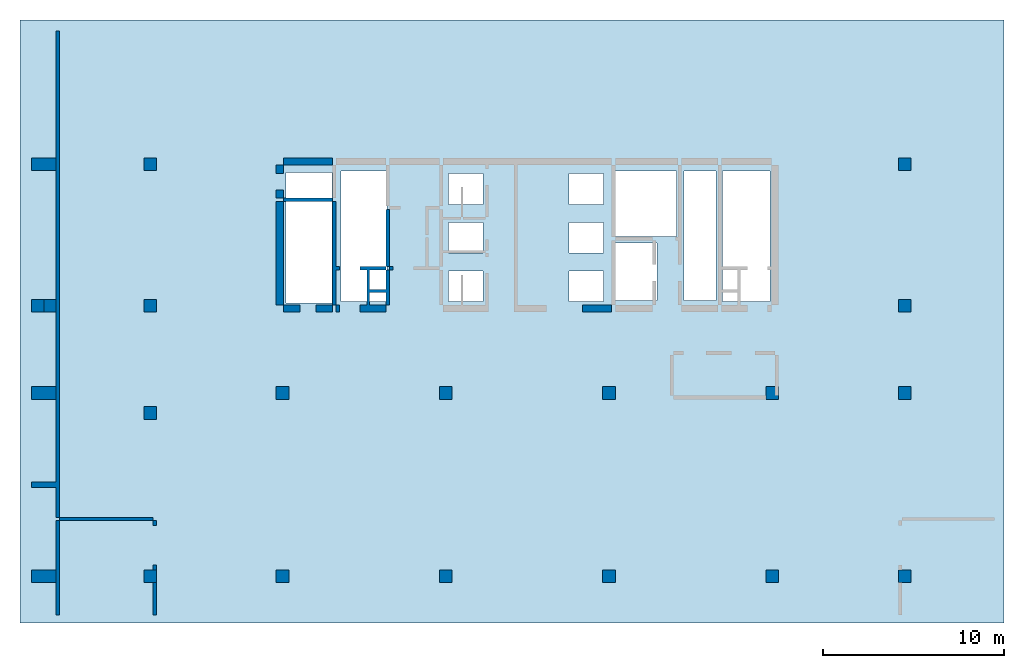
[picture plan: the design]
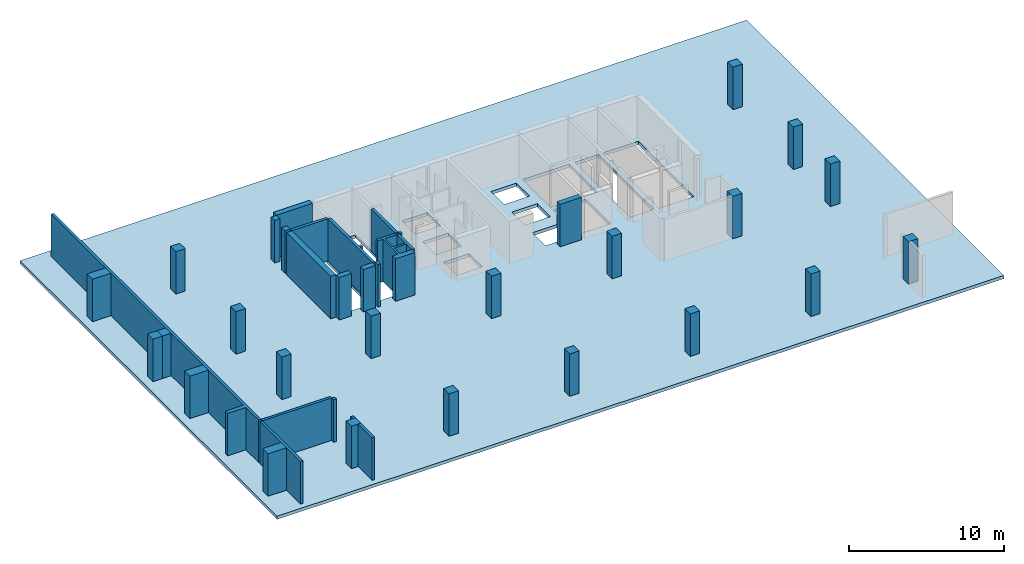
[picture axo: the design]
# One storey, part 1 of 2: 21 columns, 19 walls, 1 slab.
"""IFC4 building model written with IfcOpenShell, lengths in millimetres."""

from ifc_helpers import new_model, si_unit, frame, origin, place, context, project, spatial, triangles, element, save


model = new_model("IFC4")

# Units and contexts
model_context = context("Model", 3, precision=0.001, world=origin())
ifc_project = project(units=[si_unit("LENGTHUNIT", "METRE", prefix="MILLI"), si_unit("AREAUNIT", "SQUARE_METRE"), si_unit("VOLUMEUNIT", "CUBIC_METRE")], contexts=[model_context])

# Site, building, storey
site_placement = place(None, origin())
site = spatial("IfcSite", under=ifc_project, at=site_placement, CompositionType="ELEMENT")
building_placement = place(site_placement, origin())
building = spatial("IfcBuilding", under=site, at=building_placement, CompositionType="ELEMENT")
storey_placement = place(building_placement, frame((0.0, 0.0, -19800.0)))
storey = spatial("IfcBuildingStorey", under=building, at=storey_placement, Name="B5", CompositionType="ELEMENT", Elevation=-19800.0)

# Columns
column_1_placement = place(storey_placement, origin())
element("IfcColumn", 1, at=column_1_placement, inside=storey, Name="B5_Columns_B5_001", context=model_context, shape_type="Tessellation", body=[
    triangles([(40114.8, 2023.7, 0.0), (40114.8, 2023.7, 3350.0), (40114.8, 2722.3, 0.0), (40114.8, 2722.3, 3350.0), (40813.0, 2023.7, 3350.0), (40813.0, 2023.7, 0.0), (40813.0, 2722.3, 0.0), (40813.0, 2722.3, 3350.0)], [[1, 2, 3], [3, 2, 4], [5, 6, 7], [5, 7, 8], [6, 5, 1], [1, 5, 2], [8, 7, 3], [8, 3, 4], [3, 7, 1], [1, 7, 6], [8, 4, 2], [8, 2, 5]], closed=True),
])
column_2_placement = place(storey_placement, origin())
element("IfcColumn", 2, at=column_2_placement, inside=storey, Name="B5_Columns_B5_002", context=model_context, shape_type="Tessellation", body=[
    triangles([(5843.1, 24721.0, 0.0), (5843.1, 24721.0, 3350.0), (5843.1, 25419.5, 0.0), (5843.1, 25419.5, 3350.0), (6541.2, 24721.0, 3350.0), (6541.2, 24721.0, 0.0), (6541.2, 25419.5, 0.0), (6541.2, 25419.5, 3350.0)], [[1, 2, 3], [3, 2, 4], [5, 6, 7], [5, 7, 8], [6, 5, 1], [1, 5, 2], [8, 7, 3], [8, 3, 4], [1, 3, 6], [3, 7, 6], [4, 2, 5], [8, 4, 5]], closed=True),
])
column_3_placement = place(storey_placement, origin())
element("IfcColumn", 3, at=column_3_placement, inside=storey, Name="B5_Columns_B5_003", context=model_context, shape_type="Tessellation", body=[
    triangles([(5843.1, 16922.4, 0.0), (5843.1, 16922.4, 3350.0), (5843.1, 17620.9, 0.0), (5843.1, 17620.9, 3350.0), (6541.2, 16922.4, 3350.0), (6541.2, 16922.4, 0.0), (6541.2, 17620.9, 0.0), (6541.2, 17620.9, 3350.0)], [[1, 2, 3], [3, 2, 4], [5, 6, 7], [5, 7, 8], [6, 5, 1], [1, 5, 2], [8, 7, 3], [8, 3, 4], [1, 3, 6], [3, 7, 6], [4, 2, 5], [8, 4, 5]], closed=True),
])
column_4_placement = place(storey_placement, origin())
element("IfcColumn", 4, at=column_4_placement, inside=storey, Name="B5_Columns_B5_004", context=model_context, shape_type="Tessellation", body=[
    triangles([(47413.4, 24721.0, 0.0), (47413.4, 24721.0, 3350.0), (47413.4, 25419.5, 0.0), (47413.4, 25419.5, 3350.0), (48111.6, 24721.0, 3350.0), (48111.6, 24721.0, 0.0), (48111.6, 25419.5, 0.0), (48111.6, 25419.5, 3350.0)], [[1, 2, 3], [3, 2, 4], [5, 6, 7], [5, 7, 8], [6, 5, 1], [1, 5, 2], [8, 7, 3], [8, 3, 4], [1, 3, 6], [3, 7, 6], [4, 2, 5], [8, 4, 5]], closed=True),
])
column_5_placement = place(storey_placement, origin())
element("IfcColumn", 5, at=column_5_placement, inside=storey, Name="B5_Columns_B5_005", context=model_context, shape_type="Tessellation", body=[
    triangles([(47413.4, 16922.4, 0.0), (47413.4, 16922.4, 3350.0), (47413.4, 17620.9, 0.0), (47413.4, 17620.9, 3350.0), (48111.6, 16922.4, 3350.0), (48111.6, 16922.4, 0.0), (48111.6, 17620.9, 0.0), (48111.6, 17620.9, 3350.0)], [[1, 2, 3], [3, 2, 4], [5, 6, 7], [5, 7, 8], [6, 5, 1], [1, 5, 2], [8, 7, 3], [8, 3, 4], [1, 3, 6], [3, 7, 6], [4, 2, 5], [8, 4, 5]], closed=True),
])
column_6_placement = place(storey_placement, origin())
element("IfcColumn", 6, at=column_6_placement, inside=storey, Name="B5_Columns_B5_006", context=model_context, shape_type="Tessellation", body=[
    triangles([(-363.9, 16922.4, 0.0), (-363.9, 16922.4, 3350.0), (-363.9, 17620.9, 0.0), (-363.9, 17620.9, 3350.0), (994.3, 16922.4, 3350.0), (994.3, 16922.4, 0.0), (994.3, 17620.9, 0.0), (994.3, 17620.9, 3350.0)], [[1, 2, 3], [3, 2, 4], [5, 6, 7], [5, 7, 8], [6, 5, 1], [1, 5, 2], [8, 7, 3], [8, 3, 4], [3, 7, 1], [1, 7, 6], [8, 4, 2], [8, 2, 5]], closed=True),
])
column_7_placement = place(storey_placement, origin())
element("IfcColumn", 7, at=column_7_placement, inside=storey, Name="B5_Columns_B5_007", context=model_context, shape_type="Tessellation", body=[
    triangles([(13129.0, 2023.7, 0.0), (13129.0, 2023.7, 3350.0), (13129.0, 2722.3, 0.0), (13129.0, 2722.3, 3350.0), (13827.2, 2023.7, 3350.0), (13827.2, 2023.7, 0.0), (13827.2, 2722.3, 0.0), (13827.2, 2722.3, 3350.0)], [[1, 2, 3], [3, 2, 4], [5, 6, 7], [5, 7, 8], [6, 5, 1], [1, 5, 2], [8, 7, 3], [8, 3, 4], [3, 7, 1], [1, 7, 6], [8, 4, 2], [8, 2, 5]], closed=True),
])
column_8_placement = place(storey_placement, origin())
element("IfcColumn", 8, at=column_8_placement, inside=storey, Name="B5_Columns_B5_008", context=model_context, shape_type="Tessellation", body=[
    triangles([(-363.9, 16922.4, 0.0), (-363.9, 16922.4, 3350.0), (-363.9, 17620.9, 0.0), (-363.9, 17620.9, 3350.0), (334.3, 16922.4, 3350.0), (334.3, 16922.4, 0.0), (334.3, 17620.9, 0.0), (334.3, 17620.9, 3350.0)], [[1, 2, 3], [3, 2, 4], [5, 6, 7], [5, 7, 8], [6, 5, 1], [1, 5, 2], [8, 7, 3], [8, 3, 4], [3, 7, 1], [1, 7, 6], [8, 4, 2], [8, 2, 5]], closed=True),
])
column_9_placement = place(storey_placement, origin())
element("IfcColumn", 9, at=column_9_placement, inside=storey, Name="B5_Columns_B5_009", context=model_context, shape_type="Tessellation", body=[
    triangles([(47413.4, 2023.7, 0.0), (47413.4, 2023.7, 3350.0), (47413.4, 2722.3, 0.0), (47413.4, 2722.3, 3350.0), (48111.6, 2023.7, 3350.0), (48111.6, 2023.7, 0.0), (48111.6, 2722.3, 0.0), (48111.6, 2722.3, 3350.0)], [[1, 2, 3], [3, 2, 4], [5, 6, 7], [5, 7, 8], [6, 5, 1], [1, 5, 2], [8, 7, 3], [8, 3, 4], [3, 7, 1], [1, 7, 6], [8, 4, 2], [8, 2, 5]], closed=True),
])
column_10_placement = place(storey_placement, origin())
element("IfcColumn", 10, at=column_10_placement, inside=storey, Name="B5_Columns_B5_010", context=model_context, shape_type="Tessellation", body=[
    triangles([(13129.0, 12121.3, 0.0), (13129.0, 12121.3, 3350.0), (13129.0, 12819.8, 0.0), (13129.0, 12819.8, 3350.0), (13827.2, 12121.3, 3350.0), (13827.2, 12121.3, 0.0), (13827.2, 12819.8, 0.0), (13827.2, 12819.8, 3350.0)], [[1, 2, 3], [3, 2, 4], [5, 6, 7], [5, 7, 8], [6, 5, 1], [1, 5, 2], [8, 7, 3], [8, 3, 4], [3, 7, 1], [1, 7, 6], [8, 4, 2], [8, 2, 5]], closed=True),
])
column_11_placement = place(storey_placement, origin())
element("IfcColumn", 11, at=column_11_placement, inside=storey, Name="B5_Columns_B5_011", context=model_context, shape_type="Tessellation", body=[
    triangles([(5843.1, 11016.3, 0.0), (5843.1, 11016.3, 3350.0), (5843.1, 11727.5, 0.0), (5843.1, 11727.5, 3350.0), (6541.2, 11016.3, 3350.0), (6541.2, 11016.3, 0.0), (6541.2, 11727.5, 0.0), (6541.2, 11727.5, 3350.0)], [[1, 2, 3], [3, 2, 4], [5, 6, 7], [5, 7, 8], [6, 5, 1], [1, 5, 2], [8, 7, 3], [8, 3, 4], [3, 7, 1], [1, 7, 6], [8, 4, 2], [8, 2, 5]], closed=True),
])
column_12_placement = place(storey_placement, origin())
element("IfcColumn", 12, at=column_12_placement, inside=storey, Name="B5_Columns_B5_012", context=model_context, shape_type="Tessellation", body=[
    triangles([(40114.8, 12121.3, 0.0), (40114.8, 12121.3, 3350.0), (40114.8, 12819.8, 0.0), (40114.8, 12819.8, 3350.0), (40813.0, 12121.3, 3350.0), (40813.0, 12121.3, 0.0), (40813.0, 12819.8, 0.0), (40813.0, 12819.8, 3350.0)], [[1, 2, 3], [3, 2, 4], [5, 6, 7], [5, 7, 8], [6, 5, 1], [1, 5, 2], [8, 7, 3], [8, 3, 4], [1, 3, 6], [3, 7, 6], [4, 2, 5], [8, 4, 5]], closed=True),
])
column_13_placement = place(storey_placement, origin())
element("IfcColumn", 13, at=column_13_placement, inside=storey, Name="B5_Columns_B5_013", context=model_context, shape_type="Tessellation", body=[
    triangles([(47413.4, 12121.3, 0.0), (47413.4, 12121.3, 3350.0), (47413.4, 12819.8, 0.0), (47413.4, 12819.8, 3350.0), (48111.6, 12121.3, 3350.0), (48111.6, 12121.3, 0.0), (48111.6, 12819.8, 0.0), (48111.6, 12819.8, 3350.0)], [[1, 2, 3], [3, 2, 4], [5, 6, 7], [5, 7, 8], [6, 5, 1], [1, 5, 2], [8, 7, 3], [8, 3, 4], [1, 3, 6], [3, 7, 6], [4, 2, 5], [8, 4, 5]], closed=True),
])
column_14_placement = place(storey_placement, origin())
element("IfcColumn", 14, at=column_14_placement, inside=storey, Name="B5_Columns_B5_014", context=model_context, shape_type="Tessellation", body=[
    triangles([(5843.1, 2023.7, 0.0), (5843.1, 2023.7, 3350.0), (5843.1, 2722.3, 0.0), (5843.1, 2722.3, 3350.0), (6541.2, 2023.7, 3350.0), (6541.2, 2023.7, 0.0), (6541.2, 2722.3, 0.0), (6541.2, 2722.3, 3350.0)], [[1, 2, 3], [3, 2, 4], [5, 6, 7], [5, 7, 8], [6, 5, 1], [1, 5, 2], [8, 7, 3], [8, 3, 4], [1, 3, 6], [3, 7, 6], [4, 2, 5], [8, 4, 5]], closed=True),
])
column_15_placement = place(storey_placement, origin())
element("IfcColumn", 15, at=column_15_placement, inside=storey, Name="B5_Columns_B5_015", context=model_context, shape_type="Tessellation", body=[
    triangles([(-363.9, 2023.7, 0.0), (-363.9, 2023.7, 3350.0), (-363.9, 2722.3, 0.0), (-363.9, 2722.3, 3350.0), (994.3, 2023.7, 3350.0), (994.3, 2023.7, 0.0), (994.3, 2722.3, 0.0), (994.3, 2722.3, 3350.0)], [[1, 2, 3], [3, 2, 4], [5, 6, 7], [5, 7, 8], [6, 5, 1], [1, 5, 2], [8, 7, 3], [8, 3, 4], [3, 7, 1], [1, 7, 6], [8, 4, 2], [8, 2, 5]], closed=True),
])
column_16_placement = place(storey_placement, origin())
element("IfcColumn", 16, at=column_16_placement, inside=storey, Name="B5_Columns_B5_016", context=model_context, shape_type="Tessellation", body=[
    triangles([(-363.9, 24721.0, 0.0), (-363.9, 24721.0, 3350.0), (-363.9, 25419.5, 0.0), (-363.9, 25419.5, 3350.0), (994.3, 24721.0, 3350.0), (994.3, 24721.0, 0.0), (994.3, 25419.5, 0.0), (994.3, 25419.5, 3350.0)], [[1, 2, 3], [3, 2, 4], [5, 6, 7], [5, 7, 8], [6, 5, 1], [1, 5, 2], [8, 7, 3], [8, 3, 4], [3, 7, 1], [1, 7, 6], [8, 4, 2], [8, 2, 5]], closed=True),
])
column_17_placement = place(storey_placement, origin())
element("IfcColumn", 17, at=column_17_placement, inside=storey, Name="B5_Columns_B5_017", context=model_context, shape_type="Tessellation", body=[
    triangles([(-363.9, 12121.3, 0.0), (-363.9, 12121.3, 3350.0), (-363.9, 12819.8, 0.0), (-363.9, 12819.8, 3350.0), (994.3, 12121.3, 3350.0), (994.3, 12121.3, 0.0), (994.3, 12819.8, 0.0), (994.3, 12819.8, 3350.0)], [[1, 2, 3], [3, 2, 4], [5, 6, 7], [5, 7, 8], [6, 5, 1], [1, 5, 2], [8, 7, 3], [8, 3, 4], [3, 7, 1], [1, 7, 6], [8, 4, 2], [8, 2, 5]], closed=True),
])
column_18_placement = place(storey_placement, origin())
element("IfcColumn", 18, at=column_18_placement, inside=storey, Name="B5_Columns_B5_018", context=model_context, shape_type="Tessellation", body=[
    triangles([(31128.0, 12121.3, 0.0), (31128.0, 12121.3, 3350.0), (31128.0, 12819.8, 0.0), (31128.0, 12819.8, 3350.0), (31826.2, 12121.3, 3350.0), (31826.2, 12121.3, 0.0), (31826.2, 12819.8, 0.0), (31826.2, 12819.8, 3350.0)], [[1, 2, 3], [3, 2, 4], [5, 6, 7], [5, 7, 8], [6, 5, 1], [1, 5, 2], [8, 7, 3], [8, 3, 4], [3, 7, 1], [1, 7, 6], [8, 4, 2], [8, 2, 5]], closed=True),
])
column_19_placement = place(storey_placement, origin())
element("IfcColumn", 19, at=column_19_placement, inside=storey, Name="B5_Columns_B5_019", context=model_context, shape_type="Tessellation", body=[
    triangles([(22128.5, 12121.3, 0.0), (22128.5, 12121.3, 3350.0), (22128.5, 12819.8, 0.0), (22128.5, 12819.8, 3350.0), (22826.7, 12121.3, 3350.0), (22826.7, 12121.3, 0.0), (22826.7, 12819.8, 0.0), (22826.7, 12819.8, 3350.0)], [[1, 2, 3], [3, 2, 4], [5, 6, 7], [5, 7, 8], [6, 5, 1], [1, 5, 2], [8, 7, 3], [8, 3, 4], [3, 7, 1], [1, 7, 6], [8, 4, 2], [8, 2, 5]], closed=True),
])
column_20_placement = place(storey_placement, origin())
element("IfcColumn", 20, at=column_20_placement, inside=storey, Name="B5_Columns_B5_020", context=model_context, shape_type="Tessellation", body=[
    triangles([(31128.0, 2023.7, 0.0), (31128.0, 2023.7, 3350.0), (31128.0, 2722.3, 0.0), (31128.0, 2722.3, 3350.0), (31826.2, 2023.7, 3350.0), (31826.2, 2023.7, 0.0), (31826.2, 2722.3, 0.0), (31826.2, 2722.3, 3350.0)], [[1, 2, 3], [3, 2, 4], [5, 6, 7], [5, 7, 8], [6, 5, 1], [1, 5, 2], [8, 7, 3], [8, 3, 4], [3, 7, 1], [1, 7, 6], [8, 4, 2], [8, 2, 5]], closed=True),
])
column_21_placement = place(storey_placement, origin())
element("IfcColumn", 21, at=column_21_placement, inside=storey, Name="B5_Columns_B5_021", context=model_context, shape_type="Tessellation", body=[
    triangles([(22128.5, 2023.7, 0.0), (22128.5, 2023.7, 3350.0), (22128.5, 2722.3, 0.0), (22128.5, 2722.3, 3350.0), (22826.7, 2023.7, 3350.0), (22826.7, 2023.7, 0.0), (22826.7, 2722.3, 0.0), (22826.7, 2722.3, 3350.0)], [[1, 2, 3], [3, 2, 4], [5, 6, 7], [5, 7, 8], [6, 5, 1], [1, 5, 2], [8, 7, 3], [8, 3, 4], [3, 7, 1], [1, 7, 6], [8, 4, 2], [8, 2, 5]], closed=True),
])

# Slab
slab_placement = place(storey_placement, origin())
element("IfcSlab", 22, at=slab_placement, inside=storey, Name="B5_Slab_B5_001", context=model_context, shape_type="Tessellation", body=[
    triangles([(-987.250996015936, 33023.3766233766, 0.0), (53241.0358565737, 33023.3766233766, 0.0), (-987.250996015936, 33023.3766233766, -250.0), (53241.0358565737, 33023.3766233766, -250.0), (-987.250996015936, -211.688311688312, 0.0), (-987.250996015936, -211.688311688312, -250.0), (53241.0358565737, -211.688311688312, 0.0), (53241.0358565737, -211.688311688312, -250.0), (34130.6772908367, 20745.4545454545, -250.0), (31733.0677290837, 20745.4545454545, 0.0), (31733.0677290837, 20745.4545454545, -250.0), (34130.6772908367, 20745.4545454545, 0.0), (31733.0677290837, 17570.1298701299, 0.0), (31733.0677290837, 17570.1298701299, -250.0), (34130.6772908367, 17570.1298701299, 0.0), (34130.6772908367, 17570.1298701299, -250.0), (31168.9243027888, 19193.0735930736, 0.0), (29264.9402390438, 19193.0735930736, 0.0), (29264.9402390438, 19193.0735930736, -250.0), (31168.9243027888, 19193.0735930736, -250.0), (31168.9243027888, 17499.5670995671, 0.0), (31168.9243027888, 17499.5670995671, -250.0), (29264.9402390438, 17499.5670995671, 0.0), (29264.9402390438, 17499.5670995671, -250.0), (31168.9243027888, 21874.4588744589, 0.0), (29264.9402390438, 21874.4588744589, 0.0), (29264.9402390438, 21874.4588744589, -250.0), (31168.9243027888, 21874.4588744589, -250.0), (29264.9402390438, 20180.9523809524, 0.0), (29264.9402390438, 20180.9523809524, -250.0), (31168.9243027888, 20180.9523809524, 0.0), (31168.9243027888, 20180.9523809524, -250.0), (24540.2390438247, 19193.0735930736, -250.0), (22636.2549800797, 19193.0735930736, 0.0), (22636.2549800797, 19193.0735930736, -250.0), (24540.2390438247, 19193.0735930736, 0.0), (22636.2549800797, 17499.5670995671, 0.0), (22636.2549800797, 17499.5670995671, -250.0), (24540.2390438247, 17499.5670995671, 0.0), (24540.2390438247, 17499.5670995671, -250.0), (24540.2390438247, 21874.4588744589, -250.0), (22636.2549800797, 21874.4588744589, 0.0), (22636.2549800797, 21874.4588744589, -250.0), (24540.2390438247, 21874.4588744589, 0.0), (22636.2549800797, 20180.9523809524, 0.0), (22636.2549800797, 20180.9523809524, -250.0), (24540.2390438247, 20180.9523809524, 0.0), (24540.2390438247, 20180.9523809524, -250.0), (16219.1235059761, 24626.4069264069, 0.0), (13680.4780876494, 24626.4069264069, 0.0), (13680.4780876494, 24626.4069264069, -250.0), (16219.1235059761, 24626.4069264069, -250.0), (13680.4780876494, 17429.0043290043, 0.0), (13680.4780876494, 17429.0043290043, -250.0), (16219.1235059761, 17429.0043290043, 0.0), (16219.1235059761, 17429.0043290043, -250.0), (40336.2549800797, 24696.9696969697, -250.0), (37727.0916334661, 24696.9696969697, 0.0), (37727.0916334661, 24696.9696969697, -250.0), (40336.2549800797, 24696.9696969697, 0.0), (37727.0916334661, 17499.5670995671, 0.0), (37727.0916334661, 17499.5670995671, -250.0), (40336.2549800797, 17499.5670995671, 0.0), (40336.2549800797, 17499.5670995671, -250.0), (37374.5019920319, 24696.9696969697, 0.0), (35611.5537848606, 24696.9696969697, 0.0), (35611.5537848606, 24696.9696969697, -250.0), (37374.5019920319, 24696.9696969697, -250.0), (35611.5537848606, 17570.1298701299, 0.0), (35611.5537848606, 17570.1298701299, -250.0), (37374.5019920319, 17570.1298701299, 0.0), (37374.5019920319, 17570.1298701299, -250.0), (35188.4462151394, 24696.9696969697, 0.0), (31733.0677290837, 24696.9696969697, 0.0), (31733.0677290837, 24696.9696969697, -250.0), (35188.4462151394, 24696.9696969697, -250.0), (31733.0677290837, 21098.2683982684, 0.0), (31733.0677290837, 21098.2683982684, -250.0), (35188.4462151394, 21098.2683982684, 0.0), (35188.4462151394, 21098.2683982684, -250.0), (31168.9243027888, 24555.8441558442, 0.0), (29264.9402390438, 24555.8441558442, 0.0), (29264.9402390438, 24555.8441558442, -250.0), (31168.9243027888, 24555.8441558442, -250.0), (29264.9402390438, 22862.3376623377, 0.0), (29264.9402390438, 22862.3376623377, -250.0), (31168.9243027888, 22862.3376623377, 0.0), (31168.9243027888, 22862.3376623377, -250.0), (19251.3944223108, 24696.9696969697, 0.0), (16712.7490039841, 24696.9696969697, 0.0), (16712.7490039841, 24696.9696969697, -250.0), (19251.3944223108, 24696.9696969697, -250.0), (16712.7490039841, 17499.5670995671, 0.0), (16712.7490039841, 17499.5670995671, -250.0), (19251.3944223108, 17499.5670995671, 0.0), (19251.3944223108, 17499.5670995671, -250.0), (24540.2390438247, 24555.8441558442, -250.0), (22636.2549800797, 24555.8441558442, 0.0), (22636.2549800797, 24555.8441558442, -250.0), (24540.2390438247, 24555.8441558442, 0.0), (22636.2549800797, 22862.3376623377, 0.0), (22636.2549800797, 22862.3376623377, -250.0), (24540.2390438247, 22862.3376623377, 0.0), (24540.2390438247, 22862.3376623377, -250.0)], [[1, 2, 3], [3, 2, 4], [5, 1, 6], [6, 1, 3], [2, 7, 4], [4, 7, 8], [7, 5, 8], [8, 5, 6], [9, 10, 11], [12, 10, 9], [10, 13, 14], [10, 14, 11], [15, 12, 9], [15, 9, 16], [14, 15, 16], [13, 15, 14], [17, 18, 19], [17, 19, 20], [21, 17, 20], [21, 20, 22], [23, 21, 22], [23, 22, 24], [18, 23, 24], [18, 24, 19], [25, 26, 27], [25, 27, 28], [26, 29, 30], [26, 30, 27], [31, 25, 28], [31, 28, 32], [29, 31, 32], [29, 32, 30], [33, 34, 35], [36, 34, 33], [34, 37, 38], [34, 38, 35], [39, 36, 33], [39, 33, 40], [38, 39, 40], [37, 39, 38], [41, 42, 43], [44, 42, 41], [42, 45, 46], [42, 46, 43], [47, 44, 41], [47, 41, 48], [46, 47, 48], [45, 47, 46], [49, 50, 51], [49, 51, 52], [50, 53, 54], [50, 54, 51], [55, 49, 52], [55, 52, 56], [53, 55, 56], [53, 56, 54], [57, 58, 59], [60, 58, 57], [58, 61, 62], [58, 62, 59], [63, 60, 57], [63, 57, 64], [62, 63, 64], [61, 63, 62], [65, 66, 67], [65, 67, 68], [66, 69, 70], [66, 70, 67], [71, 65, 68], [71, 68, 72], [69, 71, 72], [69, 72, 70], [73, 74, 75], [73, 75, 76], [74, 77, 78], [74, 78, 75], [79, 73, 76], [79, 76, 80], [77, 79, 80], [77, 80, 78], [81, 82, 83], [81, 83, 84], [82, 85, 86], [82, 86, 83], [87, 81, 84], [87, 84, 88], [85, 87, 88], [85, 88, 86], [89, 90, 91], [89, 91, 92], [90, 93, 94], [90, 94, 91], [95, 89, 92], [95, 92, 96], [93, 95, 96], [93, 96, 94], [97, 98, 99], [100, 98, 97], [98, 101, 102], [98, 102, 99], [103, 100, 97], [103, 97, 104], [102, 103, 104], [101, 103, 102], [63, 61, 7], [7, 2, 63], [71, 69, 61], [61, 69, 7], [69, 15, 7], [2, 60, 63], [13, 21, 15], [15, 21, 7], [79, 12, 69], [69, 12, 15], [2, 58, 60], [2, 65, 58], [13, 17, 21], [21, 23, 7], [17, 10, 31], [2, 66, 65], [12, 77, 10], [10, 77, 31], [2, 73, 66], [66, 73, 79], [31, 18, 17], [77, 25, 31], [31, 29, 18], [77, 87, 25], [23, 39, 7], [2, 74, 73], [74, 81, 87], [87, 85, 25], [25, 85, 26], [23, 36, 39], [18, 36, 23], [74, 82, 81], [29, 47, 18], [18, 47, 36], [26, 44, 29], [29, 44, 47], [47, 45, 36], [36, 45, 34], [34, 95, 37], [45, 95, 34], [85, 103, 26], [26, 103, 44], [82, 103, 85], [45, 42, 95], [103, 42, 44], [82, 100, 103], [103, 101, 42], [39, 5, 7], [37, 5, 39], [95, 5, 37], [95, 55, 5], [93, 55, 95], [55, 53, 5], [101, 89, 42], [42, 89, 95], [98, 89, 101], [90, 49, 93], [93, 49, 55], [90, 50, 49], [50, 1, 53], [89, 1, 90], [53, 1, 5], [90, 1, 50], [2, 1, 74], [74, 1, 82], [82, 1, 100], [100, 1, 98], [98, 1, 89], [13, 10, 17], [69, 66, 79], [65, 71, 58], [58, 71, 61], [77, 74, 87], [79, 77, 12], [62, 64, 8], [4, 8, 64], [70, 72, 62], [70, 62, 8], [16, 70, 8], [57, 4, 64], [22, 14, 16], [22, 16, 8], [9, 80, 70], [9, 70, 16], [59, 4, 57], [68, 4, 59], [20, 14, 22], [24, 22, 8], [11, 20, 32], [67, 4, 68], [78, 9, 11], [78, 11, 32], [76, 4, 67], [76, 67, 80], [19, 32, 20], [28, 78, 32], [30, 32, 19], [88, 78, 28], [40, 24, 8], [75, 4, 76], [84, 75, 88], [86, 88, 28], [86, 28, 27], [33, 24, 40], [33, 19, 24], [83, 75, 84], [48, 30, 19], [48, 19, 33], [41, 27, 30], [41, 30, 48], [46, 48, 33], [46, 33, 35], [96, 35, 38], [96, 46, 35], [104, 86, 27], [104, 27, 41], [104, 83, 86], [43, 46, 96], [43, 104, 41], [97, 83, 104], [102, 104, 43], [6, 40, 8], [6, 38, 40], [6, 96, 38], [56, 96, 6], [56, 94, 96], [54, 56, 6], [92, 102, 43], [92, 43, 96], [92, 99, 102], [52, 91, 94], [52, 94, 56], [51, 91, 52], [3, 51, 54], [3, 92, 91], [3, 54, 6], [3, 91, 51], [3, 4, 75], [3, 75, 83], [3, 83, 97], [3, 97, 99], [3, 99, 92], [11, 14, 20], [67, 70, 80], [72, 68, 59], [72, 59, 62], [75, 78, 88], [78, 80, 9]], closed=True),
])

# Walls
wall_1_placement = place(storey_placement, origin())
element("IfcWall", 23, at=wall_1_placement, inside=storey, Name="B5_Walls_B5_001", context=model_context, shape_type="Tessellation", body=[
    triangles([(6541.2, 2023.7, 0.0), (6338.1, 2023.7, 0.0), (6338.1, 2023.7, 3350.0), (6541.2, 2023.7, 3350.0), (6541.2, 220.2, 0.0), (6541.2, 220.2, 3350.0), (6338.1, 220.2, 0.0), (6338.1, 220.2, 3350.0)], [[1, 2, 3], [1, 3, 4], [5, 1, 4], [5, 4, 6], [7, 5, 6], [7, 6, 8], [2, 7, 8], [2, 8, 3], [2, 1, 5], [2, 5, 7], [4, 3, 6], [6, 3, 8]], closed=True),
])
wall_2_placement = place(storey_placement, origin())
element("IfcWall", 24, at=wall_2_placement, inside=storey, Name="B5_Walls_B5_002", context=model_context, shape_type="Tessellation", body=[
    triangles([(1184.7, 220.2, 0.0), (1184.7, 5427.7, 0.0), (1184.7, 5427.7, 3350.0), (1184.7, 220.2, 3350.0), (994.3, 220.2, 0.0), (994.3, 220.2, 3350.0), (994.3, 5427.7, 0.0), (994.3, 5427.7, 3350.0)], [[1, 2, 3], [1, 3, 4], [5, 1, 4], [5, 4, 6], [7, 5, 6], [7, 6, 8], [2, 7, 8], [2, 8, 3], [7, 2, 1], [7, 1, 5], [3, 8, 4], [4, 8, 6]], closed=True),
])
wall_3_placement = place(storey_placement, origin())
element("IfcWall", 25, at=wall_3_placement, inside=storey, Name="B5_Walls_B5_003", context=model_context, shape_type="Tessellation", body=[
    triangles([(6541.2, 2722.3, 0.0), (6541.2, 2976.3, 0.0), (6541.2, 2976.3, 3350.0), (6541.2, 2722.3, 3350.0), (6338.1, 2722.3, 0.0), (6338.1, 2722.3, 3350.0), (6338.1, 2976.3, 0.0), (6338.1, 2976.3, 3350.0)], [[1, 2, 3], [1, 3, 4], [5, 1, 4], [5, 4, 6], [7, 5, 6], [7, 6, 8], [2, 7, 8], [2, 8, 3], [2, 1, 5], [7, 2, 5], [4, 3, 6], [3, 8, 6]], closed=True),
])
wall_4_placement = place(storey_placement, origin())
element("IfcWall", 26, at=wall_4_placement, inside=storey, Name="B5_Walls_B5_004", context=model_context, shape_type="Tessellation", body=[
    triangles([(6338.1, 5173.7, 0.0), (6541.2, 5173.7, 0.0), (6541.2, 5173.7, 3350.0), (6338.1, 5173.7, 3350.0), (6338.1, 5427.7, 0.0), (6338.1, 5427.7, 3350.0), (6541.2, 5427.7, 0.0), (6541.2, 5427.7, 3350.0)], [[1, 2, 3], [1, 3, 4], [5, 1, 4], [5, 4, 6], [7, 5, 6], [7, 6, 8], [2, 7, 8], [2, 8, 3], [7, 2, 1], [5, 7, 1], [3, 8, 4], [8, 6, 4]], closed=True),
])
wall_5_placement = place(storey_placement, origin())
element("IfcWall", 27, at=wall_5_placement, inside=storey, Name="B5_Walls_B5_005", context=model_context, shape_type="Tessellation", body=[
    triangles([(6338.1, 5427.7, 0.0), (6338.1, 5618.2, 0.0), (6338.1, 5618.2, 3350.0), (6338.1, 5427.7, 3350.0), (1184.7, 5427.7, 0.0), (1184.7, 5427.7, 3350.0), (1184.7, 5618.2, 0.0), (1184.7, 5618.2, 3350.0)], [[1, 2, 3], [1, 3, 4], [5, 1, 4], [5, 4, 6], [7, 5, 6], [7, 6, 8], [2, 7, 8], [2, 8, 3], [7, 2, 1], [7, 1, 5], [3, 8, 4], [4, 8, 6]], closed=True),
])
wall_6_placement = place(storey_placement, origin())
element("IfcWall", 28, at=wall_6_placement, inside=storey, Name="B5_Walls_B5_006", context=model_context, shape_type="Tessellation", body=[
    triangles([(-365.0, 7575.0, 0.0), (-365.0, 7270.0, 0.0), (-365.0, 7270.0, 3350.0), (-365.0, 7575.0, 3350.0), (994.3, 7575.0, 0.0), (994.3, 7575.0, 3350.0), (994.3, 32417.9, 0.0), (994.3, 32417.9, 3350.0), (1184.7, 32417.9, 0.0), (1184.7, 32417.9, 3350.0), (1184.7, 5618.2, 0.0), (1184.7, 5618.2, 3350.0), (994.3, 5618.2, 0.0), (994.3, 5618.2, 3350.0), (994.3, 7269.4, 0.0), (994.3, 7269.4, 3350.0), (-363.9, 7269.4, 0.0), (-363.9, 7269.4, 3350.0), (-363.9, 7270.0, 0.0), (-363.9, 7270.0, 3350.0)], [[1, 2, 3], [1, 3, 4], [5, 1, 4], [5, 4, 6], [7, 5, 6], [7, 6, 8], [9, 7, 8], [9, 8, 10], [11, 9, 10], [11, 10, 12], [13, 11, 12], [13, 12, 14], [15, 13, 14], [15, 14, 16], [17, 15, 16], [17, 16, 18], [19, 17, 18], [19, 18, 20], [2, 19, 20], [2, 20, 3], [15, 11, 13], [5, 11, 15], [19, 15, 17], [19, 5, 15], [1, 19, 2], [1, 5, 19], [7, 9, 5], [9, 11, 5], [12, 16, 14], [12, 6, 16], [16, 20, 18], [6, 20, 16], [20, 4, 3], [6, 4, 20], [10, 8, 6], [12, 10, 6]], closed=True),
])
wall_7_placement = place(storey_placement, origin())
element("IfcWall", 29, at=wall_7_placement, inside=storey, Name="B5_Walls_B5_007", context=model_context, shape_type="Tessellation", body=[
    triangles([(14436.4, 16922.4, 0.0), (14436.4, 17316.1, 0.0), (14436.4, 17316.1, 3350.0), (14436.4, 16922.4, 3350.0), (13535.2, 16922.4, 0.0), (13535.2, 16922.4, 3350.0), (13535.2, 17316.1, 0.0), (13535.2, 17316.1, 3350.0)], [[1, 2, 3], [1, 3, 4], [5, 1, 4], [5, 4, 6], [7, 5, 6], [7, 6, 8], [2, 7, 8], [2, 8, 3], [7, 2, 1], [7, 1, 5], [3, 8, 4], [4, 8, 6]], closed=True),
])
wall_8_placement = place(storey_placement, origin())
element("IfcWall", 30, at=wall_8_placement, inside=storey, Name="B5_Walls_B5_008", context=model_context, shape_type="Tessellation", body=[
    triangles([(16226.2, 16922.4, 0.0), (16226.2, 17316.1, 0.0), (16226.2, 17316.1, 3350.0), (16226.2, 16922.4, 3350.0), (15337.6, 16922.4, 0.0), (15337.6, 16922.4, 3350.0), (15337.6, 17316.1, 0.0), (15337.6, 17316.1, 3350.0)], [[1, 2, 3], [1, 3, 4], [5, 1, 4], [5, 4, 6], [7, 5, 6], [7, 6, 8], [2, 7, 8], [2, 8, 3], [7, 2, 1], [7, 1, 5], [3, 8, 4], [4, 8, 6]], closed=True),
])
wall_9_placement = place(storey_placement, origin())
element("IfcWall", 31, at=wall_9_placement, inside=storey, Name="B5_Walls_B5_009", context=model_context, shape_type="Tessellation", body=[
    triangles([(16632.4, 16922.4, 0.0), (16632.4, 17316.1, 0.0), (16632.4, 17316.1, 3350.0), (16632.4, 16922.4, 3350.0), (16429.3, 16922.4, 0.0), (16429.3, 16922.4, 3350.0), (16429.3, 17316.1, 0.0), (16429.3, 17316.1, 3350.0)], [[1, 2, 3], [1, 3, 4], [5, 1, 4], [5, 4, 6], [7, 5, 6], [7, 6, 8], [2, 7, 8], [2, 8, 3], [7, 2, 1], [7, 1, 5], [3, 8, 4], [4, 8, 6]], closed=True),
])
wall_10_placement = place(storey_placement, origin())
element("IfcWall", 32, at=wall_10_placement, inside=storey, Name="B5_Walls_B5_010", context=model_context, shape_type="Tessellation", body=[
    triangles([(18130.2, 19246.7, 0.0), (18130.2, 19245.0, 0.0), (18130.2, 19245.0, 3350.0), (18130.2, 19246.7, 3350.0), (18130.0, 19245.0, 0.0), (18130.0, 19245.0, 3350.0), (18130.0, 17316.1, 0.0), (18130.0, 17316.1, 3350.0), (17749.4, 17316.1, 0.0), (17749.4, 17316.1, 3350.0), (17749.4, 16922.4, 0.0), (17749.4, 16922.4, 3350.0), (19183.7, 16922.4, 0.0), (19183.7, 16922.4, 3350.0), (19183.7, 17316.1, 0.0), (19183.7, 17316.1, 3350.0), (19374.1, 17316.1, 0.0), (19374.1, 17316.1, 3350.0), (19374.1, 19246.7, 0.0), (19374.1, 19246.7, 3350.0), (19183.7, 19246.7, 0.0), (19183.7, 19246.7, 3350.0), (19183.7, 19449.9, 0.0), (19183.7, 19449.9, 3350.0), (17749.4, 19449.9, 0.0), (17749.4, 19449.9, 3350.0), (17749.4, 19246.7, 0.0), (17749.4, 19246.7, 3350.0), (18282.5, 17316.1, 0.0), (18282.5, 17316.1, 3350.0), (18282.5, 18014.7, 0.0), (18282.5, 18014.7, 3350.0), (19183.7, 18014.7, 0.0), (19183.7, 18014.7, 3350.0), (19183.7, 18167.1, 0.0), (19183.7, 18167.1, 3350.0), (18282.5, 18167.1, 0.0), (18282.5, 18167.1, 3350.0), (18282.5, 19246.7, 0.0), (18282.5, 19246.7, 3350.0)], [[1, 2, 3], [1, 3, 4], [2, 5, 6], [2, 6, 3], [5, 7, 8], [5, 8, 6], [7, 9, 10], [7, 10, 8], [9, 11, 12], [9, 12, 10], [11, 13, 14], [11, 14, 12], [13, 15, 16], [13, 16, 14], [15, 17, 18], [15, 18, 16], [19, 20, 18], [17, 19, 18], [19, 21, 22], [19, 22, 20], [21, 23, 24], [21, 24, 22], [23, 25, 26], [23, 26, 24], [25, 27, 28], [25, 28, 26], [27, 1, 4], [27, 4, 28], [15, 29, 30], [15, 30, 16], [29, 31, 32], [29, 32, 30], [31, 33, 34], [31, 34, 32], [33, 15, 16], [33, 16, 34], [21, 35, 36], [21, 36, 22], [35, 37, 38], [35, 38, 36], [37, 39, 40], [37, 40, 38], [39, 21, 22], [39, 22, 40], [33, 17, 15], [35, 17, 33], [29, 15, 13], [11, 29, 13], [7, 29, 11], [9, 7, 11], [31, 35, 33], [31, 29, 7], [19, 17, 35], [37, 35, 31], [21, 19, 35], [39, 23, 21], [2, 39, 37], [5, 2, 37], [1, 39, 2], [25, 1, 27], [25, 23, 39], [25, 39, 1], [7, 5, 37], [7, 37, 31], [18, 34, 16], [18, 36, 34], [16, 30, 14], [30, 12, 14], [30, 8, 12], [8, 10, 12], [36, 32, 34], [30, 32, 8], [18, 20, 36], [36, 38, 32], [20, 22, 36], [24, 40, 22], [40, 3, 38], [3, 6, 38], [40, 4, 3], [4, 26, 28], [24, 26, 40], [40, 26, 4], [6, 8, 38], [38, 8, 32]], closed=True),
])
wall_11_placement = place(storey_placement, origin())
element("IfcWall", 33, at=wall_11_placement, inside=storey, Name="B5_Walls_B5_011", context=model_context, shape_type="Tessellation", body=[
    triangles([(16632.4, 19449.9, 0.0), (16429.3, 19449.9, 0.0), (16429.3, 19449.9, 3350.0), (16632.4, 19449.9, 3350.0), (16632.4, 19246.7, 0.0), (16632.4, 19246.7, 3350.0), (16429.3, 19246.7, 0.0), (16429.3, 19246.7, 3350.0), (16429.3, 17316.1, 3350.0), (16429.3, 17316.1, 0.0), (16226.2, 17316.1, 0.0), (16226.2, 17316.1, 3350.0), (16226.2, 19246.7, 3350.0), (16226.2, 19246.7, 0.0), (16226.2, 19449.9, 0.0), (16226.2, 19449.9, 3350.0), (16226.2, 23019.0, 0.0), (16226.2, 23019.0, 3350.0), (16429.3, 23019.0, 0.0), (16429.3, 23019.0, 3350.0)], [[1, 2, 3], [1, 3, 4], [5, 1, 4], [5, 4, 6], [7, 5, 6], [7, 6, 8], [7, 8, 9], [10, 7, 9], [11, 10, 9], [11, 9, 12], [11, 12, 13], [14, 11, 13], [15, 14, 13], [15, 13, 16], [17, 15, 16], [17, 16, 18], [19, 17, 18], [19, 18, 20], [2, 19, 20], [2, 20, 3], [14, 7, 10], [14, 10, 11], [2, 1, 5], [2, 5, 7], [15, 2, 7], [15, 7, 14], [19, 2, 15], [17, 19, 15], [8, 13, 9], [9, 13, 12], [4, 3, 6], [6, 3, 8], [3, 16, 8], [8, 16, 13], [3, 20, 16], [20, 18, 16]], closed=True),
])
wall_12_placement = place(storey_placement, origin())
element("IfcWall", 34, at=wall_12_placement, inside=storey, Name="B5_Walls_B5_012", context=model_context, shape_type="Tessellation", body=[
    triangles([(13129.0, 23019.0, 0.0), (13129.0, 17316.1, 0.0), (13129.0, 17316.1, 3350.0), (13129.0, 23019.0, 3350.0), (13535.2, 23019.0, 0.0), (13535.2, 23019.0, 3350.0), (13535.2, 17316.1, 0.0), (13535.2, 17316.1, 3350.0)], [[1, 2, 3], [1, 3, 4], [5, 1, 4], [5, 4, 6], [7, 5, 6], [7, 6, 8], [2, 7, 8], [2, 8, 3], [1, 5, 7], [1, 7, 2], [6, 4, 8], [8, 4, 3]], closed=True),
])
wall_13_placement = place(storey_placement, origin())
element("IfcWall", 35, at=wall_13_placement, inside=storey, Name="B5_Walls_B5_013", context=model_context, shape_type="Tessellation", body=[
    triangles([(16226.2, 23019.0, 0.0), (16226.2, 23222.2, 0.0), (16226.2, 23222.2, 3350.0), (16226.2, 23019.0, 3350.0), (13535.2, 23019.0, 0.0), (13535.2, 23019.0, 3350.0), (13535.2, 23222.2, 0.0), (13535.2, 23222.2, 3350.0)], [[1, 2, 3], [1, 3, 4], [5, 1, 4], [5, 4, 6], [7, 5, 6], [7, 6, 8], [2, 7, 8], [2, 8, 3], [7, 2, 1], [7, 1, 5], [3, 8, 4], [4, 8, 6]], closed=True),
])
wall_14_placement = place(storey_placement, origin())
element("IfcWall", 36, at=wall_14_placement, inside=storey, Name="B5_Walls_B5_014", context=model_context, shape_type="Tessellation", body=[
    triangles([(13535.2, 23222.2, 0.0), (13535.2, 23666.8, 0.0), (13535.2, 23666.8, 3350.0), (13535.2, 23222.2, 3350.0), (13129.0, 23222.2, 0.0), (13129.0, 23222.2, 3350.0), (13129.0, 23666.8, 0.0), (13129.0, 23666.8, 3350.0)], [[1, 2, 3], [1, 3, 4], [5, 1, 4], [5, 4, 6], [7, 5, 6], [7, 6, 8], [2, 7, 8], [2, 8, 3], [7, 2, 1], [7, 1, 5], [3, 8, 4], [4, 8, 6]], closed=True),
])
wall_15_placement = place(storey_placement, origin())
element("IfcWall", 37, at=wall_15_placement, inside=storey, Name="B5_Walls_B5_016", context=model_context, shape_type="Tessellation", body=[
    triangles([(13535.2, 25025.8, 0.0), (13129.0, 25025.8, 0.0), (13129.0, 25025.8, 3350.0), (13535.2, 25025.8, 3350.0), (13535.2, 24568.5, 0.0), (13535.2, 24568.5, 3350.0), (13129.0, 24568.5, 0.0), (13129.0, 24568.5, 3350.0)], [[1, 2, 3], [1, 3, 4], [5, 1, 4], [5, 4, 6], [7, 5, 6], [7, 6, 8], [2, 7, 8], [2, 8, 3], [2, 1, 5], [2, 5, 7], [4, 3, 6], [6, 3, 8]], closed=True),
])
wall_16_placement = place(storey_placement, origin())
element("IfcWall", 38, at=wall_16_placement, inside=storey, Name="B5_Walls_B5_017", context=model_context, shape_type="Tessellation", body=[
    triangles([(13535.2, 25025.8, 0.0), (16226.2, 25025.8, 0.0), (16226.2, 25025.8, 3350.0), (13535.2, 25025.8, 3350.0), (13535.2, 25419.5, 0.0), (13535.2, 25419.5, 3350.0), (16226.2, 25419.5, 0.0), (16226.2, 25419.5, 3350.0)], [[1, 2, 3], [1, 3, 4], [5, 1, 4], [5, 4, 6], [7, 5, 6], [7, 6, 8], [2, 7, 8], [2, 8, 3], [1, 7, 2], [5, 7, 1], [8, 4, 3], [8, 6, 4]], closed=True),
])
wall_17_placement = place(storey_placement, origin())
element("IfcWall", 39, at=wall_17_placement, inside=storey, Name="B5_Walls_B5_021", context=model_context, shape_type="Tessellation", body=[
    triangles([(19577.2, 19449.9, 0.0), (19374.1, 19449.9, 0.0), (19374.1, 19449.9, 3350.0), (19577.2, 19449.9, 3350.0), (19577.2, 19246.7, 0.0), (19577.2, 19246.7, 3350.0), (19374.1, 19246.7, 0.0), (19374.1, 19246.7, 3350.0)], [[1, 2, 3], [1, 3, 4], [5, 1, 4], [5, 4, 6], [7, 5, 6], [7, 6, 8], [2, 7, 8], [2, 8, 3], [2, 1, 5], [2, 5, 7], [4, 3, 6], [6, 3, 8]], closed=True),
])
wall_18_placement = place(storey_placement, origin())
element("IfcWall", 40, at=wall_18_placement, inside=storey, Name="B5_Walls_B5_026", context=model_context, shape_type="Tessellation", body=[
    triangles([(19374.1, 19449.9, 0.0), (19374.1, 22574.4, 0.0), (19374.1, 22574.4, 3350.0), (19374.1, 19449.9, 3350.0), (19183.7, 19449.9, 0.0), (19183.7, 19449.9, 3350.0), (19183.7, 22574.4, 0.0), (19183.7, 22574.4, 3350.0)], [[1, 2, 3], [1, 3, 4], [5, 1, 4], [5, 4, 6], [7, 5, 6], [7, 6, 8], [2, 7, 8], [2, 8, 3], [2, 1, 5], [7, 2, 5], [4, 3, 6], [3, 8, 6]], closed=True),
])
wall_19_placement = place(storey_placement, origin())
element("IfcWall", 41, at=wall_19_placement, inside=storey, Name="B5_Walls_B5_038", context=model_context, shape_type="Tessellation", body=[
    triangles([(31623.1, 16922.4, 0.0), (31623.1, 17316.1, 0.0), (31623.1, 17316.1, 3350.0), (31623.1, 16922.4, 3350.0), (30023.7, 16922.4, 0.0), (30023.7, 16922.4, 3350.0), (30023.7, 17316.1, 0.0), (30023.7, 17316.1, 3350.0)], [[1, 2, 3], [1, 3, 4], [5, 1, 4], [5, 4, 6], [7, 5, 6], [7, 6, 8], [2, 7, 8], [2, 8, 3], [7, 2, 1], [7, 1, 5], [3, 8, 4], [4, 8, 6]], closed=True),
])

save(model, "model.ifc")
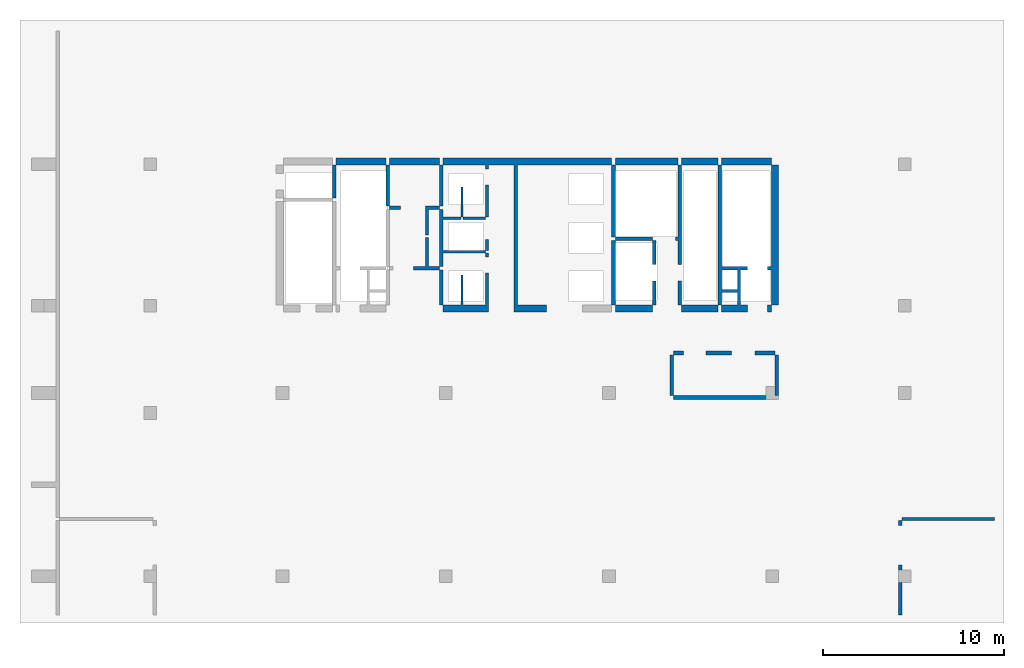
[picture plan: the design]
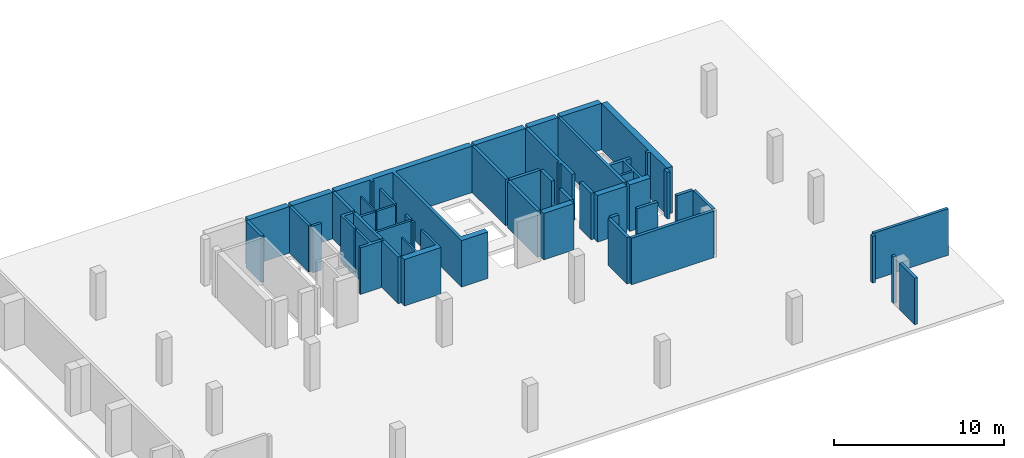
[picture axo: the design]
# One storey, part 2 of 2: 42 walls.
"""IFC4 building model written with IfcOpenShell, lengths in millimetres."""

from ifc_helpers import new_model, si_unit, frame, origin, place, context, project, spatial, triangles, element, save


model = new_model("IFC4")

# Units and contexts
model_context = context("Model", 3, precision=0.001, world=origin())
ifc_project = project(units=[si_unit("LENGTHUNIT", "METRE", prefix="MILLI"), si_unit("AREAUNIT", "SQUARE_METRE"), si_unit("VOLUMEUNIT", "CUBIC_METRE")], contexts=[model_context])

# Site, building, storey
site_placement = place(None, origin())
site = spatial("IfcSite", under=ifc_project, at=site_placement, CompositionType="ELEMENT")
building_placement = place(site_placement, origin())
building = spatial("IfcBuilding", under=site, at=building_placement, CompositionType="ELEMENT")
storey_placement = place(building_placement, frame((0.0, 0.0, -19800.0)))
storey = spatial("IfcBuildingStorey", under=building, at=storey_placement, Name="B5", CompositionType="ELEMENT", Elevation=-19800.0)

# Walls
wall_1_placement = place(storey_placement, origin())
element("IfcWall", 1, at=wall_1_placement, inside=storey, Name="B5_Walls_B5_015", context=model_context, shape_type="Tessellation", body=[
    triangles([(16429.3, 23222.2, 0.0), (16429.3, 25025.8, 0.0), (16429.3, 25025.8, 3350.0), (16429.3, 23222.2, 3350.0), (16226.2, 23222.2, 0.0), (16226.2, 23222.2, 3350.0), (16226.2, 25025.8, 0.0), (16226.2, 25025.8, 3350.0)], [[1, 2, 3], [1, 3, 4], [5, 1, 4], [5, 4, 6], [7, 5, 6], [7, 6, 8], [2, 7, 8], [2, 8, 3], [7, 2, 1], [7, 1, 5], [3, 8, 4], [4, 8, 6]], closed=True),
])
wall_2_placement = place(storey_placement, origin())
element("IfcWall", 2, at=wall_2_placement, inside=storey, Name="B5_Walls_B5_018", context=model_context, shape_type="Tessellation", body=[
    triangles([(19183.7, 25419.5, 0.0), (16429.3, 25419.5, 0.0), (16429.3, 25419.5, 3350.0), (19183.7, 25419.5, 3350.0), (19183.7, 25025.8, 0.0), (19183.7, 25025.8, 3350.0), (16429.3, 25025.8, 0.0), (16429.3, 25025.8, 3350.0)], [[1, 2, 3], [1, 3, 4], [5, 1, 4], [5, 4, 6], [7, 5, 6], [7, 6, 8], [2, 7, 8], [2, 8, 3], [2, 1, 5], [2, 5, 7], [4, 3, 6], [6, 3, 8]], closed=True),
])
wall_3_placement = place(storey_placement, origin())
element("IfcWall", 3, at=wall_3_placement, inside=storey, Name="B5_Walls_B5_019", context=model_context, shape_type="Tessellation", body=[
    triangles([(23423.2, 18967.3, 0.0), (23321.7, 18967.3, 0.0), (23321.7, 18967.3, 3350.0), (23423.2, 18967.3, 3350.0), (23423.2, 18965.0, 0.0), (23423.2, 18965.0, 3350.0), (23425.0, 18965.0, 0.0), (23425.0, 18965.0, 3350.0), (23425.0, 17316.1, 3350.0), (23425.0, 17316.1, 0.0), (24679.9, 17316.1, 0.0), (24679.9, 17316.1, 3350.0), (24679.9, 19068.9, 0.0), (24679.9, 19068.9, 3350.0), (24680.0, 19068.9, 3350.0), (24680.0, 19068.9, 0.0), (24680.0, 19070.0, 0.0), (24680.0, 19070.0, 3350.0), (24830.0, 19070.0, 0.0), (24830.0, 19070.0, 3350.0), (24830.0, 19068.9, 0.0), (24830.0, 19068.9, 3350.0), (24832.2, 19068.9, 3350.0), (24832.2, 19068.9, 0.0), (24832.2, 17316.1, 0.0), (24832.2, 17316.1, 3350.0), (24832.2, 16922.4, 0.0), (24832.2, 16922.4, 3350.0), (22331.6, 16922.4, 0.0), (22331.6, 16922.4, 3350.0), (22331.6, 17316.1, 0.0), (22331.6, 17316.1, 3350.0), (23320.0, 17316.1, 0.0), (23320.0, 17316.1, 3350.0), (23320.0, 18965.0, 3350.0), (23320.0, 18965.0, 0.0), (23321.7, 18965.0, 0.0), (23321.7, 18965.0, 3350.0)], [[1, 2, 3], [1, 3, 4], [5, 1, 4], [5, 4, 6], [7, 5, 6], [7, 6, 8], [7, 8, 9], [10, 7, 9], [11, 10, 9], [11, 9, 12], [13, 11, 12], [13, 12, 14], [13, 14, 15], [16, 13, 15], [17, 16, 15], [17, 15, 18], [19, 17, 18], [19, 18, 20], [21, 19, 20], [21, 20, 22], [21, 22, 23], [24, 21, 23], [25, 24, 23], [25, 23, 26], [27, 25, 26], [27, 26, 28], [29, 27, 28], [29, 28, 30], [31, 29, 30], [31, 30, 32], [33, 31, 32], [33, 32, 34], [33, 34, 35], [36, 33, 35], [37, 36, 35], [37, 35, 38], [2, 37, 38], [2, 38, 3], [11, 25, 27], [10, 11, 27], [21, 24, 25], [21, 25, 11], [16, 19, 21], [16, 21, 11], [13, 16, 11], [17, 19, 16], [29, 10, 27], [29, 33, 10], [31, 33, 29], [5, 7, 10], [5, 10, 33], [37, 1, 5], [37, 5, 33], [36, 37, 33], [2, 1, 37], [26, 12, 28], [12, 9, 28], [23, 22, 26], [26, 22, 12], [20, 15, 22], [22, 15, 12], [15, 14, 12], [20, 18, 15], [9, 30, 28], [34, 30, 9], [34, 32, 30], [8, 6, 9], [9, 6, 34], [4, 38, 6], [6, 38, 34], [38, 35, 34], [4, 3, 38]], closed=True),
])
wall_4_placement = place(storey_placement, origin())
element("IfcWall", 4, at=wall_4_placement, inside=storey, Name="B5_Walls_B5_020", context=model_context, shape_type="Tessellation", body=[
    triangles([(22331.6, 19246.7, 0.0), (22331.6, 19246.7, 3350.0), (22331.6, 17316.1, 3350.0), (22331.6, 17316.1, 0.0), (22128.5, 17316.1, 0.0), (22128.5, 17316.1, 3350.0), (22128.5, 19246.7, 3350.0), (22128.5, 19246.7, 0.0)], [[1, 2, 3], [4, 1, 3], [5, 4, 3], [5, 3, 6], [5, 6, 7], [8, 5, 7], [1, 8, 7], [1, 7, 2], [8, 1, 4], [8, 4, 5], [2, 7, 3], [3, 7, 6]], closed=True),
])
wall_5_placement = place(storey_placement, origin())
element("IfcWall", 5, at=wall_5_placement, inside=storey, Name="B5_Walls_B5_022", context=model_context, shape_type="Tessellation", body=[
    triangles([(21366.9, 21024.9, 0.0), (21366.9, 19449.9, 0.0), (21366.9, 19449.9, 3350.0), (21366.9, 21024.9, 3350.0), (21519.3, 21024.9, 3350.0), (21519.3, 21024.9, 0.0), (21519.3, 19449.9, 0.0), (21519.3, 19449.9, 3350.0), (22128.5, 19449.9, 0.0), (22128.5, 19449.9, 3350.0), (22128.5, 19246.7, 0.0), (22128.5, 19246.7, 3350.0), (20694.2, 19246.7, 0.0), (20694.2, 19246.7, 3350.0), (20694.2, 19449.9, 0.0), (20694.2, 19449.9, 3350.0)], [[1, 2, 3], [1, 3, 4], [1, 4, 5], [6, 1, 5], [7, 6, 5], [7, 5, 8], [9, 7, 8], [9, 8, 10], [11, 9, 10], [11, 10, 12], [13, 11, 12], [13, 12, 14], [15, 13, 14], [15, 14, 16], [2, 15, 16], [2, 16, 3], [7, 9, 11], [2, 7, 11], [13, 2, 11], [15, 2, 13], [1, 6, 7], [1, 7, 2], [10, 8, 12], [8, 3, 12], [3, 14, 12], [3, 16, 14], [5, 4, 8], [8, 4, 3]], closed=True),
])
wall_6_placement = place(storey_placement, origin())
element("IfcWall", 6, at=wall_6_placement, inside=storey, Name="B5_Walls_B5_023", context=model_context, shape_type="Tessellation", body=[
    triangles([(24832.2, 19970.7, 0.0), (24832.2, 20173.9, 0.0), (24832.2, 20173.9, 3350.0), (24832.2, 19970.7, 3350.0), (24679.9, 19970.7, 0.0), (24679.9, 19970.7, 3350.0), (24679.9, 20173.9, 0.0), (24679.9, 20173.9, 3350.0)], [[1, 2, 3], [1, 3, 4], [5, 1, 4], [5, 4, 6], [7, 5, 6], [7, 6, 8], [2, 7, 8], [2, 8, 3], [7, 2, 1], [7, 1, 5], [3, 8, 4], [4, 8, 6]], closed=True),
])
wall_7_placement = place(storey_placement, origin())
element("IfcWall", 7, at=wall_7_placement, inside=storey, Name="B5_Walls_B5_024", context=model_context, shape_type="Tessellation", body=[
    triangles([(22128.5, 22574.4, 0.0), (22128.5, 19449.9, 0.0), (22128.5, 19449.9, 3350.0), (22128.5, 22574.4, 3350.0), (22331.6, 22574.4, 0.0), (22331.6, 22574.4, 3350.0), (22331.6, 22168.0, 0.0), (22331.6, 22168.0, 3350.0), (23321.7, 22168.0, 3350.0), (23321.7, 22168.0, 0.0), (23321.7, 22015.6, 0.0), (23321.7, 22015.6, 3350.0), (22331.6, 22015.6, 3350.0), (22331.6, 22015.6, 0.0), (22331.6, 20326.3, 0.0), (22331.6, 20326.3, 3350.0), (24679.9, 20326.3, 0.0), (24679.9, 20326.3, 3350.0), (24679.9, 20173.9, 3350.0), (24679.9, 20173.9, 0.0), (22331.6, 20173.9, 0.0), (22331.6, 20173.9, 3350.0), (22331.6, 19449.9, 3350.0), (22331.6, 19449.9, 0.0)], [[1, 2, 3], [1, 3, 4], [5, 1, 4], [5, 4, 6], [7, 5, 6], [7, 6, 8], [7, 8, 9], [10, 7, 9], [11, 10, 9], [11, 9, 12], [11, 12, 13], [14, 11, 13], [15, 14, 13], [15, 13, 16], [17, 15, 16], [17, 16, 18], [17, 18, 19], [20, 17, 19], [21, 20, 19], [21, 19, 22], [21, 22, 23], [24, 21, 23], [2, 24, 23], [2, 23, 3], [21, 24, 2], [15, 17, 20], [15, 20, 21], [15, 21, 2], [14, 10, 11], [7, 10, 14], [1, 5, 7], [1, 14, 15], [1, 7, 14], [2, 1, 15], [23, 22, 3], [18, 16, 19], [19, 16, 22], [22, 16, 3], [9, 13, 12], [9, 8, 13], [6, 4, 8], [13, 4, 16], [8, 4, 13], [4, 3, 16]], closed=True),
])
wall_8_placement = place(storey_placement, origin())
element("IfcWall", 8, at=wall_8_placement, inside=storey, Name="B5_Walls_B5_025", context=model_context, shape_type="Tessellation", body=[
    triangles([(24679.9, 20326.3, 0.0), (24832.2, 20326.3, 0.0), (24832.2, 20326.3, 3350.0), (24679.9, 20326.3, 3350.0), (24679.9, 20923.3, 0.0), (24679.9, 20923.3, 3350.0), (24832.2, 20923.3, 0.0), (24832.2, 20923.3, 3350.0)], [[1, 2, 3], [1, 3, 4], [5, 1, 4], [5, 4, 6], [7, 5, 6], [7, 6, 8], [2, 7, 8], [2, 8, 3], [5, 2, 1], [5, 7, 2], [3, 6, 4], [8, 6, 3]], closed=True),
])
wall_9_placement = place(storey_placement, origin())
element("IfcWall", 9, at=wall_9_placement, inside=storey, Name="B5_Walls_B5_027", context=model_context, shape_type="Tessellation", body=[
    triangles([(22128.5, 22765.0, 0.0), (21366.9, 22765.0, 0.0), (21366.9, 22765.0, 3350.0), (22128.5, 22765.0, 3350.0), (22128.5, 22574.4, 0.0), (22128.5, 22574.4, 3350.0), (21519.3, 22574.4, 0.0), (21519.3, 22574.4, 3350.0), (21519.3, 21177.3, 0.0), (21519.3, 21177.3, 3350.0), (21366.9, 21177.3, 3350.0), (21366.9, 21177.3, 0.0), (21366.9, 22574.4, 0.0), (21366.9, 22574.4, 3350.0)], [[1, 2, 3], [1, 3, 4], [5, 1, 4], [5, 4, 6], [7, 5, 6], [7, 6, 8], [9, 7, 8], [9, 8, 10], [9, 10, 11], [12, 9, 11], [13, 12, 11], [13, 11, 14], [2, 13, 14], [2, 14, 3], [7, 1, 5], [13, 7, 9], [13, 9, 12], [2, 1, 7], [2, 7, 13], [4, 8, 6], [8, 14, 10], [10, 14, 11], [4, 3, 8], [8, 3, 14]], closed=True),
])
wall_10_placement = place(storey_placement, origin())
element("IfcWall", 10, at=wall_10_placement, inside=storey, Name="B5_Walls_B5_028", context=model_context, shape_type="Tessellation", body=[
    triangles([(23423.2, 22168.0, 0.0), (23423.2, 22168.0, 3350.0), (24679.9, 22168.0, 3350.0), (24679.9, 22168.0, 0.0), (24679.9, 22015.6, 0.0), (24679.9, 22015.6, 3350.0), (23423.2, 22015.6, 3350.0), (23423.2, 22015.6, 0.0)], [[1, 2, 3], [4, 1, 3], [5, 4, 3], [5, 3, 6], [5, 6, 7], [8, 5, 7], [1, 8, 7], [1, 7, 2], [1, 4, 5], [1, 5, 8], [3, 2, 6], [6, 2, 7]], closed=True),
])
wall_11_placement = place(storey_placement, origin())
element("IfcWall", 11, at=wall_11_placement, inside=storey, Name="B5_Walls_B5_029", context=model_context, shape_type="Tessellation", body=[
    triangles([(19970.7, 22574.4, 0.0), (19970.7, 22765.0, 0.0), (19970.7, 22765.0, 3350.0), (19970.7, 22574.4, 3350.0), (19374.1, 22574.4, 0.0), (19374.1, 22574.4, 3350.0), (19374.1, 22765.0, 0.0), (19374.1, 22765.0, 3350.0)], [[1, 2, 3], [1, 3, 4], [5, 1, 4], [5, 4, 6], [7, 5, 6], [7, 6, 8], [2, 7, 8], [2, 8, 3], [7, 2, 1], [7, 1, 5], [3, 8, 4], [4, 8, 6]], closed=True),
])
wall_12_placement = place(storey_placement, origin())
element("IfcWall", 12, at=wall_12_placement, inside=storey, Name="B5_Walls_B5_030", context=model_context, shape_type="Tessellation", body=[
    triangles([(23423.2, 23819.2, 0.0), (23423.2, 23819.2, 3350.0), (23423.2, 22168.0, 3350.0), (23423.2, 22168.0, 0.0), (23321.7, 22168.0, 0.0), (23321.7, 22168.0, 3350.0), (23321.7, 23819.2, 3350.0), (23321.7, 23819.2, 0.0)], [[1, 2, 3], [4, 1, 3], [5, 4, 3], [5, 3, 6], [5, 6, 7], [8, 5, 7], [1, 8, 7], [1, 7, 2], [8, 1, 4], [8, 4, 5], [2, 7, 3], [3, 7, 6]], closed=True),
])
wall_13_placement = place(storey_placement, origin())
element("IfcWall", 13, at=wall_13_placement, inside=storey, Name="B5_Walls_B5_031", context=model_context, shape_type="Tessellation", body=[
    triangles([(19374.1, 22765.0, 0.0), (19374.1, 25025.8, 0.0), (19374.1, 25025.8, 3350.0), (19374.1, 22765.0, 3350.0), (19183.7, 22765.0, 0.0), (19183.7, 22765.0, 3350.0), (19183.7, 25025.8, 0.0), (19183.7, 25025.8, 3350.0)], [[1, 2, 3], [1, 3, 4], [5, 1, 4], [5, 4, 6], [7, 5, 6], [7, 6, 8], [2, 7, 8], [2, 8, 3], [7, 2, 1], [7, 1, 5], [3, 8, 4], [4, 8, 6]], closed=True),
])
wall_14_placement = place(storey_placement, origin())
element("IfcWall", 14, at=wall_14_placement, inside=storey, Name="B5_Walls_B5_032", context=model_context, shape_type="Tessellation", body=[
    triangles([(22331.6, 22765.0, 0.0), (22331.6, 25025.8, 0.0), (22331.6, 25025.8, 3350.0), (22331.6, 22765.0, 3350.0), (22128.5, 22765.0, 0.0), (22128.5, 22765.0, 3350.0), (22128.5, 25025.8, 0.0), (22128.5, 25025.8, 3350.0)], [[1, 2, 3], [1, 3, 4], [5, 1, 4], [5, 4, 6], [7, 5, 6], [7, 6, 8], [2, 7, 8], [2, 8, 3], [7, 2, 1], [7, 1, 5], [3, 8, 4], [4, 8, 6]], closed=True),
])
wall_15_placement = place(storey_placement, origin())
element("IfcWall", 15, at=wall_15_placement, inside=storey, Name="B5_Walls_B5_033", context=model_context, shape_type="Tessellation", body=[
    triangles([(22128.5, 25419.5, 0.0), (19374.1, 25419.5, 0.0), (19374.1, 25419.5, 3350.0), (22128.5, 25419.5, 3350.0), (22128.5, 25025.8, 0.0), (22128.5, 25025.8, 3350.0), (19374.1, 25025.8, 0.0), (19374.1, 25025.8, 3350.0)], [[1, 2, 3], [1, 3, 4], [5, 1, 4], [5, 4, 6], [7, 5, 6], [7, 6, 8], [2, 7, 8], [2, 8, 3], [2, 1, 5], [2, 5, 7], [4, 3, 6], [6, 3, 8]], closed=True),
])
wall_16_placement = place(storey_placement, origin())
element("IfcWall", 16, at=wall_16_placement, inside=storey, Name="B5_Walls_B5_034", context=model_context, shape_type="Tessellation", body=[
    triangles([(35024.8, 14572.6, 0.0), (34821.8, 14572.6, 0.0), (34821.8, 14572.6, 3350.0), (35024.8, 14572.6, 3350.0), (35024.8, 12324.5, 0.0), (35024.8, 12324.5, 3350.0), (34821.8, 12324.5, 0.0), (34821.8, 12324.5, 3350.0)], [[1, 2, 3], [1, 3, 4], [5, 1, 4], [5, 4, 6], [7, 5, 6], [7, 6, 8], [2, 7, 8], [2, 8, 3], [2, 1, 5], [2, 5, 7], [4, 3, 6], [6, 3, 8]], closed=True),
])
wall_17_placement = place(storey_placement, origin())
element("IfcWall", 17, at=wall_17_placement, inside=storey, Name="B5_Walls_B5_035", context=model_context, shape_type="Tessellation", body=[
    triangles([(35024.8, 14572.6, 0.0), (35024.8, 14572.6, 3350.0), (35024.8, 14775.8, 3350.0), (35024.8, 14775.8, 0.0), (35570.7, 14775.8, 0.0), (35570.7, 14775.8, 3350.0), (35570.7, 14572.6, 3350.0), (35570.7, 14572.6, 0.0)], [[1, 2, 3], [4, 1, 3], [5, 4, 3], [5, 3, 6], [5, 6, 7], [8, 5, 7], [1, 8, 7], [1, 7, 2], [4, 5, 8], [4, 8, 1], [6, 3, 7], [7, 3, 2]], closed=True),
])
wall_18_placement = place(storey_placement, origin())
element("IfcWall", 18, at=wall_18_placement, inside=storey, Name="B5_Walls_B5_036", context=model_context, shape_type="Tessellation", body=[
    triangles([(38223.5, 14775.0, 0.0), (38223.5, 14775.8, 0.0), (38223.5, 14775.8, 3350.0), (38223.5, 14775.0, 3350.0), (38225.0, 14775.0, 0.0), (38225.0, 14775.0, 3350.0), (38225.0, 14575.0, 0.0), (38225.0, 14575.0, 3350.0), (38223.5, 14575.0, 0.0), (38223.5, 14575.0, 3350.0), (38223.5, 14572.6, 0.0), (38223.5, 14572.6, 3350.0), (36814.6, 14572.6, 0.0), (36814.6, 14572.6, 3350.0), (36814.6, 14775.8, 3350.0), (36814.6, 14775.8, 0.0)], [[1, 2, 3], [1, 3, 4], [5, 1, 4], [5, 4, 6], [7, 5, 6], [7, 6, 8], [9, 7, 8], [9, 8, 10], [11, 9, 10], [11, 10, 12], [13, 11, 12], [13, 12, 14], [13, 14, 15], [16, 13, 15], [2, 16, 15], [2, 15, 3], [1, 5, 7], [1, 7, 9], [13, 9, 11], [16, 2, 1], [16, 9, 13], [16, 1, 9], [6, 4, 8], [8, 4, 10], [10, 14, 12], [3, 15, 4], [10, 15, 14], [4, 15, 10]], closed=True),
])
wall_19_placement = place(storey_placement, origin())
element("IfcWall", 19, at=wall_19_placement, inside=storey, Name="B5_Walls_B5_037", context=model_context, shape_type="Tessellation", body=[
    triangles([(24832.2, 24822.6, 0.0), (24832.2, 25025.8, 0.0), (24832.2, 25025.8, 3350.0), (24832.2, 24822.6, 3350.0), (24679.9, 24822.6, 0.0), (24679.9, 24822.6, 3350.0), (24679.9, 25025.8, 0.0), (24679.9, 25025.8, 3350.0), (22331.6, 25025.8, 0.0), (22331.6, 25025.8, 3350.0), (22331.6, 25419.5, 0.0), (22331.6, 25419.5, 3350.0), (31623.1, 25419.5, 0.0), (31623.1, 25419.5, 3350.0), (31623.1, 25025.8, 0.0), (31623.1, 25025.8, 3350.0), (26431.5, 25025.8, 3350.0), (26431.5, 25025.8, 0.0), (26431.5, 17316.1, 0.0), (26431.5, 17316.1, 3350.0), (28030.9, 17316.1, 0.0), (28030.9, 17316.1, 3350.0), (28030.9, 16922.4, 0.0), (28030.9, 16922.4, 3350.0), (28030.0, 16922.4, 0.0), (28030.0, 16922.4, 3350.0), (28030.0, 16920.0, 0.0), (28030.0, 16920.0, 3350.0), (26230.0, 16920.0, 0.0), (26230.0, 16920.0, 3350.0), (26230.0, 16922.4, 0.0), (26230.0, 16922.4, 3350.0), (26228.4, 16922.4, 3350.0), (26228.4, 16922.4, 0.0), (26228.4, 17316.1, 0.0), (26228.4, 17316.1, 3350.0), (26228.4, 25025.8, 0.0), (26228.4, 25025.8, 3350.0)], [[1, 2, 3], [1, 3, 4], [5, 1, 4], [5, 4, 6], [7, 5, 6], [7, 6, 8], [9, 7, 8], [9, 8, 10], [11, 9, 10], [11, 10, 12], [13, 11, 12], [13, 12, 14], [15, 13, 14], [15, 14, 16], [17, 15, 16], [18, 15, 17], [19, 18, 17], [19, 17, 20], [21, 19, 20], [21, 20, 22], [23, 21, 22], [23, 22, 24], [25, 23, 24], [25, 24, 26], [27, 25, 26], [27, 26, 28], [29, 27, 28], [29, 28, 30], [31, 29, 30], [31, 30, 32], [31, 32, 33], [34, 31, 33], [35, 34, 33], [35, 33, 36], [37, 35, 36], [37, 36, 38], [2, 37, 38], [2, 38, 3], [21, 23, 25], [19, 25, 27], [19, 27, 29], [19, 29, 31], [19, 21, 25], [35, 31, 34], [35, 19, 31], [18, 13, 15], [37, 18, 19], [37, 19, 35], [2, 1, 5], [7, 2, 5], [11, 7, 9], [11, 13, 18], [11, 18, 37], [11, 37, 2], [11, 2, 7], [24, 22, 26], [26, 20, 28], [28, 20, 30], [30, 20, 32], [22, 20, 26], [32, 36, 33], [20, 36, 32], [14, 17, 16], [17, 38, 20], [20, 38, 36], [4, 3, 6], [3, 8, 6], [8, 12, 10], [14, 12, 17], [17, 12, 38], [38, 12, 3], [3, 12, 8]], closed=True),
])
wall_20_placement = place(storey_placement, origin())
element("IfcWall", 20, at=wall_20_placement, inside=storey, Name="B5_Walls_B5_039", context=model_context, shape_type="Tessellation", body=[
    triangles([(33869.8, 16922.4, 0.0), (33869.8, 17316.1, 0.0), (33869.8, 17316.1, 3350.0), (33869.8, 16922.4, 3350.0), (31826.2, 16922.4, 0.0), (31826.2, 16922.4, 3350.0), (31826.2, 17316.1, 0.0), (31826.2, 17316.1, 3350.0)], [[1, 2, 3], [1, 3, 4], [5, 1, 4], [5, 4, 6], [7, 5, 6], [7, 6, 8], [2, 7, 8], [2, 8, 3], [7, 2, 1], [7, 1, 5], [3, 8, 4], [4, 8, 6]], closed=True),
])
wall_21_placement = place(storey_placement, origin())
element("IfcWall", 21, at=wall_21_placement, inside=storey, Name="B5_Walls_B5_040", context=model_context, shape_type="Tessellation", body=[
    triangles([(37474.6, 16922.4, 0.0), (37474.6, 17316.1, 0.0), (37474.6, 17316.1, 3350.0), (37474.6, 16922.4, 3350.0), (35469.1, 16922.4, 0.0), (35469.1, 16922.4, 3350.0), (35469.1, 17316.1, 0.0), (35469.1, 17316.1, 3350.0)], [[1, 2, 3], [1, 3, 4], [5, 1, 4], [5, 4, 6], [7, 5, 6], [7, 6, 8], [2, 7, 8], [2, 8, 3], [7, 2, 1], [7, 1, 5], [3, 8, 4], [4, 8, 6]], closed=True),
])
wall_22_placement = place(storey_placement, origin())
element("IfcWall", 22, at=wall_22_placement, inside=storey, Name="B5_Walls_B5_041", context=model_context, shape_type="Tessellation", body=[
    triangles([(34072.9, 17316.1, 0.0), (34072.9, 18649.7, 0.0), (34072.9, 18649.7, 3350.0), (34072.9, 17316.1, 3350.0), (33869.8, 17316.1, 0.0), (33869.8, 17316.1, 3350.0), (33869.8, 18649.7, 0.0), (33869.8, 18649.7, 3350.0)], [[1, 2, 3], [1, 3, 4], [5, 1, 4], [5, 4, 6], [7, 5, 6], [7, 6, 8], [2, 7, 8], [2, 8, 3], [7, 2, 1], [7, 1, 5], [3, 8, 4], [4, 8, 6]], closed=True),
])
wall_23_placement = place(storey_placement, origin())
element("IfcWall", 23, at=wall_23_placement, inside=storey, Name="B5_Walls_B5_042", context=model_context, shape_type="Tessellation", body=[
    triangles([(35469.1, 17316.1, 0.0), (35469.1, 18649.7, 0.0), (35469.1, 18649.7, 3350.0), (35469.1, 17316.1, 3350.0), (35266.0, 17316.1, 0.0), (35266.0, 17316.1, 3350.0), (35266.0, 18649.7, 0.0), (35266.0, 18649.7, 3350.0)], [[1, 2, 3], [1, 3, 4], [5, 1, 4], [5, 4, 6], [7, 5, 6], [7, 6, 8], [2, 7, 8], [2, 8, 3], [7, 2, 1], [7, 1, 5], [3, 8, 4], [4, 8, 6]], closed=True),
])
wall_24_placement = place(storey_placement, origin())
element("IfcWall", 24, at=wall_24_placement, inside=storey, Name="B5_Walls_B5_043", context=model_context, shape_type="Tessellation", body=[
    triangles([(31826.2, 17316.1, 3350.0), (31826.2, 20872.5, 0.0), (31826.2, 20872.5, 3350.0), (31826.2, 17316.1, 0.0), (31623.1, 17316.1, 0.0), (31623.1, 17316.1, 3350.0), (31623.1, 20872.5, 3350.0), (31623.1, 20872.5, 0.0)], [[1, 2, 3], [4, 2, 1], [5, 4, 1], [5, 1, 6], [7, 5, 6], [8, 5, 7], [2, 8, 7], [2, 7, 3], [8, 2, 4], [8, 4, 5], [3, 7, 1], [1, 7, 6]], closed=True),
])
wall_25_placement = place(storey_placement, origin())
element("IfcWall", 25, at=wall_25_placement, inside=storey, Name="B5_Walls_B5_044", context=model_context, shape_type="Tessellation", body=[
    triangles([(34072.9, 19551.5, 0.0), (34072.9, 20872.5, 0.0), (34072.9, 20872.5, 3350.0), (34072.9, 19551.5, 3350.0), (33869.8, 19551.5, 0.0), (33869.8, 19551.5, 3350.0), (33869.8, 20872.5, 0.0), (33869.8, 20872.5, 3350.0)], [[1, 2, 3], [1, 3, 4], [5, 1, 4], [5, 4, 6], [7, 5, 6], [7, 6, 8], [2, 7, 8], [2, 8, 3], [7, 2, 1], [7, 1, 5], [3, 8, 4], [4, 8, 6]], closed=True),
])
wall_26_placement = place(storey_placement, origin())
element("IfcWall", 26, at=wall_26_placement, inside=storey, Name="B5_Walls_B5_045", context=model_context, shape_type="Tessellation", body=[
    triangles([(35469.1, 21075.7, 3350.0), (35469.1, 25025.8, 0.0), (35469.1, 25025.8, 3350.0), (35469.1, 21075.7, 0.0), (35469.1, 20872.5, 0.0), (35469.1, 20872.5, 3350.0), (35469.1, 19551.5, 0.0), (35469.1, 19551.5, 3350.0), (35266.0, 19551.5, 0.0), (35266.0, 19551.5, 3350.0), (35266.0, 20872.5, 0.0), (35266.0, 20872.5, 3350.0), (35126.4, 20872.5, 0.0), (35126.4, 20872.5, 3350.0), (35126.4, 21075.7, 0.0), (35126.4, 21075.7, 3350.0), (35266.0, 21075.7, 0.0), (35266.0, 21075.7, 3350.0), (35266.0, 25025.8, 3350.0), (35266.0, 25025.8, 0.0)], [[1, 2, 3], [4, 2, 1], [5, 4, 1], [5, 1, 6], [7, 5, 6], [7, 6, 8], [9, 7, 8], [9, 8, 10], [11, 9, 10], [11, 10, 12], [13, 11, 12], [13, 12, 14], [15, 13, 14], [15, 14, 16], [17, 15, 16], [17, 16, 18], [19, 17, 18], [20, 17, 19], [2, 20, 19], [2, 19, 3], [11, 5, 7], [11, 7, 9], [4, 5, 11], [17, 4, 11], [15, 11, 13], [15, 17, 11], [20, 2, 4], [20, 4, 17], [6, 12, 8], [8, 12, 10], [6, 1, 12], [1, 18, 12], [12, 16, 14], [18, 16, 12], [3, 19, 1], [1, 19, 18]], closed=True),
])
wall_27_placement = place(storey_placement, origin())
element("IfcWall", 27, at=wall_27_placement, inside=storey, Name="B5_Walls_B5_046", context=model_context, shape_type="Tessellation", body=[
    triangles([(33869.8, 20872.5, 0.0), (33869.8, 21075.7, 0.0), (33869.8, 21075.7, 3350.0), (33869.8, 20872.5, 3350.0), (31826.2, 20872.5, 0.0), (31826.2, 20872.5, 3350.0), (31826.2, 21075.7, 0.0), (31826.2, 21075.7, 3350.0)], [[1, 2, 3], [1, 3, 4], [5, 1, 4], [5, 4, 6], [7, 5, 6], [7, 6, 8], [2, 7, 8], [2, 8, 3], [7, 2, 1], [7, 1, 5], [3, 8, 4], [4, 8, 6]], closed=True),
])
wall_28_placement = place(storey_placement, origin())
element("IfcWall", 28, at=wall_28_placement, inside=storey, Name="B5_Walls_B5_047", context=model_context, shape_type="Tessellation", body=[
    triangles([(24832.2, 22168.0, 0.0), (24832.2, 23920.8, 0.0), (24832.2, 23920.8, 3350.0), (24832.2, 22168.0, 3350.0), (24679.9, 22168.0, 0.0), (24679.9, 22168.0, 3350.0), (24679.9, 23920.8, 0.0), (24679.9, 23920.8, 3350.0)], [[1, 2, 3], [1, 3, 4], [5, 1, 4], [5, 4, 6], [7, 5, 6], [7, 6, 8], [2, 7, 8], [2, 8, 3], [2, 1, 5], [7, 2, 5], [4, 3, 6], [3, 8, 6]], closed=True),
])
wall_29_placement = place(storey_placement, origin())
element("IfcWall", 29, at=wall_29_placement, inside=storey, Name="B5_Walls_B5_048", context=model_context, shape_type="Tessellation", body=[
    triangles([(31826.2, 21075.7, 3350.0), (31826.2, 25025.8, 0.0), (31826.2, 25025.8, 3350.0), (31826.2, 21075.7, 0.0), (31623.1, 21075.7, 0.0), (31623.1, 21075.7, 3350.0), (31623.1, 25025.8, 3350.0), (31623.1, 25025.8, 0.0)], [[1, 2, 3], [4, 2, 1], [5, 4, 1], [5, 1, 6], [7, 5, 6], [8, 5, 7], [2, 8, 7], [2, 7, 3], [2, 4, 5], [8, 2, 5], [1, 3, 6], [3, 7, 6]], closed=True),
])
wall_30_placement = place(storey_placement, origin())
element("IfcWall", 30, at=wall_30_placement, inside=storey, Name="B5_Walls_B5_049", context=model_context, shape_type="Tessellation", body=[
    triangles([(35266.0, 25025.8, 0.0), (35266.0, 25419.5, 0.0), (35266.0, 25419.5, 3350.0), (35266.0, 25025.8, 3350.0), (31826.2, 25025.8, 3350.0), (31826.2, 25025.8, 0.0), (31826.2, 25419.5, 0.0), (31826.2, 25419.5, 3350.0)], [[1, 2, 3], [1, 3, 4], [5, 1, 4], [6, 1, 5], [7, 6, 5], [7, 5, 8], [3, 7, 8], [2, 7, 3], [7, 2, 1], [7, 1, 6], [3, 8, 4], [4, 8, 5]], closed=True),
])
wall_31_placement = place(storey_placement, origin())
element("IfcWall", 31, at=wall_31_placement, inside=storey, Name="B5_Walls_B5_050", context=model_context, shape_type="Tessellation", body=[
    triangles([(37474.6, 25419.5, 0.0), (35469.1, 25419.5, 0.0), (35469.1, 25419.5, 3350.0), (37474.6, 25419.5, 3350.0), (37474.6, 25025.8, 0.0), (37474.6, 25025.8, 3350.0), (35469.1, 25025.8, 0.0), (35469.1, 25025.8, 3350.0)], [[1, 2, 3], [1, 3, 4], [5, 1, 4], [5, 4, 6], [7, 5, 6], [7, 6, 8], [2, 7, 8], [2, 8, 3], [2, 1, 5], [2, 5, 7], [4, 3, 6], [6, 3, 8]], closed=True),
])
wall_32_placement = place(storey_placement, origin())
element("IfcWall", 32, at=wall_32_placement, inside=storey, Name="B5_Walls_B5_051", context=model_context, shape_type="Tessellation", body=[
    triangles([(47616.5, 220.2, 0.0), (47616.5, 2023.7, 0.0), (47616.5, 2023.7, 3350.0), (47616.5, 220.2, 3350.0), (47413.4, 220.2, 0.0), (47413.4, 220.2, 3350.0), (47413.4, 2023.7, 0.0), (47413.4, 2023.7, 3350.0)], [[1, 2, 3], [1, 3, 4], [5, 1, 4], [5, 4, 6], [7, 5, 6], [7, 6, 8], [2, 7, 8], [2, 8, 3], [7, 2, 1], [7, 1, 5], [3, 8, 4], [4, 8, 6]], closed=True),
])
wall_33_placement = place(storey_placement, origin())
element("IfcWall", 33, at=wall_33_placement, inside=storey, Name="B5_Walls_B5_052", context=model_context, shape_type="Tessellation", body=[
    triangles([(47616.5, 2722.3, 0.0), (47616.5, 2976.3, 0.0), (47616.5, 2976.3, 3350.0), (47616.5, 2722.3, 3350.0), (47413.4, 2722.3, 0.0), (47413.4, 2722.3, 3350.0), (47413.4, 2976.3, 0.0), (47413.4, 2976.3, 3350.0)], [[1, 2, 3], [1, 3, 4], [5, 1, 4], [5, 4, 6], [7, 5, 6], [7, 6, 8], [2, 7, 8], [2, 8, 3], [2, 1, 5], [7, 2, 5], [4, 3, 6], [3, 8, 6]], closed=True),
])
wall_34_placement = place(storey_placement, origin())
element("IfcWall", 34, at=wall_34_placement, inside=storey, Name="B5_Walls_B5_053", context=model_context, shape_type="Tessellation", body=[
    triangles([(47413.4, 5427.7, 0.0), (47413.4, 5173.7, 0.0), (47413.4, 5173.7, 3350.0), (47413.4, 5427.7, 3350.0), (47616.5, 5427.7, 0.0), (47616.5, 5427.7, 3350.0), (47616.5, 5173.7, 0.0), (47616.5, 5173.7, 3350.0)], [[1, 2, 3], [1, 3, 4], [5, 1, 4], [5, 4, 6], [7, 5, 6], [7, 6, 8], [2, 7, 8], [2, 8, 3], [5, 7, 2], [1, 5, 2], [8, 6, 3], [6, 4, 3]], closed=True),
])
wall_35_placement = place(storey_placement, origin())
element("IfcWall", 35, at=wall_35_placement, inside=storey, Name="B5_Walls_B5_054", context=model_context, shape_type="Tessellation", body=[
    triangles([(52706.5, 5427.7, 0.0), (52706.5, 5618.2, 0.0), (52706.5, 5618.2, 3350.0), (52706.5, 5427.7, 3350.0), (47616.5, 5427.7, 0.0), (47616.5, 5427.7, 3350.0), (47616.5, 5618.2, 0.0), (47616.5, 5618.2, 3350.0)], [[1, 2, 3], [1, 3, 4], [5, 1, 4], [5, 4, 6], [7, 5, 6], [7, 6, 8], [2, 7, 8], [2, 8, 3], [7, 2, 1], [7, 1, 5], [3, 8, 4], [4, 8, 6]], closed=True),
])
wall_36_placement = place(storey_placement, origin())
element("IfcWall", 36, at=wall_36_placement, inside=storey, Name="B5_Walls_B5_055", context=model_context, shape_type="Tessellation", body=[
    triangles([(40622.6, 12121.3, 0.0), (40622.6, 12324.5, 0.0), (40622.6, 12324.5, 3350.0), (40622.6, 12121.3, 3350.0), (35024.8, 12121.3, 0.0), (35024.8, 12121.3, 3350.0), (35024.8, 12324.5, 0.0), (35024.8, 12324.5, 3350.0)], [[1, 2, 3], [1, 3, 4], [5, 1, 4], [5, 4, 6], [7, 5, 6], [7, 6, 8], [2, 7, 8], [2, 8, 3], [7, 2, 1], [7, 1, 5], [3, 8, 4], [4, 8, 6]], closed=True),
])
wall_37_placement = place(storey_placement, origin())
element("IfcWall", 37, at=wall_37_placement, inside=storey, Name="B5_Walls_B5_056", context=model_context, shape_type="Tessellation", body=[
    triangles([(40622.6, 12324.5, 0.0), (40813.0, 12324.5, 0.0), (40813.0, 12324.5, 3350.0), (40622.6, 12324.5, 3350.0), (40622.6, 14572.6, 0.0), (40622.6, 14572.6, 3350.0), (40813.0, 14572.6, 0.0), (40813.0, 14572.6, 3350.0)], [[1, 2, 3], [1, 3, 4], [5, 1, 4], [5, 4, 6], [7, 5, 6], [7, 6, 8], [2, 7, 8], [2, 8, 3], [7, 2, 1], [5, 7, 1], [3, 8, 4], [8, 6, 4]], closed=True),
])
wall_38_placement = place(storey_placement, origin())
element("IfcWall", 38, at=wall_38_placement, inside=storey, Name="B5_Walls_B5_057", context=model_context, shape_type="Tessellation", body=[
    triangles([(40622.6, 14775.8, 0.0), (40622.6, 14775.8, 3350.0), (40622.6, 14572.6, 3350.0), (40622.6, 14572.6, 0.0), (39518.2, 14572.6, 3350.0), (39518.2, 14572.6, 0.0), (39518.2, 14775.8, 3350.0), (39518.2, 14775.8, 0.0)], [[1, 2, 3], [4, 1, 3], [4, 3, 5], [6, 4, 5], [6, 5, 7], [8, 6, 7], [8, 7, 2], [1, 8, 2], [8, 1, 4], [8, 4, 6], [2, 7, 3], [3, 7, 5]], closed=True),
])
wall_39_placement = place(storey_placement, origin())
element("IfcWall", 39, at=wall_39_placement, inside=storey, Name="B5_Walls_B5_058", context=model_context, shape_type="Tessellation", body=[
    triangles([(37665.0, 17316.1, 0.0), (37665.0, 16922.4, 0.0), (37665.0, 16922.4, 3350.0), (37665.0, 17316.1, 3350.0), (39099.4, 16922.4, 0.0), (39099.4, 16922.4, 3350.0), (39099.4, 17316.1, 0.0), (39099.4, 17316.1, 3350.0), (38720.0, 17316.1, 0.0), (38720.0, 17316.1, 3350.0), (38720.0, 19245.0, 0.0), (38720.0, 19245.0, 3350.0), (39100.0, 19245.0, 0.0), (39100.0, 19245.0, 3350.0), (39100.0, 19450.0, 0.0), (39100.0, 19450.0, 3350.0), (37665.0, 19450.0, 0.0), (37665.0, 19450.0, 3350.0), (37665.0, 25025.8, 0.0), (37665.0, 25025.8, 3350.0), (37474.6, 25025.8, 0.0), (37474.6, 25025.8, 3350.0), (37474.6, 19449.9, 0.0), (37474.6, 19449.9, 3350.0), (37474.6, 17316.1, 0.0), (37474.6, 17316.1, 3350.0), (37665.0, 18014.7, 0.0), (37665.0, 18014.7, 3350.0), (38565.0, 18014.7, 0.0), (38565.0, 18014.7, 3350.0), (38565.0, 17316.1, 0.0), (38565.0, 17316.1, 3350.0), (38565.0, 19245.0, 0.0), (38565.0, 19245.0, 3350.0), (37665.0, 19245.0, 3350.0), (37665.0, 19245.0, 0.0), (38565.0, 18167.1, 0.0), (38565.0, 18167.1, 3350.0), (37665.0, 18167.1, 0.0), (37665.0, 18167.1, 3350.0)], [[1, 2, 3], [1, 3, 4], [2, 5, 6], [2, 6, 3], [5, 7, 8], [5, 8, 6], [7, 9, 10], [7, 10, 8], [9, 11, 12], [9, 12, 10], [11, 13, 14], [11, 14, 12], [15, 16, 14], [13, 15, 14], [15, 17, 18], [15, 18, 16], [17, 19, 20], [17, 20, 18], [19, 21, 22], [19, 22, 20], [21, 23, 24], [21, 24, 22], [23, 25, 26], [23, 26, 24], [25, 1, 4], [25, 4, 26], [1, 27, 28], [1, 28, 4], [29, 30, 28], [27, 29, 28], [29, 31, 32], [29, 32, 30], [1, 4, 32], [31, 1, 32], [33, 34, 35], [36, 33, 35], [33, 37, 38], [33, 38, 34], [39, 40, 38], [37, 39, 38], [39, 36, 35], [39, 35, 40], [9, 7, 5], [31, 9, 5], [2, 31, 5], [29, 9, 31], [1, 31, 2], [27, 1, 25], [39, 29, 27], [39, 37, 29], [39, 27, 25], [11, 15, 13], [33, 11, 37], [33, 15, 11], [17, 33, 36], [17, 15, 33], [23, 36, 39], [23, 17, 36], [23, 39, 25], [21, 19, 17], [21, 17, 23], [11, 9, 29], [11, 29, 37], [8, 10, 6], [10, 32, 6], [32, 3, 6], [10, 30, 32], [32, 4, 3], [4, 28, 26], [30, 40, 28], [38, 40, 30], [28, 40, 26], [16, 12, 14], [12, 34, 38], [16, 34, 12], [34, 18, 35], [16, 18, 34], [35, 24, 40], [18, 24, 35], [40, 24, 26], [20, 22, 18], [18, 22, 24], [10, 12, 30], [30, 12, 38]], closed=True),
])
wall_40_placement = place(storey_placement, origin())
element("IfcWall", 40, at=wall_40_placement, inside=storey, Name="B5_Walls_B5_059", context=model_context, shape_type="Tessellation", body=[
    triangles([(40419.5, 16922.4, 0.0), (40419.5, 17316.1, 0.0), (40419.5, 17316.1, 3350.0), (40419.5, 16922.4, 3350.0), (40216.4, 16922.4, 0.0), (40216.4, 16922.4, 3350.0), (40216.4, 17316.1, 0.0), (40216.4, 17316.1, 3350.0)], [[1, 2, 3], [1, 3, 4], [5, 1, 4], [5, 4, 6], [7, 5, 6], [7, 6, 8], [2, 7, 8], [2, 8, 3], [7, 2, 1], [7, 1, 5], [3, 8, 4], [4, 8, 6]], closed=True),
])
wall_41_placement = place(storey_placement, origin())
element("IfcWall", 41, at=wall_41_placement, inside=storey, Name="B5_Walls_B5_060", context=model_context, shape_type="Tessellation", body=[
    triangles([(40813.0, 19449.9, 0.0), (40813.0, 25025.8, 0.0), (40813.0, 25025.8, 3350.0), (40813.0, 19449.9, 3350.0), (40813.0, 17316.1, 0.0), (40813.0, 17316.1, 3350.0), (40419.5, 17316.1, 0.0), (40419.5, 17316.1, 3350.0), (40419.5, 19245.0, 0.0), (40419.5, 19245.0, 3350.0), (40215.0, 19245.0, 0.0), (40215.0, 19245.0, 3350.0), (40215.0, 19450.0, 3350.0), (40215.0, 19450.0, 0.0), (40419.5, 19450.0, 0.0), (40419.5, 19450.0, 3350.0), (40419.5, 25025.8, 0.0), (40419.5, 25025.8, 3350.0)], [[1, 2, 3], [1, 3, 4], [5, 1, 4], [5, 4, 6], [7, 5, 6], [7, 6, 8], [9, 7, 8], [9, 8, 10], [11, 9, 10], [11, 10, 12], [11, 12, 13], [14, 11, 13], [15, 14, 13], [15, 13, 16], [17, 15, 16], [17, 16, 18], [2, 17, 18], [2, 18, 3], [9, 1, 5], [9, 5, 7], [15, 1, 9], [14, 9, 11], [14, 15, 9], [2, 1, 15], [17, 2, 15], [4, 10, 6], [6, 10, 8], [4, 16, 10], [10, 13, 12], [16, 13, 10], [4, 3, 16], [3, 18, 16]], closed=True),
])
wall_42_placement = place(storey_placement, origin())
element("IfcWall", 42, at=wall_42_placement, inside=storey, Name="B5_Walls_B5_061", context=model_context, shape_type="Tessellation", body=[
    triangles([(40419.5, 25025.8, 0.0), (40419.5, 25419.5, 0.0), (40419.5, 25419.5, 3350.0), (40419.5, 25025.8, 3350.0), (37665.0, 25025.8, 0.0), (37665.0, 25025.8, 3350.0), (37665.0, 25419.5, 0.0), (37665.0, 25419.5, 3350.0)], [[1, 2, 3], [1, 3, 4], [5, 1, 4], [5, 4, 6], [7, 5, 6], [7, 6, 8], [2, 7, 8], [2, 8, 3], [7, 2, 1], [7, 1, 5], [3, 8, 4], [4, 8, 6]], closed=True),
])

save(model, "model.ifc")
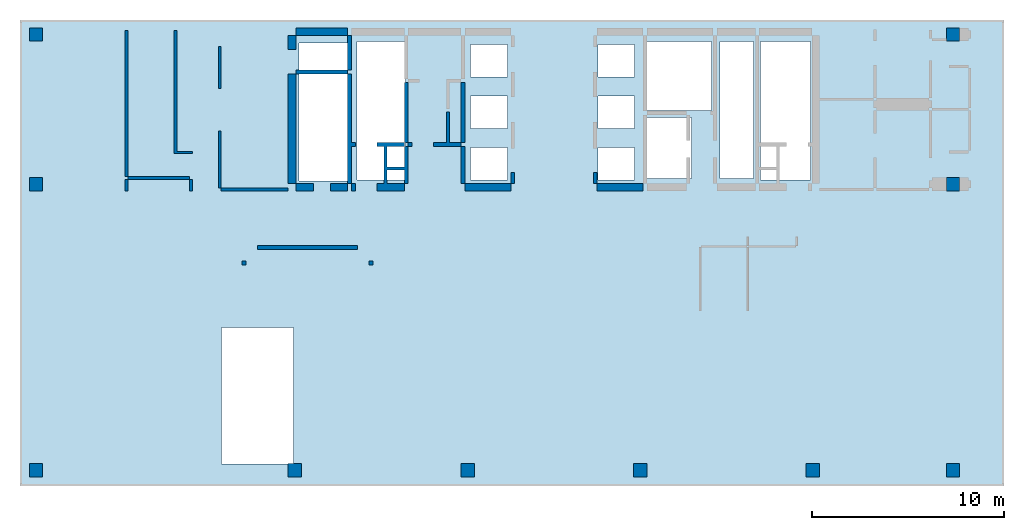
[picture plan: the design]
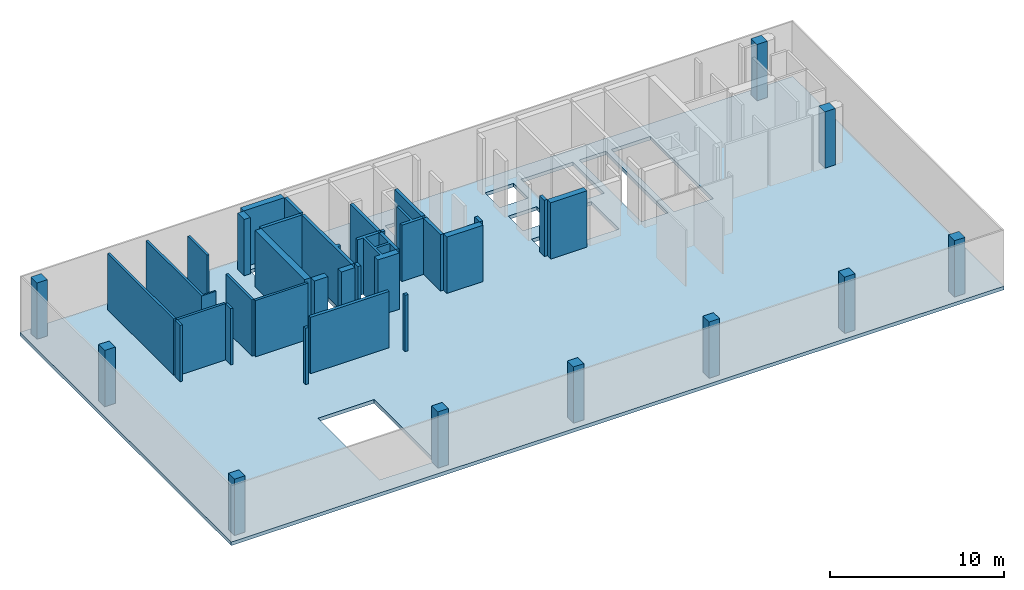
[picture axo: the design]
# One storey, part 1 of 4: 30 walls, 10 columns, 1 slab.
"""IFC4 building model written with IfcOpenShell, lengths in millimetres."""

from ifc_helpers import new_model, si_unit, frame, origin, place, context, project, spatial, triangles, element, save


model = new_model("IFC4")

# Units and contexts
model_context = context("Model", 3, precision=0.001, world=origin())
ifc_project = project(units=[si_unit("LENGTHUNIT", "METRE", prefix="MILLI"), si_unit("AREAUNIT", "SQUARE_METRE"), si_unit("VOLUMEUNIT", "CUBIC_METRE")], contexts=[model_context])

# Site, building, storey
site_placement = place(None, origin())
site = spatial("IfcSite", under=ifc_project, at=site_placement, CompositionType="ELEMENT")
building_placement = place(site_placement, origin())
building = spatial("IfcBuilding", under=site, at=building_placement, CompositionType="ELEMENT")
storey_placement = place(building_placement, frame((0.0, 0.0, 47000.0)))
storey = spatial("IfcBuildingStorey", under=building, at=storey_placement, Name="F11", CompositionType="ELEMENT", Elevation=47000.0)

# Columns
column_1_placement = place(storey_placement, origin())
element("IfcColumn", 1, at=column_1_placement, inside=storey, Name="F11_Columns_F11_001", context=model_context, shape_type="Tessellation", body=[
    triangles([(40114.8, 2023.7, 0.0), (40114.8, 2023.7, 3950.0), (40114.8, 2722.3, 0.0), (40114.8, 2722.3, 3950.0), (40813.0, 2023.7, 3950.0), (40813.0, 2023.7, 0.0), (40813.0, 2722.3, 0.0), (40813.0, 2722.3, 3950.0)], [[1, 2, 3], [3, 2, 4], [5, 6, 7], [5, 7, 8], [6, 5, 1], [1, 5, 2], [8, 7, 3], [8, 3, 4], [3, 7, 1], [1, 7, 6], [8, 4, 2], [8, 2, 5]], closed=True),
])
column_2_placement = place(storey_placement, origin())
element("IfcColumn", 2, at=column_2_placement, inside=storey, Name="F11_Columns_F11_002", context=model_context, shape_type="Tessellation", body=[
    triangles([(47413.4, 24721.0, 0.0), (47413.4, 24721.0, 3950.0), (47413.4, 25419.5, 0.0), (47413.4, 25419.5, 3950.0), (48111.6, 24721.0, 3950.0), (48111.6, 24721.0, 0.0), (48111.6, 25419.5, 0.0), (48111.6, 25419.5, 3950.0)], [[1, 2, 3], [3, 2, 4], [5, 6, 7], [5, 7, 8], [6, 5, 1], [1, 5, 2], [8, 7, 3], [8, 3, 4], [1, 3, 6], [3, 7, 6], [4, 2, 5], [8, 4, 5]], closed=True),
])
column_3_placement = place(storey_placement, origin())
element("IfcColumn", 3, at=column_3_placement, inside=storey, Name="F11_Columns_F11_003", context=model_context, shape_type="Tessellation", body=[
    triangles([(47413.4, 16922.4, 0.0), (47413.4, 16922.4, 3950.0), (47413.4, 17620.9, 0.0), (47413.4, 17620.9, 3950.0), (48111.6, 16922.4, 3950.0), (48111.6, 16922.4, 0.0), (48111.6, 17620.9, 0.0), (48111.6, 17620.9, 3950.0)], [[1, 2, 3], [3, 2, 4], [5, 6, 7], [5, 7, 8], [6, 5, 1], [1, 5, 2], [8, 7, 3], [8, 3, 4], [1, 3, 6], [3, 7, 6], [4, 2, 5], [8, 4, 5]], closed=True),
])
column_4_placement = place(storey_placement, origin())
element("IfcColumn", 4, at=column_4_placement, inside=storey, Name="F11_Columns_F11_004", context=model_context, shape_type="Tessellation", body=[
    triangles([(13129.0, 2023.7, 0.0), (13129.0, 2023.7, 3950.0), (13129.0, 2722.3, 0.0), (13129.0, 2722.3, 3950.0), (13827.2, 2023.7, 3950.0), (13827.2, 2023.7, 0.0), (13827.2, 2722.3, 0.0), (13827.2, 2722.3, 3950.0)], [[1, 2, 3], [3, 2, 4], [5, 6, 7], [5, 7, 8], [6, 5, 1], [1, 5, 2], [8, 7, 3], [8, 3, 4], [3, 7, 1], [1, 7, 6], [8, 4, 2], [8, 2, 5]], closed=True),
])
column_5_placement = place(storey_placement, origin())
element("IfcColumn", 5, at=column_5_placement, inside=storey, Name="F11_Columns_F11_005", context=model_context, shape_type="Tessellation", body=[
    triangles([(47413.4, 2023.7, 0.0), (47413.4, 2023.7, 3950.0), (47413.4, 2722.3, 0.0), (47413.4, 2722.3, 3950.0), (48111.6, 2023.7, 3950.0), (48111.6, 2023.7, 0.0), (48111.6, 2722.3, 0.0), (48111.6, 2722.3, 3950.0)], [[1, 2, 3], [3, 2, 4], [5, 6, 7], [5, 7, 8], [6, 5, 1], [1, 5, 2], [8, 7, 3], [8, 3, 4], [3, 7, 1], [1, 7, 6], [8, 4, 2], [8, 2, 5]], closed=True),
])
column_6_placement = place(storey_placement, origin())
element("IfcColumn", 6, at=column_6_placement, inside=storey, Name="F11_Columns_F11_006", context=model_context, shape_type="Tessellation", body=[
    triangles([(-363.9, 2023.7, 0.0), (-363.9, 2023.7, 3950.0), (-363.9, 2722.3, 0.0), (-363.9, 2722.3, 3950.0), (334.3, 2023.7, 3950.0), (334.3, 2023.7, 0.0), (334.3, 2722.3, 0.0), (334.3, 2722.3, 3950.0)], [[1, 2, 3], [3, 2, 4], [5, 6, 7], [5, 7, 8], [6, 5, 1], [1, 5, 2], [8, 7, 3], [8, 3, 4], [3, 7, 1], [1, 7, 6], [8, 4, 2], [8, 2, 5]], closed=True),
])
column_7_placement = place(storey_placement, origin())
element("IfcColumn", 7, at=column_7_placement, inside=storey, Name="F11_Columns_F11_007", context=model_context, shape_type="Tessellation", body=[
    triangles([(-363.9, 24721.0, 0.0), (-363.9, 24721.0, 3950.0), (-363.9, 25419.5, 0.0), (-363.9, 25419.5, 3950.0), (334.3, 24721.0, 3950.0), (334.3, 24721.0, 0.0), (334.3, 25419.5, 0.0), (334.3, 25419.5, 3950.0)], [[1, 2, 3], [3, 2, 4], [5, 6, 7], [5, 7, 8], [6, 5, 1], [1, 5, 2], [8, 7, 3], [8, 3, 4], [3, 7, 1], [1, 7, 6], [8, 4, 2], [8, 2, 5]], closed=True),
])
column_8_placement = place(storey_placement, origin())
element("IfcColumn", 8, at=column_8_placement, inside=storey, Name="F11_Columns_F11_008", context=model_context, shape_type="Tessellation", body=[
    triangles([(31128.0, 2023.7, 0.0), (31128.0, 2023.7, 3950.0), (31128.0, 2722.3, 0.0), (31128.0, 2722.3, 3950.0), (31826.2, 2023.7, 3950.0), (31826.2, 2023.7, 0.0), (31826.2, 2722.3, 0.0), (31826.2, 2722.3, 3950.0)], [[1, 2, 3], [3, 2, 4], [5, 6, 7], [5, 7, 8], [6, 5, 1], [1, 5, 2], [8, 7, 3], [8, 3, 4], [3, 7, 1], [1, 7, 6], [8, 4, 2], [8, 2, 5]], closed=True),
])
column_9_placement = place(storey_placement, origin())
element("IfcColumn", 9, at=column_9_placement, inside=storey, Name="F11_Columns_F11_009", context=model_context, shape_type="Tessellation", body=[
    triangles([(22128.5, 2023.7, 0.0), (22128.5, 2023.7, 3950.0), (22128.5, 2722.3, 0.0), (22128.5, 2722.3, 3950.0), (22826.7, 2023.7, 3950.0), (22826.7, 2023.7, 0.0), (22826.7, 2722.3, 0.0), (22826.7, 2722.3, 3950.0)], [[1, 2, 3], [3, 2, 4], [5, 6, 7], [5, 7, 8], [6, 5, 1], [1, 5, 2], [8, 7, 3], [8, 3, 4], [3, 7, 1], [1, 7, 6], [8, 4, 2], [8, 2, 5]], closed=True),
])
column_10_placement = place(storey_placement, origin())
element("IfcColumn", 10, at=column_10_placement, inside=storey, Name="F11_Columns_F11_010", context=model_context, shape_type="Tessellation", body=[
    triangles([(-363.9, 16922.4, 0.0), (-363.9, 16922.4, 3950.0), (-363.9, 17620.9, 0.0), (-363.9, 17620.9, 3950.0), (334.3, 16922.4, 3950.0), (334.3, 16922.4, 0.0), (334.3, 17620.9, 0.0), (334.3, 17620.9, 3950.0)], [[1, 2, 3], [3, 2, 4], [5, 6, 7], [5, 7, 8], [6, 5, 1], [1, 5, 2], [8, 7, 3], [8, 3, 4], [3, 7, 1], [1, 7, 6], [8, 4, 2], [8, 2, 5]], closed=True),
])

# Slab
slab_placement = place(storey_placement, origin())
element("IfcSlab", 11, at=slab_placement, inside=storey, Name="F11_Slab_F11_001", context=model_context, shape_type="Tessellation", body=[
    triangles([(-846.215139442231, 25825.974025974, 0.0), (50420.3187250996, 25825.974025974, -250.0), (-846.215139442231, 25825.974025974, -250.0), (50420.3187250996, 25825.974025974, 0.0), (-846.215139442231, 1552.38095238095, 0.0), (-846.215139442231, 1552.38095238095, -250.0), (50420.3187250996, 1552.38095238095, 0.0), (50420.3187250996, 1552.38095238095, -250.0), (13398.406374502, 9808.22510822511, -250.0), (9660.9561752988, 9808.22510822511, 0.0), (9660.9561752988, 9808.22510822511, -250.0), (13398.406374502, 9808.22510822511, 0.0), (13398.406374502, 2681.38528138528, 0.0), (13398.406374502, 2681.38528138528, -250.0), (9660.9561752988, 2681.38528138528, -250.0), (9660.9561752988, 2681.38528138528, 0.0), (34130.6772908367, 20745.4545454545, -250.0), (31733.0677290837, 20745.4545454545, 0.0), (31733.0677290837, 20745.4545454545, -250.0), (34130.6772908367, 20745.4545454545, 0.0), (31733.0677290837, 17570.1298701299, 0.0), (31733.0677290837, 17570.1298701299, -250.0), (34130.6772908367, 17570.1298701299, 0.0), (34130.6772908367, 17570.1298701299, -250.0), (31168.9243027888, 19193.0735930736, 0.0), (29264.9402390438, 19193.0735930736, 0.0), (29264.9402390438, 19193.0735930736, -250.0), (31168.9243027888, 19193.0735930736, -250.0), (29264.9402390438, 17499.5670995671, 0.0), (29264.9402390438, 17499.5670995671, -250.0), (31168.9243027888, 17499.5670995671, 0.0), (31168.9243027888, 17499.5670995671, -250.0), (40336.2549800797, 24696.9696969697, -250.0), (37727.0916334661, 24696.9696969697, 0.0), (37727.0916334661, 24696.9696969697, -250.0), (40336.2549800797, 24696.9696969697, 0.0), (37727.0916334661, 17499.5670995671, 0.0), (37727.0916334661, 17499.5670995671, -250.0), (40336.2549800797, 17499.5670995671, 0.0), (40336.2549800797, 17499.5670995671, -250.0), (37374.5019920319, 24696.9696969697, 0.0), (35611.5537848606, 24696.9696969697, 0.0), (35611.5537848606, 24696.9696969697, -250.0), (37374.5019920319, 24696.9696969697, -250.0), (35611.5537848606, 17570.1298701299, 0.0), (35611.5537848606, 17570.1298701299, -250.0), (37374.5019920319, 17570.1298701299, 0.0), (37374.5019920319, 17570.1298701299, -250.0), (35188.4462151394, 24696.9696969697, 0.0), (31733.0677290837, 24696.9696969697, 0.0), (31733.0677290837, 24696.9696969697, -250.0), (35188.4462151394, 24696.9696969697, -250.0), (31733.0677290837, 21098.2683982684, 0.0), (31733.0677290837, 21098.2683982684, -250.0), (35188.4462151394, 21098.2683982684, 0.0), (35188.4462151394, 21098.2683982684, -250.0), (31168.9243027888, 21874.4588744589, 0.0), (29264.9402390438, 21874.4588744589, 0.0), (29264.9402390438, 21874.4588744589, -250.0), (31168.9243027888, 21874.4588744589, -250.0), (29264.9402390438, 20180.9523809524, 0.0), (29264.9402390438, 20180.9523809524, -250.0), (31168.9243027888, 20180.9523809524, 0.0), (31168.9243027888, 20180.9523809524, -250.0), (31168.9243027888, 24555.8441558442, 0.0), (29264.9402390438, 24555.8441558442, 0.0), (29264.9402390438, 24555.8441558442, -250.0), (31168.9243027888, 24555.8441558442, -250.0), (29264.9402390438, 22862.3376623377, 0.0), (29264.9402390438, 22862.3376623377, -250.0), (31168.9243027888, 22862.3376623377, 0.0), (31168.9243027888, 22862.3376623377, -250.0), (24540.2390438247, 19193.0735930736, -250.0), (22636.2549800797, 19193.0735930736, 0.0), (22636.2549800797, 19193.0735930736, -250.0), (24540.2390438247, 19193.0735930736, 0.0), (22636.2549800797, 17499.5670995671, 0.0), (22636.2549800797, 17499.5670995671, -250.0), (24540.2390438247, 17499.5670995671, 0.0), (24540.2390438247, 17499.5670995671, -250.0), (24540.2390438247, 21874.4588744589, -250.0), (22636.2549800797, 21874.4588744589, 0.0), (22636.2549800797, 21874.4588744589, -250.0), (24540.2390438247, 21874.4588744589, 0.0), (22636.2549800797, 20180.9523809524, 0.0), (22636.2549800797, 20180.9523809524, -250.0), (24540.2390438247, 20180.9523809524, 0.0), (24540.2390438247, 20180.9523809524, -250.0), (19251.3944223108, 24696.9696969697, 0.0), (16712.7490039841, 24696.9696969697, 0.0), (16712.7490039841, 24696.9696969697, -250.0), (19251.3944223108, 24696.9696969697, -250.0), (16712.7490039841, 17499.5670995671, 0.0), (16712.7490039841, 17499.5670995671, -250.0), (19251.3944223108, 17499.5670995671, 0.0), (19251.3944223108, 17499.5670995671, -250.0), (24540.2390438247, 24555.8441558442, -250.0), (22636.2549800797, 24555.8441558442, 0.0), (22636.2549800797, 24555.8441558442, -250.0), (24540.2390438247, 24555.8441558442, 0.0), (22636.2549800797, 22862.3376623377, 0.0), (22636.2549800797, 22862.3376623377, -250.0), (24540.2390438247, 22862.3376623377, 0.0), (24540.2390438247, 22862.3376623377, -250.0), (16219.1235059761, 24626.4069264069, 0.0), (13680.4780876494, 24626.4069264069, 0.0), (13680.4780876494, 24626.4069264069, -250.0), (16219.1235059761, 24626.4069264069, -250.0), (13680.4780876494, 17429.0043290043, 0.0), (13680.4780876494, 17429.0043290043, -250.0), (16219.1235059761, 17429.0043290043, 0.0), (16219.1235059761, 17429.0043290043, -250.0)], [[1, 2, 3], [1, 4, 2], [5, 1, 6], [6, 1, 3], [4, 7, 2], [2, 7, 8], [7, 6, 8], [7, 5, 6], [9, 10, 11], [12, 10, 9], [13, 12, 9], [13, 9, 14], [15, 13, 14], [16, 13, 15], [10, 16, 15], [10, 15, 11], [17, 18, 19], [20, 18, 17], [18, 21, 22], [18, 22, 19], [23, 20, 17], [23, 17, 24], [22, 23, 24], [21, 23, 22], [25, 26, 27], [25, 27, 28], [26, 29, 30], [26, 30, 27], [31, 25, 28], [31, 28, 32], [29, 31, 32], [29, 32, 30], [33, 34, 35], [36, 34, 33], [34, 37, 38], [34, 38, 35], [39, 36, 33], [39, 33, 40], [38, 39, 40], [37, 39, 38], [41, 42, 43], [41, 43, 44], [42, 45, 46], [42, 46, 43], [47, 41, 44], [47, 44, 48], [45, 47, 48], [45, 48, 46], [49, 50, 51], [49, 51, 52], [50, 53, 54], [50, 54, 51], [55, 49, 52], [55, 52, 56], [53, 55, 56], [53, 56, 54], [57, 58, 59], [57, 59, 60], [58, 61, 62], [58, 62, 59], [63, 57, 60], [63, 60, 64], [61, 63, 64], [61, 64, 62], [65, 66, 67], [65, 67, 68], [66, 69, 70], [66, 70, 67], [71, 65, 68], [71, 68, 72], [69, 71, 72], [69, 72, 70], [73, 74, 75], [76, 74, 73], [74, 77, 78], [74, 78, 75], [79, 76, 73], [79, 73, 80], [78, 79, 80], [77, 79, 78], [81, 82, 83], [84, 82, 81], [82, 85, 86], [82, 86, 83], [87, 84, 81], [87, 81, 88], [86, 87, 88], [85, 87, 86], [89, 90, 91], [89, 91, 92], [90, 93, 94], [90, 94, 91], [95, 89, 92], [95, 92, 96], [93, 95, 96], [93, 96, 94], [97, 98, 99], [100, 98, 97], [98, 101, 102], [98, 102, 99], [103, 100, 97], [103, 97, 104], [102, 103, 104], [101, 103, 102], [105, 106, 107], [105, 107, 108], [106, 109, 110], [106, 110, 107], [111, 105, 108], [111, 108, 112], [109, 111, 112], [109, 112, 110], [4, 39, 7], [39, 37, 7], [37, 45, 7], [47, 45, 37], [45, 23, 7], [4, 36, 39], [21, 31, 23], [23, 31, 7], [55, 20, 45], [45, 20, 23], [21, 25, 31], [25, 18, 63], [29, 13, 31], [31, 13, 7], [18, 53, 63], [20, 53, 18], [42, 49, 55], [63, 26, 25], [53, 57, 63], [63, 61, 26], [53, 71, 57], [29, 79, 13], [50, 65, 71], [71, 69, 57], [57, 69, 58], [26, 76, 29], [61, 76, 26], [29, 76, 79], [50, 66, 65], [61, 87, 76], [58, 87, 61], [79, 12, 13], [77, 12, 79], [58, 84, 87], [76, 85, 74], [87, 85, 76], [74, 95, 77], [77, 95, 12], [85, 95, 74], [69, 103, 58], [58, 103, 84], [85, 82, 95], [103, 82, 84], [69, 100, 103], [66, 100, 69], [103, 101, 82], [95, 93, 12], [93, 111, 12], [10, 5, 16], [16, 5, 13], [12, 109, 10], [111, 109, 12], [82, 89, 95], [98, 89, 101], [101, 89, 82], [90, 105, 93], [93, 105, 111], [90, 106, 105], [10, 1, 5], [106, 1, 109], [109, 1, 10], [4, 1, 36], [36, 1, 34], [34, 1, 41], [41, 1, 42], [42, 1, 49], [49, 1, 50], [50, 1, 66], [66, 1, 100], [100, 1, 98], [98, 1, 89], [89, 1, 90], [90, 1, 106], [5, 7, 13], [21, 18, 25], [45, 42, 55], [41, 47, 34], [34, 47, 37], [53, 50, 71], [55, 53, 20], [40, 2, 8], [38, 40, 8], [46, 38, 8], [46, 48, 38], [24, 46, 8], [33, 2, 40], [32, 22, 24], [32, 24, 8], [17, 56, 46], [17, 46, 24], [28, 22, 32], [19, 28, 64], [14, 30, 32], [14, 32, 8], [54, 19, 64], [54, 17, 19], [52, 43, 56], [27, 64, 28], [60, 54, 64], [62, 64, 27], [72, 54, 60], [80, 30, 14], [68, 51, 72], [70, 72, 60], [70, 60, 59], [73, 27, 30], [73, 62, 27], [73, 30, 80], [67, 51, 68], [88, 62, 73], [88, 59, 62], [9, 80, 14], [9, 78, 80], [81, 59, 88], [86, 73, 75], [86, 88, 73], [96, 75, 78], [96, 78, 9], [96, 86, 75], [104, 70, 59], [104, 59, 81], [83, 86, 96], [83, 104, 81], [97, 70, 104], [97, 67, 70], [102, 104, 83], [94, 96, 9], [112, 94, 9], [6, 11, 15], [6, 15, 14], [110, 9, 11], [110, 112, 9], [92, 83, 96], [92, 99, 102], [92, 102, 83], [108, 91, 94], [108, 94, 112], [107, 91, 108], [3, 11, 6], [3, 107, 110], [3, 110, 11], [3, 2, 33], [3, 33, 35], [3, 35, 44], [3, 44, 43], [3, 43, 52], [3, 52, 51], [3, 51, 67], [3, 67, 97], [3, 97, 99], [3, 99, 92], [3, 92, 91], [3, 91, 107], [8, 6, 14], [19, 22, 28], [43, 46, 56], [48, 44, 35], [48, 35, 38], [51, 54, 72], [54, 56, 17]], closed=True),
])

# Walls
wall_1_placement = place(storey_placement, origin())
element("IfcWall", 12, at=wall_1_placement, inside=storey, Name="F11_Walls_F11_001", context=model_context, shape_type="Tessellation", body=[
    triangles([(17533.6, 13073.9, 0.0), (17533.6, 13277.1, 0.0), (17533.6, 13277.1, 3950.0), (17533.6, 13073.9, 3950.0), (17330.5, 13073.9, 0.0), (17330.5, 13073.9, 3950.0), (17330.5, 13277.1, 0.0), (17330.5, 13277.1, 3950.0)], [[1, 2, 3], [1, 3, 4], [5, 1, 4], [5, 4, 6], [7, 5, 6], [7, 6, 8], [2, 7, 8], [2, 8, 3], [2, 1, 5], [7, 2, 5], [4, 3, 6], [3, 8, 6]], closed=True),
])
wall_2_placement = place(storey_placement, origin())
element("IfcWall", 13, at=wall_2_placement, inside=storey, Name="F11_Walls_F11_002", context=model_context, shape_type="Tessellation", body=[
    triangles([(10933.1, 13073.9, 0.0), (10933.1, 13277.1, 0.0), (10933.1, 13277.1, 3950.0), (10933.1, 13073.9, 3950.0), (10730.0, 13073.9, 0.0), (10730.0, 13073.9, 3950.0), (10730.0, 13277.1, 0.0), (10730.0, 13277.1, 3950.0)], [[1, 2, 3], [1, 3, 4], [5, 1, 4], [5, 4, 6], [7, 5, 6], [7, 6, 8], [2, 7, 8], [2, 8, 3], [7, 2, 1], [7, 1, 5], [3, 8, 4], [4, 8, 6]], closed=True),
])
wall_3_placement = place(storey_placement, origin())
element("IfcWall", 14, at=wall_3_placement, inside=storey, Name="F11_Walls_F11_003", context=model_context, shape_type="Tessellation", body=[
    triangles([(16733.9, 13874.1, 0.0), (16733.9, 14077.3, 0.0), (16733.9, 14077.3, 3950.0), (16733.9, 13874.1, 3950.0), (11529.7, 13874.1, 0.0), (11529.7, 13874.1, 3950.0), (11529.7, 14077.3, 0.0), (11529.7, 14077.3, 3950.0)], [[1, 2, 3], [1, 3, 4], [5, 1, 4], [5, 4, 6], [7, 5, 6], [7, 6, 8], [2, 7, 8], [2, 8, 3], [7, 2, 1], [7, 1, 5], [3, 8, 4], [4, 8, 6]], closed=True),
])
wall_4_placement = place(storey_placement, origin())
element("IfcWall", 15, at=wall_4_placement, inside=storey, Name="F11_Walls_F11_004", context=model_context, shape_type="Tessellation", body=[
    triangles([(13129.0, 16922.4, 0.0), (13129.0, 17074.8, 0.0), (13129.0, 17074.8, 3950.0), (13129.0, 16922.4, 3950.0), (9638.4, 16922.4, 3950.0), (9638.4, 16922.4, 0.0), (9638.4, 17074.8, 0.0), (9638.4, 17074.8, 3950.0)], [[1, 2, 3], [1, 3, 4], [1, 4, 5], [6, 1, 5], [7, 6, 5], [7, 5, 8], [7, 8, 3], [2, 7, 3], [7, 2, 1], [7, 1, 6], [3, 8, 4], [4, 8, 5]], closed=True),
])
wall_5_placement = place(storey_placement, origin())
element("IfcWall", 16, at=wall_5_placement, inside=storey, Name="F11_Walls_F11_005", context=model_context, shape_type="Tessellation", body=[
    triangles([(16226.2, 17316.1, 0.0), (16226.2, 17316.1, 3950.0), (16226.2, 16922.4, 3950.0), (16226.2, 16922.4, 0.0), (15337.6, 16922.4, 0.0), (15337.6, 16922.4, 3950.0), (15337.6, 17316.1, 3950.0), (15337.6, 17316.1, 0.0)], [[1, 2, 3], [4, 1, 3], [5, 4, 3], [5, 3, 6], [5, 6, 7], [8, 5, 7], [1, 8, 7], [1, 7, 2], [8, 1, 4], [8, 4, 5], [2, 7, 3], [3, 7, 6]], closed=True),
])
wall_6_placement = place(storey_placement, origin())
element("IfcWall", 17, at=wall_6_placement, inside=storey, Name="F11_Walls_F11_006", context=model_context, shape_type="Tessellation", body=[
    triangles([(16632.4, 17316.1, 0.0), (16632.4, 17316.1, 3950.0), (16632.4, 16922.4, 3950.0), (16632.4, 16922.4, 0.0), (16429.3, 16922.4, 3950.0), (16429.3, 16922.4, 0.0), (16429.3, 17316.1, 3950.0), (16429.3, 17316.1, 0.0)], [[1, 2, 3], [4, 1, 3], [4, 3, 5], [6, 4, 5], [6, 5, 7], [8, 6, 7], [8, 7, 2], [1, 8, 2], [8, 1, 4], [8, 4, 6], [2, 7, 3], [3, 7, 5]], closed=True),
])
wall_7_placement = place(storey_placement, origin())
element("IfcWall", 18, at=wall_7_placement, inside=storey, Name="F11_Walls_F11_007", context=model_context, shape_type="Tessellation", body=[
    triangles([(17749.4, 16922.4, 0.0), (17749.4, 16922.4, 3950.0), (17749.4, 17316.1, 3950.0), (17749.4, 17316.1, 0.0), (19183.7, 16922.4, 0.0), (19183.7, 16922.4, 3950.0), (19183.7, 17316.1, 0.0), (19183.7, 17316.1, 3950.0), (19374.1, 17316.1, 0.0), (19374.1, 17316.1, 3950.0), (19374.1, 19246.7, 0.0), (19374.1, 19246.7, 3950.0), (19183.7, 19246.7, 0.0), (19183.7, 19246.7, 3950.0), (19183.7, 19449.9, 0.0), (19183.7, 19449.9, 3950.0), (17749.4, 19449.9, 0.0), (17749.4, 19449.9, 3950.0), (17749.4, 19246.7, 0.0), (17749.4, 19246.7, 3950.0), (18130.2, 19246.7, 0.0), (18130.2, 19246.7, 3950.0), (18130.2, 19245.0, 0.0), (18130.2, 19245.0, 3950.0), (18130.0, 19245.0, 0.0), (18130.0, 19245.0, 3950.0), (18130.0, 17316.1, 0.0), (18130.0, 17316.1, 3950.0), (18282.5, 17316.1, 0.0), (18282.5, 17316.1, 3950.0), (18282.5, 18014.7, 0.0), (18282.5, 18014.7, 3950.0), (19183.7, 18014.7, 0.0), (19183.7, 18014.7, 3950.0), (19183.7, 18167.1, 0.0), (19183.7, 18167.1, 3950.0), (18282.5, 18167.1, 0.0), (18282.5, 18167.1, 3950.0), (18282.5, 19246.7, 0.0), (18282.5, 19246.7, 3950.0)], [[1, 2, 3], [4, 1, 3], [1, 5, 6], [1, 6, 2], [7, 8, 6], [5, 7, 6], [7, 9, 10], [7, 10, 8], [9, 11, 12], [9, 12, 10], [11, 13, 14], [11, 14, 12], [13, 15, 16], [13, 16, 14], [15, 17, 18], [15, 18, 16], [17, 19, 20], [17, 20, 18], [21, 22, 20], [19, 21, 20], [21, 23, 24], [21, 24, 22], [23, 25, 26], [23, 26, 24], [25, 27, 28], [25, 28, 26], [27, 4, 3], [27, 3, 28], [7, 29, 30], [7, 30, 8], [29, 31, 32], [29, 32, 30], [31, 33, 34], [31, 34, 32], [33, 7, 8], [33, 8, 34], [13, 35, 36], [13, 36, 14], [35, 37, 38], [35, 38, 36], [37, 39, 40], [37, 40, 38], [39, 13, 14], [39, 14, 40], [33, 9, 7], [35, 9, 33], [29, 7, 5], [1, 29, 5], [27, 29, 1], [4, 27, 1], [31, 35, 33], [31, 29, 27], [11, 9, 35], [37, 35, 31], [13, 11, 35], [39, 15, 13], [23, 39, 37], [25, 23, 37], [21, 39, 23], [17, 21, 19], [17, 15, 39], [17, 39, 21], [27, 25, 37], [27, 37, 31], [10, 34, 8], [10, 36, 34], [8, 30, 6], [30, 2, 6], [30, 28, 2], [28, 3, 2], [36, 32, 34], [30, 32, 28], [10, 12, 36], [36, 38, 32], [12, 14, 36], [16, 40, 14], [40, 24, 38], [24, 26, 38], [40, 22, 24], [22, 18, 20], [16, 18, 40], [40, 18, 22], [26, 28, 38], [38, 28, 32]], closed=True),
])
wall_8_placement = place(storey_placement, origin())
element("IfcWall", 19, at=wall_8_placement, inside=storey, Name="F11_Walls_F11_008", context=model_context, shape_type="Tessellation", body=[
    triangles([(14436.4, 17316.1, 0.0), (14436.4, 17316.1, 3950.0), (14436.4, 16922.4, 3950.0), (14436.4, 16922.4, 0.0), (13535.2, 16922.4, 0.0), (13535.2, 16922.4, 3950.0), (13535.2, 17316.1, 3950.0), (13535.2, 17316.1, 0.0)], [[1, 2, 3], [4, 1, 3], [5, 4, 3], [5, 3, 6], [5, 6, 7], [8, 5, 7], [1, 8, 7], [1, 7, 2], [8, 1, 4], [8, 4, 5], [2, 7, 3], [3, 7, 6]], closed=True),
])
wall_9_placement = place(storey_placement, origin())
element("IfcWall", 20, at=wall_9_placement, inside=storey, Name="F11_Walls_F11_009", context=model_context, shape_type="Tessellation", body=[
    triangles([(4789.6, 16922.4, 0.0), (4789.6, 17519.3, 0.0), (4789.6, 17519.3, 3950.0), (4789.6, 16922.4, 3950.0), (4637.3, 16922.4, 0.0), (4637.3, 16922.4, 3950.0), (4637.3, 17519.3, 0.0), (4637.3, 17519.3, 3950.0)], [[1, 2, 3], [1, 3, 4], [5, 1, 4], [5, 4, 6], [7, 5, 6], [7, 6, 8], [2, 7, 8], [2, 8, 3], [7, 2, 1], [7, 1, 5], [3, 8, 4], [4, 8, 6]], closed=True),
])
wall_10_placement = place(storey_placement, origin())
element("IfcWall", 21, at=wall_10_placement, inside=storey, Name="F11_Walls_F11_010", context=model_context, shape_type="Tessellation", body=[
    triangles([(8140.6, 16922.4, 0.0), (8140.6, 17519.3, 0.0), (8140.6, 17519.3, 3950.0), (8140.6, 16922.4, 3950.0), (7988.3, 16922.4, 0.0), (7988.3, 16922.4, 3950.0), (7988.3, 17519.3, 0.0), (7988.3, 17519.3, 3950.0)], [[1, 2, 3], [1, 3, 4], [5, 1, 4], [5, 4, 6], [7, 5, 6], [7, 6, 8], [2, 7, 8], [2, 8, 3], [7, 2, 1], [7, 1, 5], [3, 8, 4], [4, 8, 6]], closed=True),
])
wall_11_placement = place(storey_placement, origin())
element("IfcWall", 22, at=wall_11_placement, inside=storey, Name="F11_Walls_F11_011", context=model_context, shape_type="Tessellation", body=[
    triangles([(7988.3, 17519.3, 0.0), (7988.3, 17671.7, 0.0), (7988.3, 17671.7, 3950.0), (7988.3, 17519.3, 3950.0), (4789.6, 17519.3, 0.0), (4789.6, 17519.3, 3950.0), (4789.6, 17671.7, 0.0), (4789.6, 17671.7, 3950.0)], [[1, 2, 3], [1, 3, 4], [5, 1, 4], [5, 4, 6], [7, 5, 6], [7, 6, 8], [2, 7, 8], [2, 8, 3], [7, 2, 1], [7, 1, 5], [3, 8, 4], [4, 8, 6]], closed=True),
])
wall_12_placement = place(storey_placement, origin())
element("IfcWall", 23, at=wall_12_placement, inside=storey, Name="F11_Walls_F11_012", context=model_context, shape_type="Tessellation", body=[
    triangles([(16226.2, 23019.0, 0.0), (16226.2, 19449.9, 0.0), (16226.2, 19449.9, 3950.0), (16226.2, 23019.0, 3950.0), (16429.3, 23019.0, 0.0), (16429.3, 23019.0, 3950.0), (16429.3, 19449.9, 0.0), (16429.3, 19449.9, 3950.0), (16632.4, 19449.9, 3950.0), (16632.4, 19449.9, 0.0), (16632.4, 19246.7, 0.0), (16632.4, 19246.7, 3950.0), (16429.3, 19246.7, 3950.0), (16429.3, 19246.7, 0.0), (16429.3, 17316.1, 0.0), (16429.3, 17316.1, 3950.0), (16226.2, 17316.1, 0.0), (16226.2, 17316.1, 3950.0), (16226.2, 19246.7, 0.0), (16226.2, 19246.7, 3950.0)], [[1, 2, 3], [1, 3, 4], [5, 1, 4], [5, 4, 6], [7, 5, 6], [7, 6, 8], [7, 8, 9], [10, 7, 9], [11, 10, 9], [11, 9, 12], [11, 12, 13], [14, 11, 13], [15, 14, 13], [15, 13, 16], [17, 15, 16], [17, 16, 18], [19, 17, 18], [19, 18, 20], [2, 19, 20], [2, 20, 3], [19, 14, 15], [19, 15, 17], [7, 10, 11], [7, 11, 14], [2, 7, 14], [2, 14, 19], [5, 7, 2], [1, 5, 2], [13, 20, 16], [16, 20, 18], [9, 8, 12], [12, 8, 13], [8, 3, 13], [13, 3, 20], [8, 6, 3], [6, 4, 3]], closed=True),
])
wall_13_placement = place(storey_placement, origin())
element("IfcWall", 24, at=wall_13_placement, inside=storey, Name="F11_Walls_F11_013", context=model_context, shape_type="Tessellation", body=[
    triangles([(9638.4, 17074.8, 0.0), (9638.4, 20046.9, 0.0), (9638.4, 20046.9, 3950.0), (9638.4, 17074.8, 3950.0), (9486.1, 17074.8, 0.0), (9486.1, 17074.8, 3950.0), (9486.1, 20046.9, 0.0), (9486.1, 20046.9, 3950.0)], [[1, 2, 3], [1, 3, 4], [5, 1, 4], [5, 4, 6], [7, 5, 6], [7, 6, 8], [2, 7, 8], [2, 8, 3], [7, 2, 1], [7, 1, 5], [3, 8, 4], [4, 8, 6]], closed=True),
])
wall_14_placement = place(storey_placement, origin())
element("IfcWall", 25, at=wall_14_placement, inside=storey, Name="F11_Walls_F11_014", context=model_context, shape_type="Tessellation", body=[
    triangles([(7340.0, 18865.0, 0.0), (8140.0, 18865.0, 0.0), (8140.0, 18865.0, 3950.0), (7340.0, 18865.0, 3950.0), (7340.0, 18865.7, 3950.0), (7340.0, 18865.7, 0.0), (7188.6, 18865.7, 0.0), (7188.6, 18865.7, 3950.0), (7188.6, 25267.1, 3950.0), (7188.6, 25267.1, 0.0), (7340.9, 25267.1, 0.0), (7340.9, 25267.1, 3950.0), (7340.9, 18967.3, 0.0), (7340.9, 18967.3, 3950.0), (8140.6, 18967.3, 0.0), (8140.6, 18967.3, 3950.0), (8140.6, 18865.7, 0.0), (8140.6, 18865.7, 3950.0), (8140.0, 18865.7, 0.0), (8140.0, 18865.7, 3950.0)], [[1, 2, 3], [1, 3, 4], [1, 4, 5], [6, 1, 5], [7, 6, 5], [7, 5, 8], [9, 7, 8], [10, 7, 9], [11, 10, 9], [11, 9, 12], [13, 11, 12], [13, 12, 14], [15, 13, 14], [15, 14, 16], [17, 15, 16], [17, 16, 18], [19, 17, 18], [19, 18, 20], [19, 20, 3], [2, 19, 3], [15, 17, 19], [1, 19, 2], [6, 19, 1], [13, 15, 19], [13, 19, 6], [7, 13, 6], [10, 11, 13], [10, 13, 7], [18, 16, 20], [20, 4, 3], [20, 5, 4], [16, 14, 20], [20, 14, 5], [14, 8, 5], [12, 9, 14], [14, 9, 8]], closed=True),
])
wall_15_placement = place(storey_placement, origin())
element("IfcWall", 26, at=wall_15_placement, inside=storey, Name="F11_Walls_F11_015", context=model_context, shape_type="Tessellation", body=[
    triangles([(13535.2, 17316.1, 0.0), (13535.2, 23019.0, 0.0), (13535.2, 23019.0, 3950.0), (13535.2, 17316.1, 3950.0), (13129.0, 17316.1, 3950.0), (13129.0, 17316.1, 0.0), (13129.0, 23019.0, 0.0), (13129.0, 23019.0, 3950.0)], [[1, 2, 3], [1, 3, 4], [1, 4, 5], [6, 1, 5], [7, 6, 5], [7, 5, 8], [7, 8, 3], [2, 7, 3], [7, 2, 1], [7, 1, 6], [3, 8, 4], [4, 8, 5]], closed=True),
])
wall_16_placement = place(storey_placement, origin())
element("IfcWall", 27, at=wall_16_placement, inside=storey, Name="F11_Walls_F11_016", context=model_context, shape_type="Tessellation", body=[
    triangles([(4789.6, 17671.7, 0.0), (4789.6, 25267.1, 0.0), (4789.6, 25267.1, 3950.0), (4789.6, 17671.7, 3950.0), (4637.3, 17671.7, 0.0), (4637.3, 17671.7, 3950.0), (4637.3, 25267.1, 0.0), (4637.3, 25267.1, 3950.0)], [[1, 2, 3], [1, 3, 4], [5, 1, 4], [5, 4, 6], [7, 5, 6], [7, 6, 8], [2, 7, 8], [2, 8, 3], [7, 2, 1], [7, 1, 5], [3, 8, 4], [4, 8, 6]], closed=True),
])
wall_17_placement = place(storey_placement, origin())
element("IfcWall", 28, at=wall_17_placement, inside=storey, Name="F11_Walls_F11_017", context=model_context, shape_type="Tessellation", body=[
    triangles([(16226.2, 23019.0, 0.0), (16226.2, 23222.2, 0.0), (16226.2, 23222.2, 3950.0), (16226.2, 23019.0, 3950.0), (13535.2, 23019.0, 0.0), (13535.2, 23019.0, 3950.0), (13535.2, 23222.2, 0.0), (13535.2, 23222.2, 3950.0)], [[1, 2, 3], [1, 3, 4], [5, 1, 4], [5, 4, 6], [7, 5, 6], [7, 6, 8], [2, 7, 8], [2, 8, 3], [7, 2, 1], [7, 1, 5], [3, 8, 4], [4, 8, 6]], closed=True),
])
wall_18_placement = place(storey_placement, origin())
element("IfcWall", 29, at=wall_18_placement, inside=storey, Name="F11_Walls_F11_018", context=model_context, shape_type="Tessellation", body=[
    triangles([(9638.4, 22244.2, 0.0), (9638.4, 24454.2, 0.0), (9638.4, 24454.2, 3950.0), (9638.4, 22244.2, 3950.0), (9486.1, 22244.2, 0.0), (9486.1, 22244.2, 3950.0), (9486.1, 24454.2, 0.0), (9486.1, 24454.2, 3950.0)], [[1, 2, 3], [1, 3, 4], [5, 1, 4], [5, 4, 6], [7, 5, 6], [7, 6, 8], [2, 7, 8], [2, 8, 3], [7, 2, 1], [7, 1, 5], [3, 8, 4], [4, 8, 6]], closed=True),
])
wall_19_placement = place(storey_placement, origin())
element("IfcWall", 30, at=wall_19_placement, inside=storey, Name="F11_Walls_F11_020", context=model_context, shape_type="Tessellation", body=[
    triangles([(16226.2, 25025.8, 0.0), (16226.2, 23222.2, 0.0), (16226.2, 23222.2, 3950.0), (16226.2, 25025.8, 3950.0), (16429.3, 25025.8, 0.0), (16429.3, 25025.8, 3950.0), (16429.3, 23222.2, 0.0), (16429.3, 23222.2, 3950.0)], [[1, 2, 3], [1, 3, 4], [5, 1, 4], [5, 4, 6], [7, 5, 6], [7, 6, 8], [2, 7, 8], [2, 8, 3], [1, 5, 7], [1, 7, 2], [6, 4, 8], [8, 4, 3]], closed=True),
])
wall_20_placement = place(storey_placement, origin())
element("IfcWall", 31, at=wall_20_placement, inside=storey, Name="F11_Walls_F11_021", context=model_context, shape_type="Tessellation", body=[
    triangles([(13535.2, 24276.4, 0.0), (13535.2, 25025.8, 0.0), (13535.2, 25025.8, 3950.0), (13535.2, 24276.4, 3950.0), (13129.0, 24276.4, 3950.0), (13129.0, 24276.4, 0.0), (13129.0, 25025.8, 0.0), (13129.0, 25025.8, 3950.0)], [[1, 2, 3], [1, 3, 4], [1, 4, 5], [6, 1, 5], [7, 6, 5], [7, 5, 8], [7, 8, 3], [2, 7, 3], [2, 1, 6], [7, 2, 6], [4, 3, 5], [3, 8, 5]], closed=True),
])
wall_21_placement = place(storey_placement, origin())
element("IfcWall", 32, at=wall_21_placement, inside=storey, Name="F11_Walls_F11_022", context=model_context, shape_type="Tessellation", body=[
    triangles([(13535.2, 25419.5, 0.0), (13535.2, 25025.8, 0.0), (13535.2, 25025.8, 3950.0), (13535.2, 25419.5, 3950.0), (16226.2, 25419.5, 0.0), (16226.2, 25419.5, 3950.0), (16226.2, 25025.8, 0.0), (16226.2, 25025.8, 3950.0)], [[1, 2, 3], [1, 3, 4], [5, 1, 4], [5, 4, 6], [7, 5, 6], [7, 6, 8], [2, 7, 8], [2, 8, 3], [2, 5, 7], [1, 5, 2], [6, 3, 8], [6, 4, 3]], closed=True),
])
wall_22_placement = place(storey_placement, origin())
element("IfcWall", 33, at=wall_22_placement, inside=storey, Name="F11_Walls_F11_024", context=model_context, shape_type="Tessellation", body=[
    triangles([(31623.1, 17316.1, 0.0), (31623.1, 17316.1, 3950.0), (31623.1, 16922.4, 3950.0), (31623.1, 16922.4, 0.0), (29224.0, 16922.4, 0.0), (29224.0, 16922.4, 3950.0), (29224.0, 17316.1, 3950.0), (29224.0, 17316.1, 0.0)], [[1, 2, 3], [4, 1, 3], [5, 4, 3], [5, 3, 6], [5, 6, 7], [8, 5, 7], [1, 8, 7], [1, 7, 2], [8, 1, 4], [8, 4, 5], [2, 7, 3], [3, 7, 6]], closed=True),
])
wall_23_placement = place(storey_placement, origin())
element("IfcWall", 34, at=wall_23_placement, inside=storey, Name="F11_Walls_F11_025", context=model_context, shape_type="Tessellation", body=[
    triangles([(24730.6, 17316.1, 0.0), (24730.6, 17316.1, 3950.0), (24730.6, 16922.4, 3950.0), (24730.6, 16922.4, 0.0), (22331.6, 16922.4, 0.0), (22331.6, 16922.4, 3950.0), (22331.6, 17316.1, 3950.0), (22331.6, 17316.1, 0.0)], [[1, 2, 3], [4, 1, 3], [5, 4, 3], [5, 3, 6], [5, 6, 7], [8, 5, 7], [1, 8, 7], [1, 7, 2], [8, 1, 4], [8, 4, 5], [2, 7, 3], [3, 7, 6]], closed=True),
])
wall_24_placement = place(storey_placement, origin())
element("IfcWall", 35, at=wall_24_placement, inside=storey, Name="F11_Walls_F11_027", context=model_context, shape_type="Tessellation", body=[
    triangles([(29224.0, 17875.0, 0.0), (29224.0, 17875.0, 3950.0), (29224.0, 17316.1, 3950.0), (29224.0, 17316.1, 0.0), (29020.9, 17316.1, 0.0), (29020.9, 17316.1, 3950.0), (29020.9, 17875.0, 3950.0), (29020.9, 17875.0, 0.0)], [[1, 2, 3], [4, 1, 3], [5, 4, 3], [5, 3, 6], [5, 6, 7], [8, 5, 7], [1, 8, 7], [1, 7, 2], [8, 1, 4], [8, 4, 5], [2, 7, 3], [3, 7, 6]], closed=True),
])
wall_25_placement = place(storey_placement, origin())
element("IfcWall", 36, at=wall_25_placement, inside=storey, Name="F11_Walls_F11_028", context=model_context, shape_type="Tessellation", body=[
    triangles([(24921.0, 17875.0, 0.0), (24921.0, 17875.0, 3950.0), (24921.0, 17316.1, 3950.0), (24921.0, 17316.1, 0.0), (24730.6, 17316.1, 0.0), (24730.6, 17316.1, 3950.0), (24730.6, 17875.0, 3950.0), (24730.6, 17875.0, 0.0)], [[1, 2, 3], [4, 1, 3], [5, 4, 3], [5, 3, 6], [5, 6, 7], [8, 5, 7], [1, 8, 7], [1, 7, 2], [8, 1, 4], [8, 4, 5], [2, 7, 3], [3, 7, 6]], closed=True),
])
wall_26_placement = place(storey_placement, origin())
element("IfcWall", 37, at=wall_26_placement, inside=storey, Name="F11_Walls_F11_029", context=model_context, shape_type="Tessellation", body=[
    triangles([(22331.6, 17316.1, 0.0), (22331.6, 19246.7, 0.0), (22331.6, 19246.7, 3950.0), (22331.6, 17316.1, 3950.0), (22128.5, 17316.1, 0.0), (22128.5, 17316.1, 3950.0), (22128.5, 19246.7, 0.0), (22128.5, 19246.7, 3950.0)], [[1, 2, 3], [1, 3, 4], [5, 1, 4], [5, 4, 6], [7, 5, 6], [7, 6, 8], [2, 7, 8], [2, 8, 3], [7, 2, 1], [7, 1, 5], [3, 8, 4], [4, 8, 6]], closed=True),
])
wall_27_placement = place(storey_placement, origin())
element("IfcWall", 38, at=wall_27_placement, inside=storey, Name="F11_Walls_F11_031", context=model_context, shape_type="Tessellation", body=[
    triangles([(19374.1, 19449.9, 0.0), (19374.1, 19449.9, 3950.0), (19577.2, 19449.9, 3950.0), (19577.2, 19449.9, 0.0), (19577.2, 19246.7, 0.0), (19577.2, 19246.7, 3950.0), (19374.1, 19246.7, 3950.0), (19374.1, 19246.7, 0.0)], [[1, 2, 3], [4, 1, 3], [5, 4, 3], [5, 3, 6], [5, 6, 7], [8, 5, 7], [1, 8, 7], [1, 7, 2], [1, 4, 5], [1, 5, 8], [3, 2, 6], [6, 2, 7]], closed=True),
])
wall_28_placement = place(storey_placement, origin())
element("IfcWall", 39, at=wall_28_placement, inside=storey, Name="F11_Walls_F11_032", context=model_context, shape_type="Tessellation", body=[
    triangles([(21366.9, 21024.9, 0.0), (21366.9, 19449.9, 0.0), (21366.9, 19449.9, 3950.0), (21366.9, 21024.9, 3950.0), (21519.3, 21024.9, 0.0), (21519.3, 21024.9, 3950.0), (21519.3, 19449.9, 0.0), (21519.3, 19449.9, 3950.0), (22128.5, 19449.9, 0.0), (22128.5, 19449.9, 3950.0), (22128.5, 19246.7, 0.0), (22128.5, 19246.7, 3950.0), (20694.2, 19246.7, 0.0), (20694.2, 19246.7, 3950.0), (20694.2, 19449.9, 0.0), (20694.2, 19449.9, 3950.0)], [[1, 2, 3], [1, 3, 4], [5, 1, 4], [5, 4, 6], [7, 5, 6], [7, 6, 8], [9, 7, 8], [9, 8, 10], [11, 9, 10], [11, 10, 12], [13, 11, 12], [13, 12, 14], [15, 13, 14], [15, 14, 16], [2, 15, 16], [2, 16, 3], [7, 9, 11], [2, 7, 11], [13, 2, 11], [15, 2, 13], [1, 5, 7], [1, 7, 2], [10, 8, 12], [8, 3, 12], [3, 14, 12], [3, 16, 14], [6, 4, 8], [8, 4, 3]], closed=True),
])
wall_29_placement = place(storey_placement, origin())
element("IfcWall", 40, at=wall_29_placement, inside=storey, Name="F11_Walls_F11_037", context=model_context, shape_type="Tessellation", body=[
    triangles([(19374.1, 19449.9, 0.0), (19374.1, 22574.4, 0.0), (19374.1, 22574.4, 3950.0), (19374.1, 19449.9, 3950.0), (19183.7, 19449.9, 0.0), (19183.7, 19449.9, 3950.0), (19183.7, 22574.4, 0.0), (19183.7, 22574.4, 3950.0)], [[1, 2, 3], [1, 3, 4], [5, 1, 4], [5, 4, 6], [7, 5, 6], [7, 6, 8], [2, 7, 8], [2, 8, 3], [2, 1, 5], [7, 2, 5], [4, 3, 6], [3, 8, 6]], closed=True),
])
wall_30_placement = place(storey_placement, origin())
element("IfcWall", 41, at=wall_30_placement, inside=storey, Name="F11_Walls_F11_038", context=model_context, shape_type="Tessellation", body=[
    triangles([(22331.6, 19449.9, 0.0), (22331.6, 22574.4, 0.0), (22331.6, 22574.4, 3950.0), (22331.6, 19449.9, 3950.0), (22128.5, 19449.9, 0.0), (22128.5, 19449.9, 3950.0), (22128.5, 22574.4, 0.0), (22128.5, 22574.4, 3950.0)], [[1, 2, 3], [1, 3, 4], [5, 1, 4], [5, 4, 6], [7, 5, 6], [7, 6, 8], [2, 7, 8], [2, 8, 3], [2, 1, 5], [7, 2, 5], [4, 3, 6], [3, 8, 6]], closed=True),
])

save(model, "model.ifc")
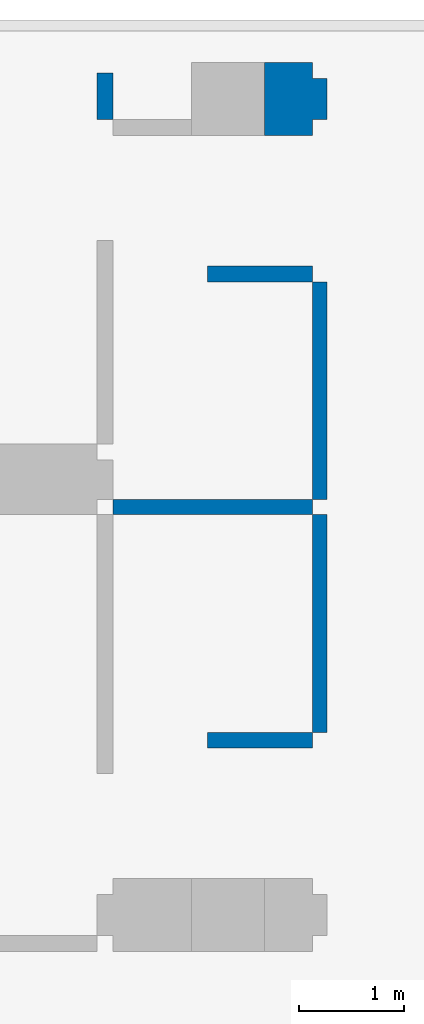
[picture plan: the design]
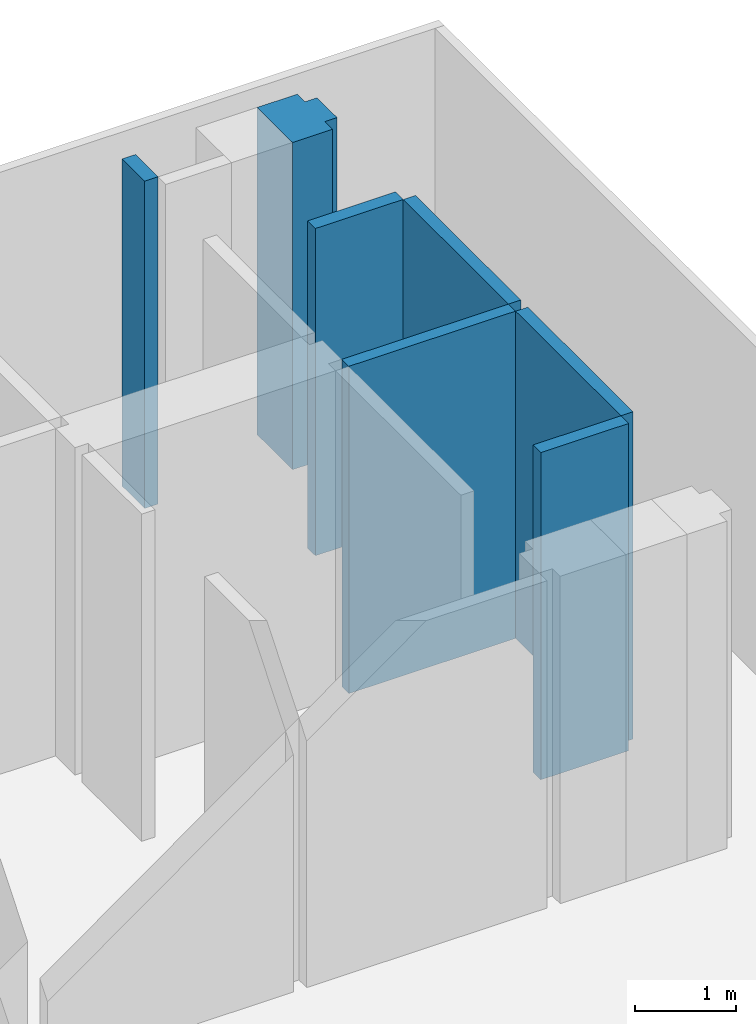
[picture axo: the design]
# One storey, part 3 of 4: 7 walls.
"""IFC4 building model written with IfcOpenShell, lengths in millimetres."""

from ifc_helpers import new_model, si_unit, frame, origin, place, context, project, spatial, triangles, element, save


model = new_model("IFC4")

# Units and contexts
model_context = context("Model", 3, precision=0.001, world=origin())
ifc_project = project(units=[si_unit("LENGTHUNIT", "METRE", prefix="MILLI"), si_unit("AREAUNIT", "SQUARE_METRE"), si_unit("VOLUMEUNIT", "CUBIC_METRE")], contexts=[model_context])

# Site, building, storey
site_placement = place(None, origin())
site = spatial("IfcSite", under=ifc_project, at=site_placement, CompositionType="ELEMENT")
building_placement = place(site_placement, origin())
building = spatial("IfcBuilding", under=site, at=building_placement, CompositionType="ELEMENT")
storey_placement = place(building_placement, frame((0.0, 0.0, 51200.0)))
storey = spatial("IfcBuildingStorey", under=building, at=storey_placement, Name="F12", CompositionType="ELEMENT", Elevation=51200.0)

# Walls
wall_1_placement = place(storey_placement, origin())
element("IfcWall", 1, at=wall_1_placement, inside=storey, Name="F12_Walls_F12_072", context=model_context, shape_type="Tessellation", body=[
    triangles([(48568.5, 18865.7, 0.0), (48568.5, 19018.1, 0.0), (48568.5, 19018.1, 3950.0), (48568.5, 18865.7, 3950.0), (47565.8, 18865.7, 0.0), (47565.8, 18865.7, 3950.0), (47565.8, 19018.1, 0.0), (47565.8, 19018.1, 3950.0)], [[1, 2, 3], [1, 3, 4], [5, 1, 4], [5, 4, 6], [7, 5, 6], [7, 6, 8], [2, 7, 8], [2, 8, 3], [7, 2, 1], [7, 1, 5], [3, 8, 4], [4, 8, 6]], closed=True),
])
wall_2_placement = place(storey_placement, origin())
element("IfcWall", 2, at=wall_2_placement, inside=storey, Name="F12_Walls_F12_074", context=model_context, shape_type="Tessellation", body=[
    triangles([(48708.1, 19018.1, 0.0), (48708.1, 21101.1, 0.0), (48708.1, 21101.1, 3950.0), (48708.1, 19018.1, 3950.0), (48568.5, 19018.1, 0.0), (48568.5, 19018.1, 3950.0), (48568.5, 21101.1, 0.0), (48568.5, 21101.1, 3950.0)], [[1, 2, 3], [1, 3, 4], [5, 1, 4], [5, 4, 6], [7, 5, 6], [7, 6, 8], [2, 7, 8], [2, 8, 3], [7, 2, 1], [7, 1, 5], [3, 8, 4], [4, 8, 6]], closed=True),
])
wall_3_placement = place(storey_placement, origin())
element("IfcWall", 3, at=wall_3_placement, inside=storey, Name="F12_Walls_F12_077", context=model_context, shape_type="Tessellation", body=[
    triangles([(48568.5, 21240.8, 0.0), (48568.5, 21240.8, 3950.0), (48568.5, 21101.1, 3950.0), (48568.5, 21101.1, 0.0), (46664.5, 21101.1, 3950.0), (46664.5, 21101.1, 0.0), (46664.5, 21240.8, 3950.0), (46664.5, 21240.8, 0.0)], [[1, 2, 3], [4, 1, 3], [4, 3, 5], [6, 4, 5], [6, 5, 7], [8, 6, 7], [8, 7, 2], [1, 8, 2], [8, 1, 4], [8, 4, 6], [2, 7, 3], [3, 7, 5]], closed=True),
])
wall_4_placement = place(storey_placement, origin())
element("IfcWall", 4, at=wall_4_placement, inside=storey, Name="F12_Walls_F12_078", context=model_context, shape_type="Tessellation", body=[
    triangles([(48708.1, 21240.8, 0.0), (48708.1, 23323.8, 0.0), (48708.1, 23323.8, 3950.0), (48708.1, 21240.8, 3950.0), (48568.5, 21240.8, 0.0), (48568.5, 21240.8, 3950.0), (48568.5, 23323.8, 0.0), (48568.5, 23323.8, 3950.0)], [[1, 2, 3], [1, 3, 4], [5, 1, 4], [5, 4, 6], [7, 5, 6], [7, 6, 8], [2, 7, 8], [2, 8, 3], [7, 2, 1], [7, 1, 5], [3, 8, 4], [4, 8, 6]], closed=True),
])
wall_5_placement = place(storey_placement, origin())
element("IfcWall", 5, at=wall_5_placement, inside=storey, Name="F12_Walls_F12_081", context=model_context, shape_type="Tessellation", body=[
    triangles([(48568.5, 23323.8, 0.0), (48568.5, 23476.2, 0.0), (48568.5, 23476.2, 3950.0), (48568.5, 23323.8, 3950.0), (47565.8, 23323.8, 0.0), (47565.8, 23323.8, 3950.0), (47565.8, 23476.2, 0.0), (47565.8, 23476.2, 3950.0)], [[1, 2, 3], [1, 3, 4], [5, 1, 4], [5, 4, 6], [7, 5, 6], [7, 6, 8], [2, 7, 8], [2, 8, 3], [7, 2, 1], [7, 1, 5], [3, 8, 4], [4, 8, 6]], closed=True),
])
wall_6_placement = place(storey_placement, origin())
element("IfcWall", 6, at=wall_6_placement, inside=storey, Name="F12_Walls_F12_083", context=model_context, shape_type="Tessellation", body=[
    triangles([(48568.5, 25419.5, 0.0), (48111.6, 25419.5, 0.0), (48111.6, 25419.5, 3950.0), (48568.5, 25419.5, 3950.0), (48568.5, 25267.1, 0.0), (48568.5, 25267.1, 3950.0), (48708.1, 25267.1, 0.0), (48708.1, 25267.1, 3950.0), (48708.1, 24873.4, 3950.0), (48708.1, 24873.4, 0.0), (48568.5, 24873.4, 0.0), (48568.5, 24873.4, 3950.0), (48568.5, 24721.0, 0.0), (48568.5, 24721.0, 3950.0), (48111.6, 24721.0, 0.0), (48111.6, 24721.0, 3950.0), (48111.6, 24873.4, 0.0), (48111.6, 24873.4, 3950.0), (48111.6, 25267.1, 3950.0), (48111.6, 25267.1, 0.0)], [[1, 2, 3], [1, 3, 4], [5, 1, 4], [5, 4, 6], [7, 5, 6], [7, 6, 8], [7, 8, 9], [10, 7, 9], [11, 10, 9], [11, 9, 12], [13, 11, 12], [13, 12, 14], [15, 13, 14], [15, 14, 16], [17, 15, 16], [17, 16, 18], [17, 18, 19], [20, 17, 19], [2, 20, 19], [2, 19, 3], [7, 10, 11], [5, 7, 11], [17, 11, 13], [17, 13, 15], [20, 11, 17], [20, 5, 11], [2, 1, 5], [2, 5, 20], [9, 8, 12], [8, 6, 12], [12, 18, 14], [14, 18, 16], [12, 19, 18], [6, 19, 12], [4, 3, 6], [6, 3, 19]], closed=True),
])
wall_7_placement = place(storey_placement, origin())
element("IfcWall", 7, at=wall_7_placement, inside=storey, Name="F12_Walls_F12_084", context=model_context, shape_type="Tessellation", body=[
    triangles([(46512.2, 24873.4, 0.0), (46664.5, 24873.4, 0.0), (46664.5, 24873.4, 3950.0), (46512.2, 24873.4, 3950.0), (46512.2, 25317.9, 0.0), (46512.2, 25317.9, 3950.0), (46664.5, 25317.9, 0.0), (46664.5, 25317.9, 3950.0)], [[1, 2, 3], [1, 3, 4], [5, 1, 4], [5, 4, 6], [7, 5, 6], [7, 6, 8], [2, 7, 8], [2, 8, 3], [5, 2, 1], [5, 7, 2], [3, 6, 4], [8, 6, 3]], closed=True),
])

save(model, "model.ifc")
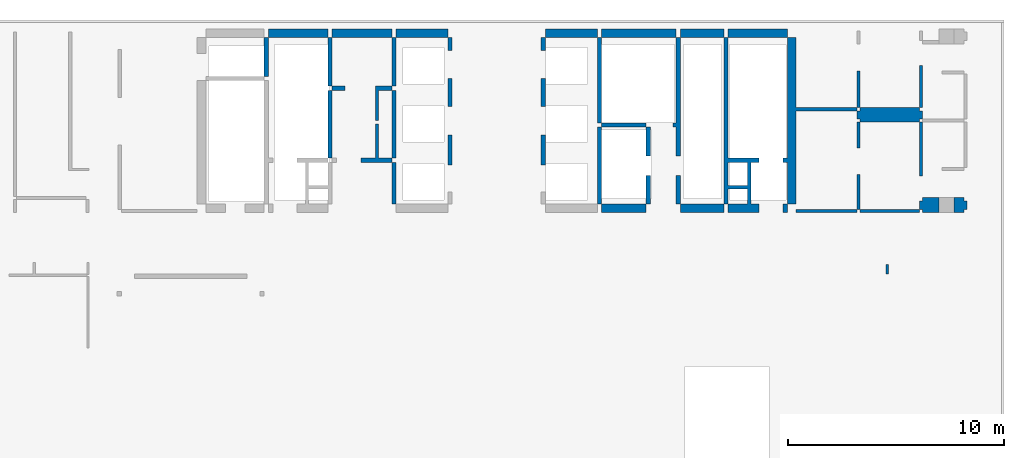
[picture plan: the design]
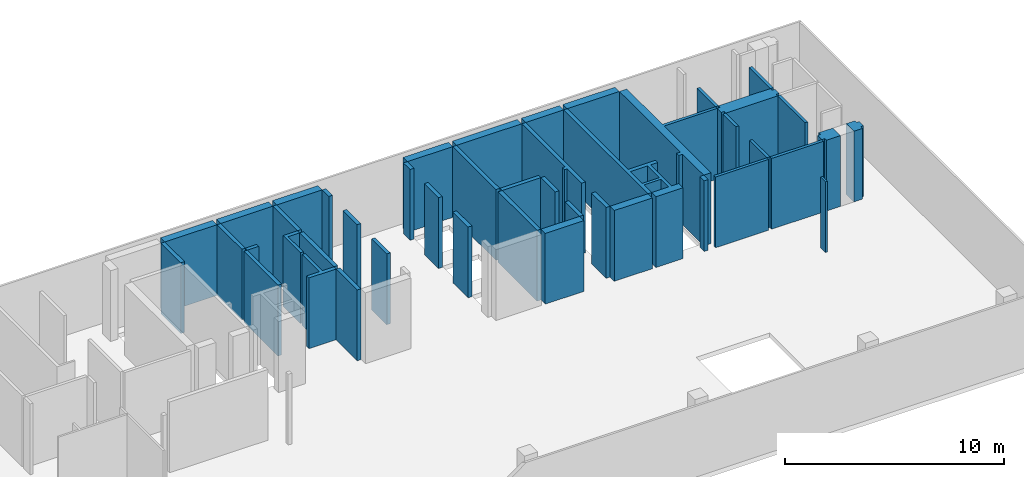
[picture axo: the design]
# One storey, part 2 of 4: 45 walls.
"""IFC4 building model written with IfcOpenShell, lengths in millimetres."""

from ifc_helpers import new_model, si_unit, frame, origin, place, context, project, spatial, triangles, element, save


model = new_model("IFC4")

# Units and contexts
model_context = context("Model", 3, precision=0.001, world=origin())
ifc_project = project(units=[si_unit("LENGTHUNIT", "METRE", prefix="MILLI"), si_unit("AREAUNIT", "SQUARE_METRE"), si_unit("VOLUMEUNIT", "CUBIC_METRE")], contexts=[model_context])

# Site, building, storey
site_placement = place(None, origin())
site = spatial("IfcSite", under=ifc_project, at=site_placement, CompositionType="ELEMENT")
building_placement = place(site_placement, origin())
building = spatial("IfcBuilding", under=site, at=building_placement, CompositionType="ELEMENT")
storey_placement = place(building_placement, frame((0.0, 0.0, 68000.0)))
storey = spatial("IfcBuildingStorey", under=building, at=storey_placement, Name="F16", CompositionType="ELEMENT", Elevation=68000.0)

# Walls
wall_1_placement = place(storey_placement, origin())
element("IfcWall", 1, at=wall_1_placement, inside=storey, Name="F16_Walls_F16_022", context=model_context, shape_type="Tessellation", body=[
    triangles([(16226.2, 25025.8, 0.0), (16226.2, 23222.2, 0.0), (16226.2, 23222.2, 3950.0), (16226.2, 25025.8, 3950.0), (16429.3, 25025.8, 0.0), (16429.3, 25025.8, 3950.0), (16429.3, 23222.2, 0.0), (16429.3, 23222.2, 3950.0)], [[1, 2, 3], [1, 3, 4], [5, 1, 4], [5, 4, 6], [7, 5, 6], [7, 6, 8], [2, 7, 8], [2, 8, 3], [1, 5, 7], [1, 7, 2], [6, 4, 8], [8, 4, 3]], closed=True),
])
wall_2_placement = place(storey_placement, origin())
element("IfcWall", 2, at=wall_2_placement, inside=storey, Name="F16_Walls_F16_025", context=model_context, shape_type="Tessellation", body=[
    triangles([(19183.7, 25025.8, 0.0), (19183.7, 25419.5, 0.0), (19183.7, 25419.5, 3950.0), (19183.7, 25025.8, 3950.0), (16429.3, 25025.8, 0.0), (16429.3, 25025.8, 3950.0), (16429.3, 25419.5, 0.0), (16429.3, 25419.5, 3950.0)], [[1, 2, 3], [1, 3, 4], [5, 1, 4], [5, 4, 6], [7, 5, 6], [7, 6, 8], [2, 7, 8], [2, 8, 3], [7, 2, 1], [7, 1, 5], [3, 8, 4], [4, 8, 6]], closed=True),
])
wall_3_placement = place(storey_placement, origin())
element("IfcWall", 3, at=wall_3_placement, inside=storey, Name="F16_Walls_F16_030", context=model_context, shape_type="Tessellation", body=[
    triangles([(22331.6, 17316.1, 0.0), (22331.6, 19246.7, 0.0), (22331.6, 19246.7, 3950.0), (22331.6, 17316.1, 3950.0), (22128.5, 17316.1, 0.0), (22128.5, 17316.1, 3950.0), (22128.5, 19246.7, 0.0), (22128.5, 19246.7, 3950.0)], [[1, 2, 3], [1, 3, 4], [5, 1, 4], [5, 4, 6], [7, 5, 6], [7, 6, 8], [2, 7, 8], [2, 8, 3], [7, 2, 1], [7, 1, 5], [3, 8, 4], [4, 8, 6]], closed=True),
])
wall_4_placement = place(storey_placement, origin())
element("IfcWall", 4, at=wall_4_placement, inside=storey, Name="F16_Walls_F16_031", context=model_context, shape_type="Tessellation", body=[
    triangles([(31826.2, 20872.5, 0.0), (31826.2, 20872.5, 3950.0), (31826.2, 17316.1, 3950.0), (31826.2, 17316.1, 0.0), (31623.1, 17316.1, 3950.0), (31623.1, 17316.1, 0.0), (31623.1, 20872.5, 3950.0), (31623.1, 20872.5, 0.0)], [[1, 2, 3], [4, 1, 3], [4, 3, 5], [6, 4, 5], [6, 5, 7], [8, 6, 7], [8, 7, 2], [1, 8, 2], [8, 1, 4], [8, 4, 6], [2, 7, 3], [3, 7, 5]], closed=True),
])
wall_5_placement = place(storey_placement, origin())
element("IfcWall", 5, at=wall_5_placement, inside=storey, Name="F16_Walls_F16_033", context=model_context, shape_type="Tessellation", body=[
    triangles([(21366.9, 21024.9, 0.0), (21366.9, 19449.9, 0.0), (21366.9, 19449.9, 3950.0), (21366.9, 21024.9, 3950.0), (21519.3, 21024.9, 0.0), (21519.3, 21024.9, 3950.0), (21519.3, 19449.9, 0.0), (21519.3, 19449.9, 3950.0), (22128.5, 19449.9, 0.0), (22128.5, 19449.9, 3950.0), (22128.5, 19246.7, 0.0), (22128.5, 19246.7, 3950.0), (20694.2, 19246.7, 0.0), (20694.2, 19246.7, 3950.0), (20694.2, 19449.9, 0.0), (20694.2, 19449.9, 3950.0)], [[1, 2, 3], [1, 3, 4], [5, 1, 4], [5, 4, 6], [7, 5, 6], [7, 6, 8], [9, 7, 8], [9, 8, 10], [11, 9, 10], [11, 10, 12], [13, 11, 12], [13, 12, 14], [15, 13, 14], [15, 14, 16], [2, 15, 16], [2, 16, 3], [7, 9, 11], [2, 7, 11], [13, 2, 11], [15, 2, 13], [1, 5, 7], [1, 7, 2], [10, 8, 12], [8, 3, 12], [3, 14, 12], [3, 16, 14], [6, 4, 8], [8, 4, 3]], closed=True),
])
wall_6_placement = place(storey_placement, origin())
element("IfcWall", 6, at=wall_6_placement, inside=storey, Name="F16_Walls_F16_034", context=model_context, shape_type="Tessellation", body=[
    triangles([(24921.0, 19119.7, 0.0), (24921.0, 20516.8, 0.0), (24921.0, 20516.8, 3950.0), (24921.0, 19119.7, 3950.0), (24730.6, 19119.7, 0.0), (24730.6, 19119.7, 3950.0), (24730.6, 19120.0, 0.0), (24730.6, 19120.0, 3950.0), (24730.0, 19120.0, 0.0), (24730.0, 19120.0, 3950.0), (24730.0, 20515.0, 0.0), (24730.0, 20515.0, 3950.0), (24730.6, 20515.0, 0.0), (24730.6, 20515.0, 3950.0), (24730.6, 20516.8, 3950.0), (24730.6, 20516.8, 0.0)], [[1, 2, 3], [1, 3, 4], [5, 1, 4], [5, 4, 6], [7, 5, 6], [7, 6, 8], [9, 7, 8], [9, 8, 10], [11, 9, 10], [11, 10, 12], [13, 11, 12], [13, 12, 14], [13, 14, 15], [16, 13, 15], [2, 16, 15], [2, 15, 3], [7, 1, 5], [13, 2, 1], [13, 1, 7], [11, 7, 9], [11, 13, 7], [16, 2, 13], [4, 8, 6], [3, 14, 4], [4, 14, 8], [8, 12, 10], [14, 12, 8], [3, 15, 14]], closed=True),
])
wall_7_placement = place(storey_placement, origin())
element("IfcWall", 7, at=wall_7_placement, inside=storey, Name="F16_Walls_F16_035", context=model_context, shape_type="Tessellation", body=[
    triangles([(29224.0, 20516.8, 0.0), (29224.0, 20516.8, 3950.0), (29224.0, 20515.0, 3950.0), (29224.0, 20515.0, 0.0), (29225.0, 20515.0, 0.0), (29225.0, 20515.0, 3950.0), (29225.0, 19120.0, 0.0), (29225.0, 19120.0, 3950.0), (29224.0, 19120.0, 0.0), (29224.0, 19120.0, 3950.0), (29224.0, 19119.7, 0.0), (29224.0, 19119.7, 3950.0), (29020.9, 19119.7, 0.0), (29020.9, 19119.7, 3950.0), (29020.9, 19120.0, 0.0), (29020.9, 19120.0, 3950.0), (29020.0, 19120.0, 0.0), (29020.0, 19120.0, 3950.0), (29020.0, 20515.0, 0.0), (29020.0, 20515.0, 3950.0), (29020.9, 20515.0, 0.0), (29020.9, 20515.0, 3950.0), (29020.9, 20516.8, 3950.0), (29020.9, 20516.8, 0.0)], [[1, 2, 3], [4, 1, 3], [5, 4, 3], [5, 3, 6], [7, 5, 6], [7, 6, 8], [9, 7, 8], [9, 8, 10], [11, 9, 10], [11, 10, 12], [13, 11, 12], [13, 12, 14], [15, 13, 14], [15, 14, 16], [17, 15, 16], [17, 16, 18], [19, 17, 18], [19, 18, 20], [21, 19, 20], [21, 20, 22], [21, 22, 23], [24, 21, 23], [1, 24, 23], [1, 23, 2], [15, 9, 11], [15, 11, 13], [4, 5, 7], [4, 7, 9], [4, 9, 15], [21, 4, 15], [19, 15, 17], [19, 21, 15], [24, 1, 4], [24, 4, 21], [10, 16, 12], [12, 16, 14], [6, 3, 8], [8, 3, 10], [10, 3, 16], [3, 22, 16], [16, 20, 18], [22, 20, 16], [2, 23, 3], [3, 23, 22]], closed=True),
])
wall_8_placement = place(storey_placement, origin())
element("IfcWall", 8, at=wall_8_placement, inside=storey, Name="F16_Walls_F16_036", context=model_context, shape_type="Tessellation", body=[
    triangles([(19374.1, 19449.9, 0.0), (19374.1, 22574.4, 0.0), (19374.1, 22574.4, 3950.0), (19374.1, 19449.9, 3950.0), (19183.7, 19449.9, 0.0), (19183.7, 19449.9, 3950.0), (19183.7, 22574.4, 0.0), (19183.7, 22574.4, 3950.0)], [[1, 2, 3], [1, 3, 4], [5, 1, 4], [5, 4, 6], [7, 5, 6], [7, 6, 8], [2, 7, 8], [2, 8, 3], [2, 1, 5], [7, 2, 5], [4, 3, 6], [3, 8, 6]], closed=True),
])
wall_9_placement = place(storey_placement, origin())
element("IfcWall", 9, at=wall_9_placement, inside=storey, Name="F16_Walls_F16_037", context=model_context, shape_type="Tessellation", body=[
    triangles([(22331.6, 19449.9, 0.0), (22331.6, 22574.4, 0.0), (22331.6, 22574.4, 3950.0), (22331.6, 19449.9, 3950.0), (22128.5, 19449.9, 0.0), (22128.5, 19449.9, 3950.0), (22128.5, 22574.4, 0.0), (22128.5, 22574.4, 3950.0)], [[1, 2, 3], [1, 3, 4], [5, 1, 4], [5, 4, 6], [7, 5, 6], [7, 6, 8], [2, 7, 8], [2, 8, 3], [2, 1, 5], [7, 2, 5], [4, 3, 6], [3, 8, 6]], closed=True),
])
wall_10_placement = place(storey_placement, origin())
element("IfcWall", 10, at=wall_10_placement, inside=storey, Name="F16_Walls_F16_038", context=model_context, shape_type="Tessellation", body=[
    triangles([(22128.5, 22765.0, 0.0), (21366.9, 22765.0, 0.0), (21366.9, 22765.0, 3950.0), (22128.5, 22765.0, 3950.0), (22128.5, 22574.4, 3950.0), (22128.5, 22574.4, 0.0), (21519.3, 22574.4, 0.0), (21519.3, 22574.4, 3950.0), (21519.3, 21177.3, 0.0), (21519.3, 21177.3, 3950.0), (21366.9, 21177.3, 0.0), (21366.9, 21177.3, 3950.0), (21366.9, 22574.4, 0.0), (21366.9, 22574.4, 3950.0)], [[1, 2, 3], [1, 3, 4], [1, 4, 5], [6, 1, 5], [7, 6, 5], [7, 5, 8], [9, 7, 8], [9, 8, 10], [11, 9, 10], [11, 10, 12], [13, 11, 12], [13, 12, 14], [13, 14, 3], [2, 13, 3], [7, 1, 6], [13, 7, 9], [13, 9, 11], [2, 1, 7], [2, 7, 13], [4, 8, 5], [8, 14, 10], [10, 14, 12], [4, 3, 8], [8, 3, 14]], closed=True),
])
wall_11_placement = place(storey_placement, origin())
element("IfcWall", 11, at=wall_11_placement, inside=storey, Name="F16_Walls_F16_039", context=model_context, shape_type="Tessellation", body=[
    triangles([(24730.6, 23120.6, 0.0), (24730.6, 23120.0, 0.0), (24730.6, 23120.0, 3950.0), (24730.6, 23120.6, 3950.0), (24921.0, 23120.6, 0.0), (24921.0, 23120.6, 3950.0), (24921.0, 21825.1, 0.0), (24921.0, 21825.1, 3950.0), (24920.0, 21825.1, 0.0), (24920.0, 21825.1, 3950.0), (24920.0, 21825.0, 0.0), (24920.0, 21825.0, 3950.0), (24730.0, 21825.0, 0.0), (24730.0, 21825.0, 3950.0), (24730.0, 23120.0, 3950.0), (24730.0, 23120.0, 0.0)], [[1, 2, 3], [1, 3, 4], [5, 1, 4], [5, 4, 6], [7, 5, 6], [7, 6, 8], [9, 7, 8], [9, 8, 10], [11, 9, 10], [11, 10, 12], [13, 11, 12], [13, 12, 14], [13, 14, 15], [16, 13, 15], [2, 16, 15], [2, 15, 3], [13, 9, 11], [5, 7, 9], [2, 5, 9], [2, 9, 13], [1, 5, 2], [16, 2, 13], [10, 14, 12], [8, 6, 10], [6, 3, 10], [10, 3, 14], [6, 4, 3], [3, 15, 14]], closed=True),
])
wall_12_placement = place(storey_placement, origin())
element("IfcWall", 12, at=wall_12_placement, inside=storey, Name="F16_Walls_F16_040", context=model_context, shape_type="Tessellation", body=[
    triangles([(29020.9, 23120.6, 0.0), (29020.9, 23120.0, 0.0), (29020.9, 23120.0, 3950.0), (29020.9, 23120.6, 3950.0), (29224.0, 23120.6, 0.0), (29224.0, 23120.6, 3950.0), (29224.0, 23120.0, 0.0), (29224.0, 23120.0, 3950.0), (29225.0, 23120.0, 0.0), (29225.0, 23120.0, 3950.0), (29225.0, 21825.0, 3950.0), (29225.0, 21825.0, 0.0), (29020.0, 21825.0, 0.0), (29020.0, 21825.0, 3950.0), (29020.0, 23120.0, 3950.0), (29020.0, 23120.0, 0.0)], [[1, 2, 3], [1, 3, 4], [5, 1, 4], [5, 4, 6], [7, 5, 6], [7, 6, 8], [9, 7, 8], [9, 8, 10], [9, 10, 11], [12, 9, 11], [13, 12, 11], [13, 11, 14], [13, 14, 15], [16, 13, 15], [2, 16, 15], [2, 15, 3], [7, 9, 12], [7, 12, 13], [2, 7, 13], [1, 5, 7], [1, 7, 2], [16, 2, 13], [10, 8, 11], [11, 8, 14], [8, 3, 14], [6, 4, 8], [8, 4, 3], [3, 15, 14]], closed=True),
])
wall_13_placement = place(storey_placement, origin())
element("IfcWall", 13, at=wall_13_placement, inside=storey, Name="F16_Walls_F16_041", context=model_context, shape_type="Tessellation", body=[
    triangles([(19970.7, 22765.0, 0.0), (19970.7, 22765.0, 3950.0), (19970.7, 22574.4, 3950.0), (19970.7, 22574.4, 0.0), (19374.1, 22574.4, 0.0), (19374.1, 22574.4, 3950.0), (19374.1, 22765.0, 3950.0), (19374.1, 22765.0, 0.0)], [[1, 2, 3], [4, 1, 3], [5, 4, 3], [5, 3, 6], [5, 6, 7], [8, 5, 7], [1, 8, 7], [1, 7, 2], [8, 1, 4], [8, 4, 5], [2, 7, 3], [3, 7, 6]], closed=True),
])
wall_14_placement = place(storey_placement, origin())
element("IfcWall", 14, at=wall_14_placement, inside=storey, Name="F16_Walls_F16_042", context=model_context, shape_type="Tessellation", body=[
    triangles([(19374.1, 22765.0, 0.0), (19374.1, 25025.8, 0.0), (19374.1, 25025.8, 3950.0), (19374.1, 22765.0, 3950.0), (19183.7, 22765.0, 0.0), (19183.7, 22765.0, 3950.0), (19183.7, 25025.8, 0.0), (19183.7, 25025.8, 3950.0)], [[1, 2, 3], [1, 3, 4], [5, 1, 4], [5, 4, 6], [7, 5, 6], [7, 6, 8], [2, 7, 8], [2, 8, 3], [7, 2, 1], [7, 1, 5], [3, 8, 4], [4, 8, 6]], closed=True),
])
wall_15_placement = place(storey_placement, origin())
element("IfcWall", 15, at=wall_15_placement, inside=storey, Name="F16_Walls_F16_043", context=model_context, shape_type="Tessellation", body=[
    triangles([(22331.6, 22765.0, 0.0), (22331.6, 25025.8, 0.0), (22331.6, 25025.8, 3950.0), (22331.6, 22765.0, 3950.0), (22128.5, 22765.0, 0.0), (22128.5, 22765.0, 3950.0), (22128.5, 25025.8, 0.0), (22128.5, 25025.8, 3950.0)], [[1, 2, 3], [1, 3, 4], [5, 1, 4], [5, 4, 6], [7, 5, 6], [7, 6, 8], [2, 7, 8], [2, 8, 3], [7, 2, 1], [7, 1, 5], [3, 8, 4], [4, 8, 6]], closed=True),
])
wall_16_placement = place(storey_placement, origin())
element("IfcWall", 16, at=wall_16_placement, inside=storey, Name="F16_Walls_F16_044", context=model_context, shape_type="Tessellation", body=[
    triangles([(24921.0, 24416.1, 0.0), (24921.0, 25025.8, 0.0), (24921.0, 25025.8, 3950.0), (24921.0, 24416.1, 3950.0), (24730.6, 24416.1, 0.0), (24730.6, 24416.1, 3950.0), (24730.6, 25025.8, 0.0), (24730.6, 25025.8, 3950.0)], [[1, 2, 3], [1, 3, 4], [5, 1, 4], [5, 4, 6], [7, 5, 6], [7, 6, 8], [2, 7, 8], [2, 8, 3], [7, 2, 1], [7, 1, 5], [3, 8, 4], [4, 8, 6]], closed=True),
])
wall_17_placement = place(storey_placement, origin())
element("IfcWall", 17, at=wall_17_placement, inside=storey, Name="F16_Walls_F16_045", context=model_context, shape_type="Tessellation", body=[
    triangles([(29020.9, 24416.1, 0.0), (29224.0, 24416.1, 0.0), (29224.0, 24416.1, 3950.0), (29020.9, 24416.1, 3950.0), (29020.9, 25025.8, 0.0), (29020.9, 25025.8, 3950.0), (29224.0, 25025.8, 0.0), (29224.0, 25025.8, 3950.0)], [[1, 2, 3], [1, 3, 4], [5, 1, 4], [5, 4, 6], [7, 5, 6], [7, 6, 8], [2, 7, 8], [2, 8, 3], [5, 2, 1], [5, 7, 2], [3, 6, 4], [8, 6, 3]], closed=True),
])
wall_18_placement = place(storey_placement, origin())
element("IfcWall", 18, at=wall_18_placement, inside=storey, Name="F16_Walls_F16_046", context=model_context, shape_type="Tessellation", body=[
    triangles([(19374.1, 25025.8, 0.0), (22128.5, 25025.8, 0.0), (22128.5, 25025.8, 3950.0), (19374.1, 25025.8, 3950.0), (19374.1, 25419.5, 0.0), (19374.1, 25419.5, 3950.0), (22128.5, 25419.5, 0.0), (22128.5, 25419.5, 3950.0)], [[1, 2, 3], [1, 3, 4], [5, 1, 4], [5, 4, 6], [7, 5, 6], [7, 6, 8], [2, 7, 8], [2, 8, 3], [5, 2, 1], [5, 7, 2], [3, 6, 4], [8, 6, 3]], closed=True),
])
wall_19_placement = place(storey_placement, origin())
element("IfcWall", 19, at=wall_19_placement, inside=storey, Name="F16_Walls_F16_047", context=model_context, shape_type="Tessellation", body=[
    triangles([(31623.1, 25025.8, 0.0), (31623.1, 25419.5, 0.0), (31623.1, 25419.5, 3950.0), (31623.1, 25025.8, 3950.0), (29224.0, 25025.8, 0.0), (29224.0, 25025.8, 3950.0), (29224.0, 25419.5, 0.0), (29224.0, 25419.5, 3950.0)], [[1, 2, 3], [1, 3, 4], [5, 1, 4], [5, 4, 6], [7, 5, 6], [7, 6, 8], [2, 7, 8], [2, 8, 3], [7, 2, 1], [7, 1, 5], [3, 8, 4], [4, 8, 6]], closed=True),
])
wall_20_placement = place(storey_placement, origin())
element("IfcWall", 20, at=wall_20_placement, inside=storey, Name="F16_Walls_F16_048", context=model_context, shape_type="Tessellation", body=[
    triangles([(24730.6, 25025.8, 0.0), (24730.6, 25419.5, 0.0), (24730.6, 25419.5, 3950.0), (24730.6, 25025.8, 3950.0), (22331.6, 25025.8, 0.0), (22331.6, 25025.8, 3950.0), (22331.6, 25419.5, 0.0), (22331.6, 25419.5, 3950.0)], [[1, 2, 3], [1, 3, 4], [5, 1, 4], [5, 4, 6], [7, 5, 6], [7, 6, 8], [2, 7, 8], [2, 8, 3], [7, 2, 1], [7, 1, 5], [3, 8, 4], [4, 8, 6]], closed=True),
])
wall_21_placement = place(storey_placement, origin())
element("IfcWall", 21, at=wall_21_placement, inside=storey, Name="F16_Walls_F16_049", context=model_context, shape_type="Tessellation", body=[
    triangles([(43618.2, 16922.4, 0.0), (43618.2, 17074.8, 0.0), (43618.2, 17074.8, 3950.0), (43618.2, 16922.4, 3950.0), (40813.0, 16922.4, 0.0), (40813.0, 16922.4, 3950.0), (40813.0, 17074.8, 0.0), (40813.0, 17074.8, 3950.0)], [[1, 2, 3], [1, 3, 4], [5, 1, 4], [5, 4, 6], [7, 5, 6], [7, 6, 8], [2, 7, 8], [2, 8, 3], [5, 2, 1], [7, 2, 5], [3, 6, 4], [3, 8, 6]], closed=True),
])
wall_22_placement = place(storey_placement, origin())
element("IfcWall", 22, at=wall_22_placement, inside=storey, Name="F16_Walls_F16_050", context=model_context, shape_type="Tessellation", body=[
    triangles([(37665.0, 16922.4, 0.0), (37665.0, 16922.4, 3950.0), (37665.0, 17316.1, 3950.0), (37665.0, 17316.1, 0.0), (39099.4, 16922.4, 0.0), (39099.4, 16922.4, 3950.0), (39099.4, 17316.1, 0.0), (39099.4, 17316.1, 3950.0), (38720.0, 17316.1, 0.0), (38720.0, 17316.1, 3950.0), (38720.0, 19245.0, 0.0), (38720.0, 19245.0, 3950.0), (39100.0, 19245.0, 0.0), (39100.0, 19245.0, 3950.0), (39100.0, 19450.0, 0.0), (39100.0, 19450.0, 3950.0), (37665.0, 19450.0, 0.0), (37665.0, 19450.0, 3950.0), (37665.0, 25025.8, 0.0), (37665.0, 25025.8, 3950.0), (37474.6, 25025.8, 0.0), (37474.6, 25025.8, 3950.0), (37474.6, 19449.9, 0.0), (37474.6, 19449.9, 3950.0), (37474.6, 17316.1, 0.0), (37474.6, 17316.1, 3950.0), (37665.0, 18014.7, 0.0), (37665.0, 18014.7, 3950.0), (38565.0, 18014.7, 0.0), (38565.0, 18014.7, 3950.0), (38565.0, 17316.1, 0.0), (38565.0, 17316.1, 3950.0), (38565.0, 19245.0, 0.0), (38565.0, 18167.1, 0.0), (38565.0, 18167.1, 3950.0), (38565.0, 19245.0, 3950.0), (37665.0, 18167.1, 0.0), (37665.0, 18167.1, 3950.0), (37665.0, 19245.0, 0.0), (37665.0, 19245.0, 3950.0)], [[1, 2, 3], [4, 1, 3], [1, 5, 6], [1, 6, 2], [7, 8, 6], [5, 7, 6], [7, 9, 10], [7, 10, 8], [9, 11, 12], [9, 12, 10], [13, 14, 12], [11, 13, 12], [13, 15, 16], [13, 16, 14], [15, 17, 18], [15, 18, 16], [17, 19, 20], [17, 20, 18], [19, 21, 22], [19, 22, 20], [21, 23, 24], [21, 24, 22], [23, 25, 26], [23, 26, 24], [25, 4, 3], [25, 3, 26], [4, 27, 28], [4, 28, 3], [27, 29, 30], [27, 30, 28], [29, 31, 32], [29, 32, 30], [31, 4, 3], [31, 3, 32], [33, 34, 35], [33, 35, 36], [34, 37, 38], [34, 38, 35], [37, 39, 40], [37, 40, 38], [39, 33, 36], [39, 36, 40], [9, 7, 5], [31, 9, 5], [1, 31, 5], [29, 9, 31], [4, 31, 1], [27, 4, 25], [37, 29, 27], [37, 34, 29], [37, 27, 25], [11, 15, 13], [33, 11, 34], [33, 15, 11], [17, 33, 39], [17, 15, 33], [23, 39, 37], [23, 17, 39], [23, 37, 25], [21, 19, 17], [21, 17, 23], [11, 9, 29], [11, 29, 34], [8, 10, 6], [10, 32, 6], [32, 2, 6], [10, 30, 32], [32, 3, 2], [3, 28, 26], [30, 38, 28], [35, 38, 30], [28, 38, 26], [16, 12, 14], [12, 36, 35], [16, 36, 12], [36, 18, 40], [16, 18, 36], [40, 24, 38], [18, 24, 40], [38, 24, 26], [20, 22, 18], [18, 22, 24], [10, 12, 30], [30, 12, 35]], closed=True),
])
wall_23_placement = place(storey_placement, origin())
element("IfcWall", 23, at=wall_23_placement, inside=storey, Name="F16_Walls_F16_051", context=model_context, shape_type="Tessellation", body=[
    triangles([(33869.8, 17316.1, 0.0), (33869.8, 17316.1, 3950.0), (33869.8, 16922.4, 3950.0), (33869.8, 16922.4, 0.0), (31826.2, 16922.4, 0.0), (31826.2, 16922.4, 3950.0), (31826.2, 17316.1, 3950.0), (31826.2, 17316.1, 0.0)], [[1, 2, 3], [4, 1, 3], [5, 4, 3], [5, 3, 6], [5, 6, 7], [8, 5, 7], [1, 8, 7], [1, 7, 2], [8, 1, 4], [8, 4, 5], [2, 7, 3], [3, 7, 6]], closed=True),
])
wall_24_placement = place(storey_placement, origin())
element("IfcWall", 24, at=wall_24_placement, inside=storey, Name="F16_Walls_F16_052", context=model_context, shape_type="Tessellation", body=[
    triangles([(37474.6, 17316.1, 0.0), (37474.6, 17316.1, 3950.0), (37474.6, 16922.4, 3950.0), (37474.6, 16922.4, 0.0), (35469.1, 16922.4, 0.0), (35469.1, 16922.4, 3950.0), (35469.1, 17316.1, 3950.0), (35469.1, 17316.1, 0.0)], [[1, 2, 3], [4, 1, 3], [5, 4, 3], [5, 3, 6], [5, 6, 7], [8, 5, 7], [1, 8, 7], [1, 7, 2], [8, 1, 4], [8, 4, 5], [2, 7, 3], [3, 7, 6]], closed=True),
])
wall_25_placement = place(storey_placement, origin())
element("IfcWall", 25, at=wall_25_placement, inside=storey, Name="F16_Walls_F16_053", context=model_context, shape_type="Tessellation", body=[
    triangles([(40419.5, 17316.1, 0.0), (40419.5, 17316.1, 3950.0), (40419.5, 16922.4, 3950.0), (40419.5, 16922.4, 0.0), (40216.4, 16922.4, 0.0), (40216.4, 16922.4, 3950.0), (40216.4, 17316.1, 3950.0), (40216.4, 17316.1, 0.0)], [[1, 2, 3], [4, 1, 3], [5, 4, 3], [5, 3, 6], [5, 6, 7], [8, 5, 7], [1, 8, 7], [1, 7, 2], [8, 1, 4], [8, 4, 5], [2, 7, 3], [3, 7, 6]], closed=True),
])
wall_26_placement = place(storey_placement, origin())
element("IfcWall", 26, at=wall_26_placement, inside=storey, Name="F16_Walls_F16_054", context=model_context, shape_type="Tessellation", body=[
    triangles([(43770.5, 17074.8, 0.0), (43770.5, 18675.1, 0.0), (43770.5, 18675.1, 3950.0), (43770.5, 17074.8, 3950.0), (43618.2, 17074.8, 0.0), (43618.2, 17074.8, 3950.0), (43618.2, 18675.1, 0.0), (43618.2, 18675.1, 3950.0)], [[1, 2, 3], [1, 3, 4], [5, 1, 4], [5, 4, 6], [7, 5, 6], [7, 6, 8], [2, 7, 8], [2, 8, 3], [2, 1, 5], [7, 2, 5], [4, 3, 6], [3, 8, 6]], closed=True),
])
wall_27_placement = place(storey_placement, origin())
element("IfcWall", 27, at=wall_27_placement, inside=storey, Name="F16_Walls_F16_055", context=model_context, shape_type="Tessellation", body=[
    triangles([(34072.9, 17316.1, 0.0), (34072.9, 18649.7, 0.0), (34072.9, 18649.7, 3950.0), (34072.9, 17316.1, 3950.0), (33869.8, 17316.1, 0.0), (33869.8, 17316.1, 3950.0), (33869.8, 18649.7, 0.0), (33869.8, 18649.7, 3950.0)], [[1, 2, 3], [1, 3, 4], [5, 1, 4], [5, 4, 6], [7, 5, 6], [7, 6, 8], [2, 7, 8], [2, 8, 3], [7, 2, 1], [7, 1, 5], [3, 8, 4], [4, 8, 6]], closed=True),
])
wall_28_placement = place(storey_placement, origin())
element("IfcWall", 28, at=wall_28_placement, inside=storey, Name="F16_Walls_F16_056", context=model_context, shape_type="Tessellation", body=[
    triangles([(35469.1, 17316.1, 0.0), (35469.1, 18649.7, 0.0), (35469.1, 18649.7, 3950.0), (35469.1, 17316.1, 3950.0), (35266.0, 17316.1, 0.0), (35266.0, 17316.1, 3950.0), (35266.0, 18649.7, 0.0), (35266.0, 18649.7, 3950.0)], [[1, 2, 3], [1, 3, 4], [5, 1, 4], [5, 4, 6], [7, 5, 6], [7, 6, 8], [2, 7, 8], [2, 8, 3], [7, 2, 1], [7, 1, 5], [3, 8, 4], [4, 8, 6]], closed=True),
])
wall_29_placement = place(storey_placement, origin())
element("IfcWall", 29, at=wall_29_placement, inside=storey, Name="F16_Walls_F16_057", context=model_context, shape_type="Tessellation", body=[
    triangles([(40215.0, 19450.0, 0.0), (40215.0, 19245.0, 0.0), (40215.0, 19245.0, 3950.0), (40215.0, 19450.0, 3950.0), (40419.5, 19450.0, 3950.0), (40419.5, 19450.0, 0.0), (40419.5, 25025.8, 0.0), (40419.5, 25025.8, 3950.0), (40813.0, 25025.8, 0.0), (40813.0, 25025.8, 3950.0), (40813.0, 21774.3, 0.0), (40813.0, 21774.3, 3950.0), (43618.2, 21774.3, 0.0), (43618.2, 21774.3, 3950.0), (43618.2, 21621.8, 0.0), (43618.2, 21621.8, 3950.0), (40813.0, 21621.8, 0.0), (40813.0, 21621.8, 3950.0), (40813.0, 19449.9, 0.0), (40813.0, 19449.9, 3950.0), (40813.0, 17316.1, 0.0), (40813.0, 17316.1, 3950.0), (40419.5, 17316.1, 0.0), (40419.5, 17316.1, 3950.0), (40419.5, 19245.0, 0.0), (40419.5, 19245.0, 3950.0)], [[1, 2, 3], [1, 3, 4], [1, 4, 5], [6, 1, 5], [7, 6, 5], [7, 5, 8], [9, 7, 8], [9, 8, 10], [11, 9, 10], [11, 10, 12], [13, 11, 12], [13, 12, 14], [15, 13, 14], [15, 14, 16], [17, 15, 16], [17, 16, 18], [19, 17, 18], [19, 18, 20], [21, 19, 20], [21, 20, 22], [23, 21, 22], [23, 22, 24], [25, 23, 24], [25, 24, 26], [25, 26, 3], [2, 25, 3], [25, 19, 21], [25, 21, 23], [6, 25, 2], [6, 19, 25], [1, 6, 2], [17, 19, 6], [11, 13, 15], [11, 15, 17], [7, 9, 11], [6, 7, 11], [6, 11, 17], [20, 26, 22], [22, 26, 24], [26, 5, 3], [20, 5, 26], [5, 4, 3], [20, 18, 5], [14, 12, 16], [16, 12, 18], [10, 8, 12], [8, 5, 12], [12, 5, 18]], closed=True),
])
wall_30_placement = place(storey_placement, origin())
element("IfcWall", 30, at=wall_30_placement, inside=storey, Name="F16_Walls_F16_058", context=model_context, shape_type="Tessellation", body=[
    triangles([(34072.9, 19551.5, 0.0), (34072.9, 20872.5, 0.0), (34072.9, 20872.5, 3950.0), (34072.9, 19551.5, 3950.0), (33869.8, 19551.5, 0.0), (33869.8, 19551.5, 3950.0), (33869.8, 20872.5, 0.0), (33869.8, 20872.5, 3950.0)], [[1, 2, 3], [1, 3, 4], [5, 1, 4], [5, 4, 6], [7, 5, 6], [7, 6, 8], [2, 7, 8], [2, 8, 3], [7, 2, 1], [7, 1, 5], [3, 8, 4], [4, 8, 6]], closed=True),
])
wall_31_placement = place(storey_placement, origin())
element("IfcWall", 31, at=wall_31_placement, inside=storey, Name="F16_Walls_F16_059", context=model_context, shape_type="Tessellation", body=[
    triangles([(35126.4, 21075.7, 0.0), (35126.4, 20872.5, 0.0), (35126.4, 20872.5, 3950.0), (35126.4, 21075.7, 3950.0), (35266.0, 21075.7, 0.0), (35266.0, 21075.7, 3950.0), (35266.0, 25025.8, 3950.0), (35266.0, 25025.8, 0.0), (35469.1, 25025.8, 0.0), (35469.1, 25025.8, 3950.0), (35469.1, 21075.7, 3950.0), (35469.1, 21075.7, 0.0), (35469.1, 20872.5, 0.0), (35469.1, 20872.5, 3950.0), (35469.1, 19551.5, 0.0), (35469.1, 19551.5, 3950.0), (35266.0, 19551.5, 0.0), (35266.0, 19551.5, 3950.0), (35266.0, 20872.5, 0.0), (35266.0, 20872.5, 3950.0)], [[1, 2, 3], [1, 3, 4], [5, 1, 4], [5, 4, 6], [7, 5, 6], [8, 5, 7], [9, 8, 7], [9, 7, 10], [11, 9, 10], [12, 9, 11], [13, 12, 11], [13, 11, 14], [15, 13, 14], [15, 14, 16], [17, 15, 16], [17, 16, 18], [19, 17, 18], [19, 18, 20], [2, 19, 20], [2, 20, 3], [19, 13, 15], [19, 15, 17], [12, 13, 19], [5, 12, 19], [1, 19, 2], [1, 5, 19], [8, 9, 12], [8, 12, 5], [14, 20, 16], [16, 20, 18], [14, 11, 20], [11, 6, 20], [20, 4, 3], [6, 4, 20], [10, 7, 11], [11, 7, 6]], closed=True),
])
wall_32_placement = place(storey_placement, origin())
element("IfcWall", 32, at=wall_32_placement, inside=storey, Name="F16_Walls_F16_060", context=model_context, shape_type="Tessellation", body=[
    triangles([(33869.8, 20872.5, 0.0), (33869.8, 21075.7, 0.0), (33869.8, 21075.7, 3950.0), (33869.8, 20872.5, 3950.0), (31826.2, 20872.5, 0.0), (31826.2, 20872.5, 3950.0), (31826.2, 21075.7, 0.0), (31826.2, 21075.7, 3950.0)], [[1, 2, 3], [1, 3, 4], [5, 1, 4], [5, 4, 6], [7, 5, 6], [7, 6, 8], [2, 7, 8], [2, 8, 3], [7, 2, 1], [7, 1, 5], [3, 8, 4], [4, 8, 6]], closed=True),
])
wall_33_placement = place(storey_placement, origin())
element("IfcWall", 33, at=wall_33_placement, inside=storey, Name="F16_Walls_F16_061", context=model_context, shape_type="Tessellation", body=[
    triangles([(43770.5, 21774.3, 0.0), (43770.5, 23476.2, 0.0), (43770.5, 23476.2, 3950.0), (43770.5, 21774.3, 3950.0), (43618.2, 21774.3, 0.0), (43618.2, 21774.3, 3950.0), (43618.2, 23476.2, 0.0), (43618.2, 23476.2, 3950.0)], [[1, 2, 3], [1, 3, 4], [5, 1, 4], [5, 4, 6], [7, 5, 6], [7, 6, 8], [2, 7, 8], [2, 8, 3], [7, 2, 1], [7, 1, 5], [3, 8, 4], [4, 8, 6]], closed=True),
])
wall_34_placement = place(storey_placement, origin())
element("IfcWall", 34, at=wall_34_placement, inside=storey, Name="F16_Walls_F16_062", context=model_context, shape_type="Tessellation", body=[
    triangles([(31826.2, 21075.7, 0.0), (31826.2, 21075.7, 3950.0), (31623.1, 21075.7, 3950.0), (31623.1, 21075.7, 0.0), (31623.1, 25025.8, 3950.0), (31623.1, 25025.8, 0.0), (31826.2, 25025.8, 3950.0), (31826.2, 25025.8, 0.0)], [[1, 2, 3], [4, 1, 3], [5, 4, 3], [6, 4, 5], [6, 5, 7], [8, 6, 7], [2, 8, 7], [1, 8, 2], [8, 1, 4], [6, 8, 4], [2, 7, 3], [7, 5, 3]], closed=True),
])
wall_35_placement = place(storey_placement, origin())
element("IfcWall", 35, at=wall_35_placement, inside=storey, Name="F16_Walls_F16_064", context=model_context, shape_type="Tessellation", body=[
    triangles([(40419.5, 25025.8, 0.0), (40419.5, 25419.5, 0.0), (40419.5, 25419.5, 3950.0), (40419.5, 25025.8, 3950.0), (37665.0, 25025.8, 0.0), (37665.0, 25025.8, 3950.0), (37665.0, 25419.5, 0.0), (37665.0, 25419.5, 3950.0)], [[1, 2, 3], [1, 3, 4], [5, 1, 4], [5, 4, 6], [7, 5, 6], [7, 6, 8], [2, 7, 8], [2, 8, 3], [7, 2, 1], [7, 1, 5], [3, 8, 4], [4, 8, 6]], closed=True),
])
wall_36_placement = place(storey_placement, origin())
element("IfcWall", 36, at=wall_36_placement, inside=storey, Name="F16_Walls_F16_065", context=model_context, shape_type="Tessellation", body=[
    triangles([(35266.0, 25025.8, 0.0), (35266.0, 25419.5, 0.0), (35266.0, 25419.5, 3950.0), (35266.0, 25025.8, 3950.0), (31826.2, 25025.8, 0.0), (31826.2, 25025.8, 3950.0), (31826.2, 25419.5, 0.0), (31826.2, 25419.5, 3950.0)], [[1, 2, 3], [1, 3, 4], [5, 1, 4], [5, 4, 6], [7, 5, 6], [7, 6, 8], [2, 7, 8], [2, 8, 3], [7, 2, 1], [7, 1, 5], [3, 8, 4], [4, 8, 6]], closed=True),
])
wall_37_placement = place(storey_placement, origin())
element("IfcWall", 37, at=wall_37_placement, inside=storey, Name="F16_Walls_F16_066", context=model_context, shape_type="Tessellation", body=[
    triangles([(37474.6, 25025.8, 0.0), (37474.6, 25419.5, 0.0), (37474.6, 25419.5, 3950.0), (37474.6, 25025.8, 3950.0), (35469.1, 25025.8, 0.0), (35469.1, 25025.8, 3950.0), (35469.1, 25419.5, 0.0), (35469.1, 25419.5, 3950.0)], [[1, 2, 3], [1, 3, 4], [5, 1, 4], [5, 4, 6], [7, 5, 6], [7, 6, 8], [2, 7, 8], [2, 8, 3], [7, 2, 1], [7, 1, 5], [3, 8, 4], [4, 8, 6]], closed=True),
])
wall_38_placement = place(storey_placement, origin())
element("IfcWall", 38, at=wall_38_placement, inside=storey, Name="F16_Walls_F16_067", context=model_context, shape_type="Tessellation", body=[
    triangles([(45077.9, 14077.3, 0.0), (45077.9, 14521.8, 0.0), (45077.9, 14521.8, 3950.0), (45077.9, 14077.3, 3950.0), (44976.3, 14077.3, 0.0), (44976.3, 14077.3, 3950.0), (44976.3, 14521.8, 0.0), (44976.3, 14521.8, 3950.0)], [[1, 2, 3], [1, 3, 4], [5, 1, 4], [5, 4, 6], [7, 5, 6], [7, 6, 8], [2, 7, 8], [2, 8, 3], [7, 2, 1], [7, 1, 5], [3, 8, 4], [4, 8, 6]], closed=True),
])
wall_39_placement = place(storey_placement, origin())
element("IfcWall", 39, at=wall_39_placement, inside=storey, Name="F16_Walls_F16_068", context=model_context, shape_type="Tessellation", body=[
    triangles([(46512.2, 16922.4, 0.0), (46512.2, 17074.8, 0.0), (46512.2, 17074.8, 3950.0), (46512.2, 16922.4, 3950.0), (43770.5, 16922.4, 0.0), (43770.5, 16922.4, 3950.0), (43770.5, 17074.8, 0.0), (43770.5, 17074.8, 3950.0)], [[1, 2, 3], [1, 3, 4], [5, 1, 4], [5, 4, 6], [7, 5, 6], [7, 6, 8], [2, 7, 8], [2, 8, 3], [7, 2, 1], [7, 1, 5], [3, 8, 4], [4, 8, 6]], closed=True),
])
wall_40_placement = place(storey_placement, origin())
element("IfcWall", 40, at=wall_40_placement, inside=storey, Name="F16_Walls_F16_069", context=model_context, shape_type="Tessellation", body=[
    triangles([(46512.2, 17468.5, 0.0), (46512.2, 17074.8, 0.0), (46512.2, 17074.8, 3950.0), (46512.2, 17468.5, 3950.0), (46664.5, 17468.5, 0.0), (46664.5, 17468.5, 3950.0), (46664.5, 17620.9, 0.0), (46664.5, 17620.9, 3950.0), (47413.4, 17620.9, 0.0), (47413.4, 17620.9, 3950.0), (47413.4, 17468.5, 0.0), (47413.4, 17468.5, 3950.0), (47413.4, 17074.8, 0.0), (47413.4, 17074.8, 3950.0), (47413.4, 16922.4, 0.0), (47413.4, 16922.4, 3950.0), (46664.5, 16922.4, 0.0), (46664.5, 16922.4, 3950.0), (46664.5, 17074.8, 0.0), (46664.5, 17074.8, 3950.0)], [[1, 2, 3], [1, 3, 4], [5, 1, 4], [5, 4, 6], [7, 5, 6], [7, 6, 8], [9, 7, 8], [9, 8, 10], [11, 9, 10], [11, 10, 12], [13, 11, 12], [13, 12, 14], [15, 13, 14], [15, 14, 16], [17, 15, 16], [17, 16, 18], [19, 17, 18], [19, 18, 20], [2, 19, 20], [2, 20, 3], [17, 13, 15], [19, 13, 17], [5, 11, 13], [5, 19, 2], [5, 13, 19], [1, 5, 2], [7, 9, 11], [7, 11, 5], [14, 18, 16], [14, 20, 18], [12, 6, 14], [20, 6, 3], [14, 6, 20], [6, 4, 3], [10, 8, 12], [12, 8, 6]], closed=True),
])
wall_41_placement = place(storey_placement, origin())
element("IfcWall", 41, at=wall_41_placement, inside=storey, Name="F16_Walls_F16_070", context=model_context, shape_type="Tessellation", body=[
    triangles([(48111.6, 17620.9, 0.0), (48111.6, 17468.5, 0.0), (48111.6, 17468.5, 3950.0), (48111.6, 17620.9, 3950.0), (48568.5, 17620.9, 0.0), (48568.5, 17620.9, 3950.0), (48568.5, 17468.5, 0.0), (48568.5, 17468.5, 3950.0), (48708.1, 17468.5, 0.0), (48708.1, 17468.5, 3950.0), (48708.1, 17074.8, 0.0), (48708.1, 17074.8, 3950.0), (48568.5, 17074.8, 0.0), (48568.5, 17074.8, 3950.0), (48568.5, 16922.4, 0.0), (48568.5, 16922.4, 3950.0), (48111.6, 16922.4, 0.0), (48111.6, 16922.4, 3950.0), (48111.6, 17074.8, 0.0), (48111.6, 17074.8, 3950.0)], [[1, 2, 3], [1, 3, 4], [5, 1, 4], [5, 4, 6], [7, 5, 6], [7, 6, 8], [9, 7, 8], [9, 8, 10], [11, 9, 10], [11, 10, 12], [13, 11, 12], [13, 12, 14], [15, 13, 14], [15, 14, 16], [17, 15, 16], [17, 16, 18], [19, 17, 18], [19, 18, 20], [2, 19, 20], [2, 20, 3], [7, 9, 11], [7, 11, 13], [19, 13, 15], [19, 15, 17], [19, 7, 13], [2, 7, 19], [1, 5, 7], [1, 7, 2], [10, 8, 12], [12, 8, 14], [14, 20, 16], [16, 20, 18], [8, 20, 14], [8, 3, 20], [6, 4, 8], [8, 4, 3]], closed=True),
])
wall_42_placement = place(storey_placement, origin())
element("IfcWall", 42, at=wall_42_placement, inside=storey, Name="F16_Walls_F16_072", context=model_context, shape_type="Tessellation", body=[
    triangles([(46664.5, 18624.3, 0.0), (46664.5, 21101.1, 0.0), (46664.5, 21101.1, 3950.0), (46664.5, 18624.3, 3950.0), (46512.2, 18624.3, 0.0), (46512.2, 18624.3, 3950.0), (46512.2, 21101.1, 0.0), (46512.2, 21101.1, 3950.0)], [[1, 2, 3], [1, 3, 4], [5, 1, 4], [5, 4, 6], [7, 5, 6], [7, 6, 8], [2, 7, 8], [2, 8, 3], [7, 2, 1], [7, 1, 5], [3, 8, 4], [4, 8, 6]], closed=True),
])
wall_43_placement = place(storey_placement, origin())
element("IfcWall", 43, at=wall_43_placement, inside=storey, Name="F16_Walls_F16_074", context=model_context, shape_type="Tessellation", body=[
    triangles([(43618.2, 19919.9, 0.0), (43770.5, 19919.9, 0.0), (43770.5, 19919.9, 3950.0), (43618.2, 19919.9, 3950.0), (43618.2, 21101.1, 0.0), (43618.2, 21101.1, 3950.0), (43770.5, 21101.1, 0.0), (43770.5, 21101.1, 3950.0)], [[1, 2, 3], [1, 3, 4], [5, 1, 4], [5, 4, 6], [7, 5, 6], [7, 6, 8], [2, 7, 8], [2, 8, 3], [5, 2, 1], [5, 7, 2], [3, 6, 4], [8, 6, 3]], closed=True),
])
wall_44_placement = place(storey_placement, origin())
element("IfcWall", 44, at=wall_44_placement, inside=storey, Name="F16_Walls_F16_075", context=model_context, shape_type="Tessellation", body=[
    triangles([(43770.5, 21774.3, 0.0), (43770.5, 21621.8, 0.0), (43770.5, 21621.8, 3950.0), (43770.5, 21774.3, 3950.0), (46512.2, 21774.3, 0.0), (46512.2, 21774.3, 3950.0), (46512.2, 21621.8, 0.0), (46512.2, 21621.8, 3950.0), (46664.5, 21621.8, 0.0), (46664.5, 21621.8, 3950.0), (46664.5, 21240.8, 3950.0), (46664.5, 21240.8, 0.0), (46512.2, 21240.8, 0.0), (46512.2, 21240.8, 3950.0), (46512.2, 21101.1, 3950.0), (46512.2, 21101.1, 0.0), (43770.5, 21101.1, 0.0), (43770.5, 21101.1, 3950.0), (43770.5, 21240.0, 0.0), (43770.5, 21240.0, 3950.0), (43770.0, 21240.0, 0.0), (43770.0, 21240.0, 3950.0), (43770.0, 21240.8, 0.0), (43770.0, 21240.8, 3950.0), (43618.2, 21240.8, 3950.0), (43618.2, 21240.8, 0.0), (43618.2, 21621.8, 3950.0), (43618.2, 21621.8, 0.0)], [[1, 2, 3], [1, 3, 4], [5, 1, 4], [5, 4, 6], [7, 5, 6], [7, 6, 8], [9, 7, 8], [9, 8, 10], [9, 10, 11], [12, 9, 11], [13, 12, 11], [13, 11, 14], [13, 14, 15], [16, 13, 15], [17, 16, 15], [17, 15, 18], [19, 17, 18], [19, 18, 20], [21, 19, 20], [21, 20, 22], [23, 21, 22], [23, 22, 24], [23, 24, 25], [26, 23, 25], [26, 25, 27], [28, 26, 27], [2, 28, 27], [2, 27, 3], [9, 12, 13], [7, 9, 13], [19, 13, 16], [19, 16, 17], [23, 19, 21], [2, 7, 13], [2, 13, 19], [2, 19, 23], [28, 23, 26], [28, 2, 23], [1, 5, 7], [1, 7, 2], [11, 10, 14], [10, 8, 14], [14, 20, 15], [15, 20, 18], [20, 24, 22], [8, 3, 14], [14, 3, 20], [20, 3, 24], [24, 27, 25], [3, 27, 24], [6, 4, 8], [8, 4, 3]], closed=True),
])
wall_45_placement = place(storey_placement, origin())
element("IfcWall", 45, at=wall_45_placement, inside=storey, Name="F16_Walls_F16_078", context=model_context, shape_type="Tessellation", body=[
    triangles([(46664.5, 21774.3, 0.0), (46664.5, 23717.6, 0.0), (46664.5, 23717.6, 3950.0), (46664.5, 21774.3, 3950.0), (46512.2, 21774.3, 0.0), (46512.2, 21774.3, 3950.0), (46512.2, 23717.6, 0.0), (46512.2, 23717.6, 3950.0)], [[1, 2, 3], [1, 3, 4], [5, 1, 4], [5, 4, 6], [7, 5, 6], [7, 6, 8], [2, 7, 8], [2, 8, 3], [7, 2, 1], [7, 1, 5], [3, 8, 4], [4, 8, 6]], closed=True),
])

save(model, "model.ifc")
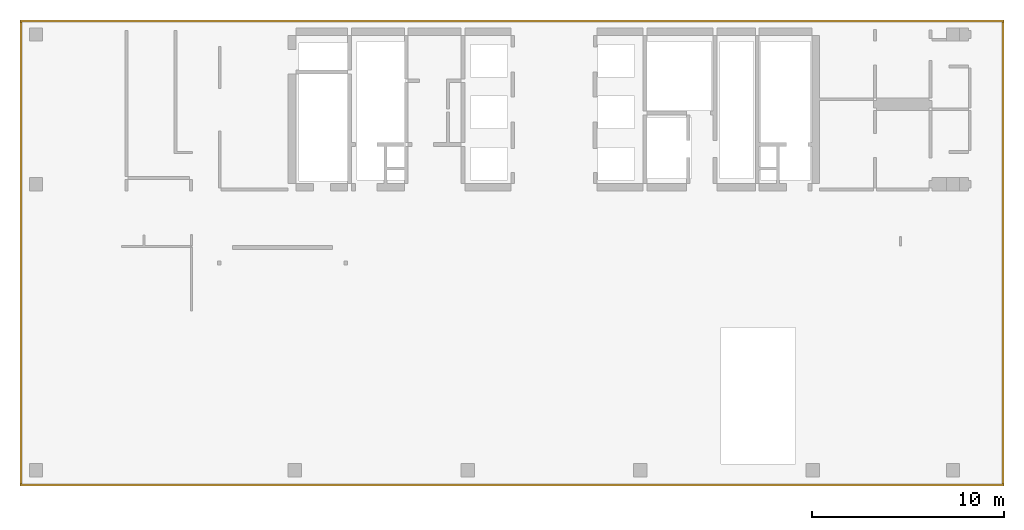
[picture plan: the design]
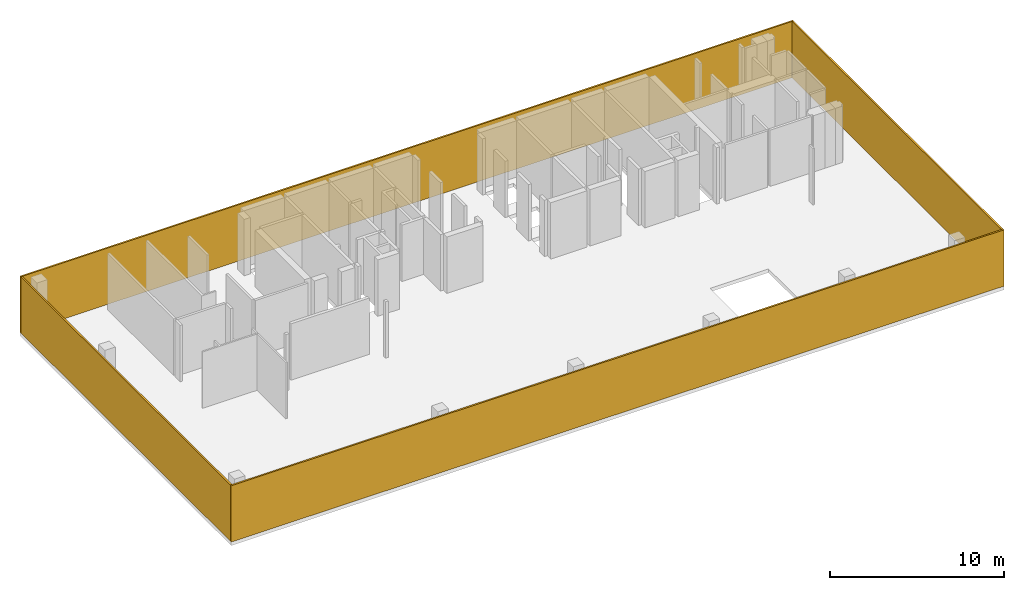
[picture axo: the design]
# One storey, part 4 of 4: 4 curtain walls.
"""IFC4 building model written with IfcOpenShell, lengths in millimetres."""

from ifc_helpers import new_model, si_unit, frame, origin, place, context, project, spatial, triangles, element, save


model = new_model("IFC4")

# Units and contexts
model_context = context("Model", 3, precision=0.001, world=origin())
ifc_project = project(units=[si_unit("LENGTHUNIT", "METRE", prefix="MILLI"), si_unit("AREAUNIT", "SQUARE_METRE"), si_unit("VOLUMEUNIT", "CUBIC_METRE")], contexts=[model_context])

# Site, building, storey
site_placement = place(None, origin())
site = spatial("IfcSite", under=ifc_project, at=site_placement, CompositionType="ELEMENT")
building_placement = place(site_placement, origin())
building = spatial("IfcBuilding", under=site, at=building_placement, CompositionType="ELEMENT")
storey_placement = place(building_placement, frame((0.0, 0.0, 68000.0)))
storey = spatial("IfcBuildingStorey", under=building, at=storey_placement, Name="F16", CompositionType="ELEMENT", Elevation=68000.0)

# Curtain walls
curtain_wall_1_placement = place(storey_placement, origin())
element("IfcCurtainWall", 1, at=curtain_wall_1_placement, inside=storey, Name="F16_Facade_F16_001", context=model_context, shape_type="Tessellation", body=[
    triangles([(50420.3187250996, 25825.974025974, 0.0), (-846.215139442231, 25825.974025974, 0.0), (-846.215139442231, 25825.974025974, 3950.0), (50420.3187250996, 25825.974025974, 3950.0), (50420.3187250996, 25720.1298701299, 0.0), (50420.3187250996, 25720.1298701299, 3950.0), (-846.215139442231, 25720.1298701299, 0.0), (-846.215139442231, 25720.1298701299, 3950.0)], [[1, 2, 3], [1, 3, 4], [5, 1, 4], [5, 4, 6], [7, 5, 6], [7, 6, 8], [2, 7, 8], [2, 8, 3], [2, 1, 5], [2, 5, 7], [4, 3, 6], [6, 3, 8]], closed=True),
])
curtain_wall_2_placement = place(storey_placement, origin())
element("IfcCurtainWall", 2, at=curtain_wall_2_placement, inside=storey, Name="F16_Facade_F16_002", context=model_context, shape_type="Tessellation", body=[
    triangles([(50420.3187250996, 1658.22510822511, 0.0), (-846.215139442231, 1658.22510822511, 0.0), (-846.215139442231, 1658.22510822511, 3950.0), (50420.3187250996, 1658.22510822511, 3950.0), (50420.3187250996, 1552.38095238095, 0.0), (50420.3187250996, 1552.38095238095, 3950.0), (-846.215139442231, 1552.38095238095, 0.0), (-846.215139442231, 1552.38095238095, 3950.0)], [[1, 2, 3], [1, 3, 4], [5, 1, 4], [5, 4, 6], [7, 5, 6], [7, 6, 8], [2, 7, 8], [2, 8, 3], [2, 1, 5], [2, 5, 7], [4, 3, 6], [6, 3, 8]], closed=True),
])
curtain_wall_3_placement = place(storey_placement, origin())
element("IfcCurtainWall", 3, at=curtain_wall_3_placement, inside=storey, Name="F16_Facade_F16_003", context=model_context, shape_type="Tessellation", body=[
    triangles([(-740.438247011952, 25720.1298701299, 0.0), (-846.215139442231, 25720.1298701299, 0.0), (-846.215139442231, 25720.1298701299, 3950.0), (-740.438247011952, 25720.1298701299, 3950.0), (-740.438247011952, 1658.22510822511, 0.0), (-740.438247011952, 1658.22510822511, 3950.0), (-846.215139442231, 1658.22510822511, 0.0), (-846.215139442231, 1658.22510822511, 3950.0)], [[1, 2, 3], [1, 3, 4], [5, 1, 4], [5, 4, 6], [7, 5, 6], [7, 6, 8], [2, 7, 8], [2, 8, 3], [2, 1, 5], [2, 5, 7], [4, 3, 6], [6, 3, 8]], closed=True),
])
curtain_wall_4_placement = place(storey_placement, origin())
element("IfcCurtainWall", 4, at=curtain_wall_4_placement, inside=storey, Name="F16_Facade_F16_004", context=model_context, shape_type="Tessellation", body=[
    triangles([(50420.3187250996, 25720.1298701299, 0.0), (50314.5418326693, 25720.1298701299, 0.0), (50314.5418326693, 25720.1298701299, 3950.0), (50420.3187250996, 25720.1298701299, 3950.0), (50420.3187250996, 1658.22510822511, 0.0), (50420.3187250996, 1658.22510822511, 3950.0), (50314.5418326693, 1658.22510822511, 0.0), (50314.5418326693, 1658.22510822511, 3950.0)], [[1, 2, 3], [1, 3, 4], [5, 1, 4], [5, 4, 6], [7, 5, 6], [7, 6, 8], [2, 7, 8], [2, 8, 3], [2, 1, 5], [2, 5, 7], [4, 3, 6], [6, 3, 8]], closed=True),
])

save(model, "model.ifc")
